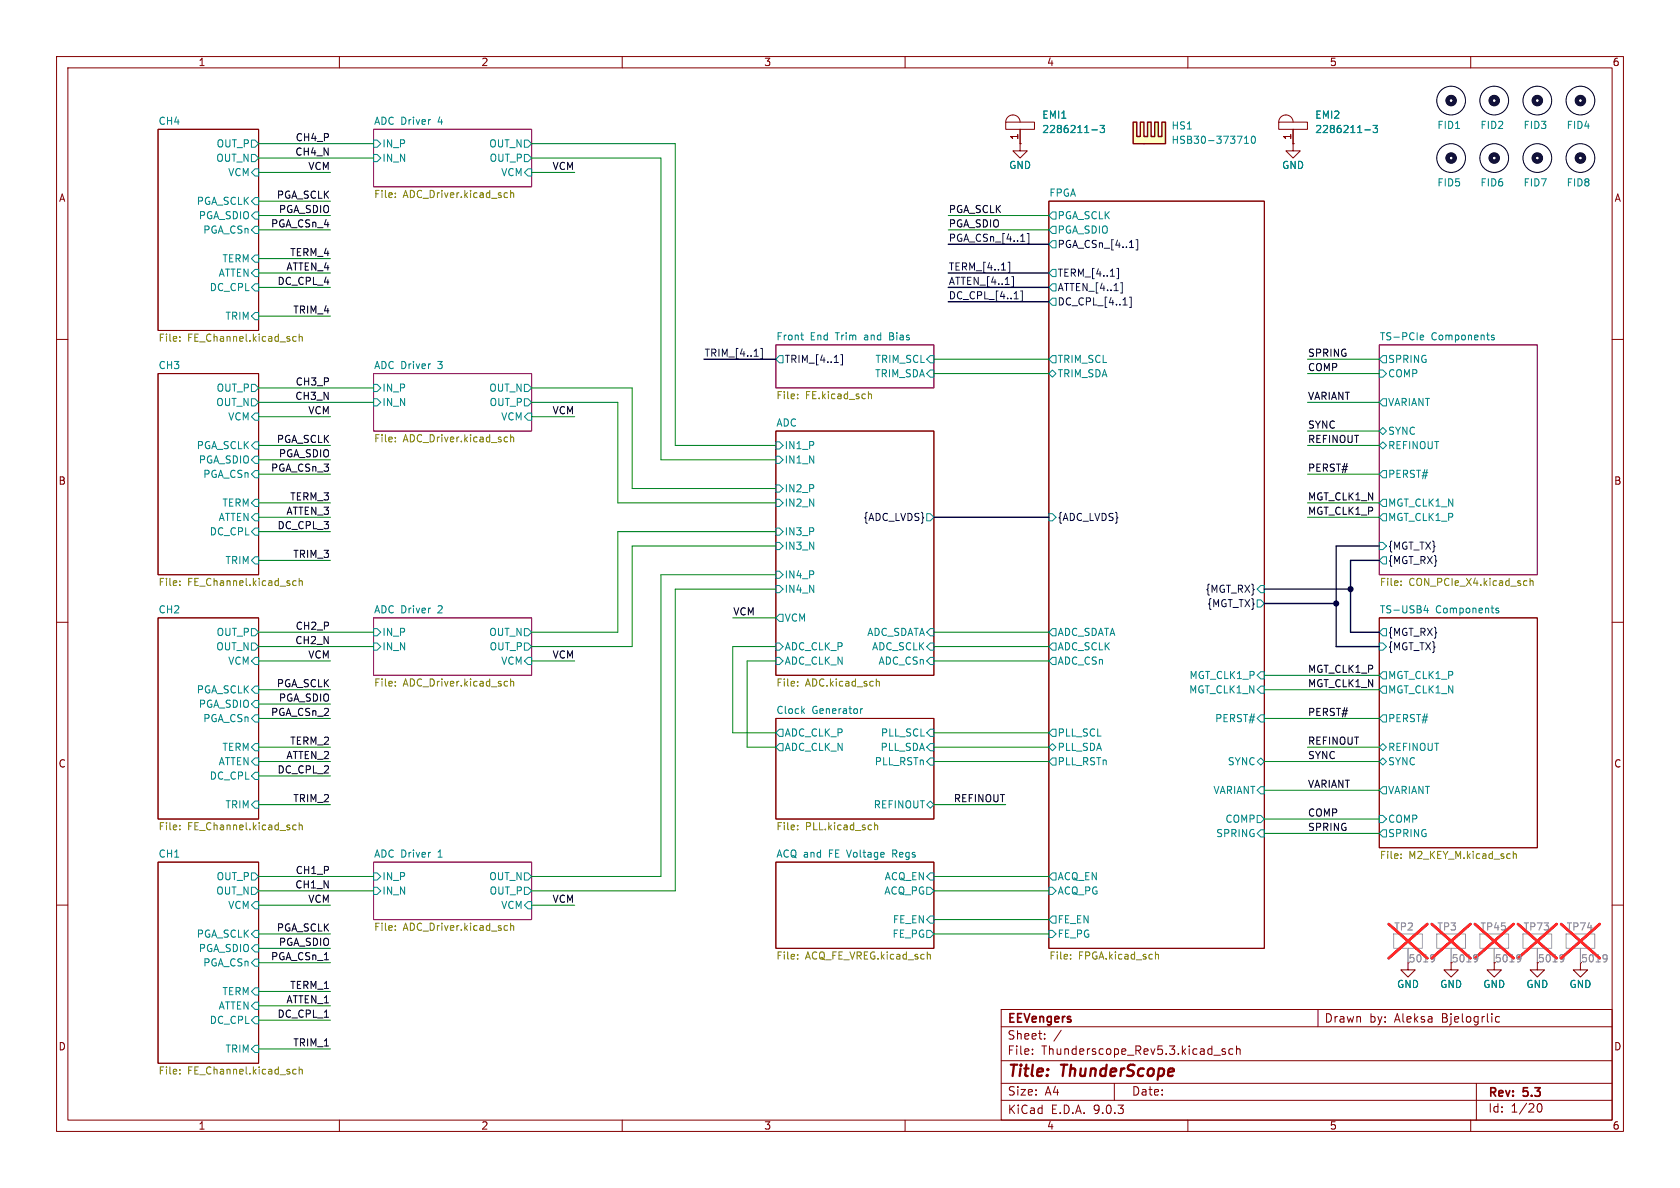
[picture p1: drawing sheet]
<svg xmlns="http://www.w3.org/2000/svg" width="297mm" height="210mm" viewBox="0 0 297 210" stroke-linecap="round" stroke-linejoin="round" font-family="sans-serif">
<defs><g id="words">
<g font-size="2.8" fill="#840000">
<text x="178" y="190.9">Title:</text>
<text x="187.7" y="190.9">ThunderScope</text>
</g>
<g font-size="2.1" fill="#840000">
<text x="178" y="184">Sheet:</text>
<text x="178" y="181.2">EEVengers</text>
<text x="234.1" y="181">Drawn</text>
<text x="242.1" y="181">by:</text>
<text x="246.6" y="181">Aleksa</text>
<text x="255" y="181">Bjelogrlic</text>
<text x="178" y="186.7">File:</text>
<text x="184.1" y="186.7">Thunderscope_Rev5.3.kicad_sch</text>
<text x="178.1" y="197.1">KiCad</text>
<text x="178.1" y="193.9">Size:</text>
<text x="184.7" y="193.9">A4</text>
<text x="185.8" y="197.1">E.D.A.</text>
<text x="193.4" y="197.1">9.0.3</text>
<text x="200" y="193.9">Date:</text>
<text x="263" y="194.3">Rev:</text>
<text x="263" y="196.9">Id:</text>
<text x="267.1" y="196.9">1/20</text>
<text x="269.4" y="194.3">5.3</text>
</g>
<g font-size="1.8" fill="#840000">
<text x="35" y="11.9">1</text>
<text x="85" y="11.9">2</text>
<text x="135" y="11.9">3</text>
<text x="185" y="11.9">4</text>
<text x="235" y="11.9">5</text>
<text x="285" y="11.9">6</text>
<text x="180.1" y="24.8" transform="rotate(-90 180.1 24.8)">1</text>
<text x="228.3" y="24.8" transform="rotate(-90 228.3 24.8)">1</text>
<text x="10.3" y="35.9">A</text>
<text x="285.3" y="35.9">A</text>
<text x="10.3" y="85.9">B</text>
<text x="285.3" y="85.9">B</text>
<text x="10.3" y="135.9">C</text>
<text x="285.3" y="135.9">C</text>
<text x="256.5" y="170.3">5019</text>
<text x="264.2" y="170.3">5019</text>
<text x="271.8" y="170.3">5019</text>
<text x="10.3" y="185.9">D</text>
<text x="285.3" y="185.9">D</text>
<text x="35" y="199.9">1</text>
<text x="85" y="199.9">2</text>
<text x="135" y="199.9">3</text>
<text x="185" y="199.9">4</text>
<text x="235" y="199.9">5</text>
<text x="285" y="199.9">6</text>
</g>
<g font-size="1.8" fill="#008484">
<text x="27.9" y="22.1">CH4</text>
<text x="66" y="22.1">ADC Driver</text>
<text x="77.5" y="22.1">4</text>
<text x="184.2" y="21.2">EMI1</text>
<text x="184.2" y="23.7">2286211-3</text>
<text x="207" y="23.1">HS1</text>
<text x="232.4" y="21.2">EMI2</text>
<text x="232.4" y="23.7">2286211-3</text>
<text x="254" y="23">FID1</text>
<text x="261.6" y="23">FID2</text>
<text x="269.2" y="23">FID3</text>
<text x="276.9" y="23">FID4</text>
<text x="38.1" y="28.8">OUT_N</text>
<text x="38.2" y="26.3">OUT_P</text>
<text x="67.5" y="28.8">IN_N</text>
<text x="67.5" y="26.3">IN_P</text>
<text x="86.4" y="26.3">OUT_N</text>
<text x="86.5" y="28.8">OUT_P</text>
<text x="207" y="25.6">HSB30-373710</text>
<text x="40.2" y="31.3">VCM</text>
<text x="88.5" y="31.3">VCM</text>
<text x="178.3" y="30.1">GND</text>
<text x="185.4" y="34.8">FPGA</text>
<text x="226.6" y="30.1">GND</text>
<text x="254" y="33.2">FID5</text>
<text x="261.6" y="33.2">FID6</text>
<text x="269.2" y="33.2">FID7</text>
<text x="276.9" y="33.2">FID8</text>
<text x="34.7" y="36.4">PGA_SCLK</text>
<text x="35" y="39">PGA_SDIO</text>
<text x="35.8" y="41.5">PGA_CSn</text>
<text x="186.9" y="41.5">PGA_SDIO</text>
<text x="186.9" y="39">PGA_SCLK</text>
<text x="39.2" y="46.6">TERM</text>
<text x="37" y="51.7">DC_CPL</text>
<text x="38.6" y="49.1">ATTEN</text>
<text x="39.8" y="56.7">TRIM</text>
<text x="27.9" y="65.3">CH3</text>
<text x="66" y="65.3">ADC Driver</text>
<text x="77.5" y="65.3">3</text>
<text x="137.2" y="60.2">Front</text>
<text x="143.2" y="60.2">End</text>
<text x="147.8" y="60.2">Trim</text>
<text x="153.1" y="60.2">and</text>
<text x="154.7" y="64.4">TRIM_SCL</text>
<text x="157.7" y="60.2">Bias</text>
<text x="186.9" y="64.4">TRIM_SCL</text>
<text x="243.8" y="60.2">TS-PCIe</text>
<text x="245.3" y="64.4">SPRING</text>
<text x="253" y="60.2">Components</text>
<text x="38.1" y="72">OUT_N</text>
<text x="38.2" y="69.4">OUT_P</text>
<text x="67.5" y="72">IN_N</text>
<text x="67.5" y="69.4">IN_P</text>
<text x="86.4" y="69.4">OUT_N</text>
<text x="86.5" y="72">OUT_P</text>
<text x="154.6" y="66.9">TRIM_SDA</text>
<text x="186.9" y="66.9">TRIM_SDA</text>
<text x="245.3" y="72">VARIANT</text>
<text x="245.3" y="66.9">COMP</text>
<text x="40.2" y="74.5">VCM</text>
<text x="88.5" y="74.5">VCM</text>
<text x="137.2" y="75.5">ADC</text>
<text x="245.3" y="77.1">SYNC</text>
<text x="34.7" y="79.6">PGA_SCLK</text>
<text x="35" y="82.1">PGA_SDIO</text>
<text x="138.6" y="82.1">IN1_N</text>
<text x="138.6" y="79.6">IN1_P</text>
<text x="245.3" y="79.6">REFINOUT</text>
<text x="35.8" y="84.7">PGA_CSn</text>
<text x="39.2" y="89.8">TERM</text>
<text x="138.6" y="89.8">IN2_N</text>
<text x="138.6" y="87.2">IN2_P</text>
<text x="245.3" y="84.7">PERST#</text>
<text x="245.3" y="89.8">MGT_CLK1_N</text>
<text x="37" y="94.8">DC_CPL</text>
<text x="38.6" y="92.3">ATTEN</text>
<text x="138.6" y="94.8">IN3_P</text>
<text x="245.3" y="92.3">MGT_CLK1_P</text>
<text x="39.8" y="99.9">TRIM</text>
<text x="138.6" y="97.4">IN3_N</text>
<text x="138.6" y="105">IN4_N</text>
<text x="138.6" y="102.5">IN4_P</text>
<text x="27.9" y="108.5">CH2</text>
<text x="38.2" y="112.6">OUT_P</text>
<text x="66" y="108.5">ADC Driver</text>
<text x="67.5" y="112.6">IN_P</text>
<text x="77.5" y="108.5">2</text>
<text x="86.4" y="112.6">OUT_N</text>
<text x="138.6" y="110.1">VCM</text>
<text x="153.2" y="112.6">ADC_SDATA</text>
<text x="186.9" y="112.6">ADC_SDATA</text>
<text x="243.8" y="108.5">TS-USB4</text>
<text x="253.8" y="108.5">Components</text>
<text x="38.1" y="115.2">OUT_N</text>
<text x="40.2" y="117.7">VCM</text>
<text x="67.5" y="115.2">IN_N</text>
<text x="86.5" y="115.2">OUT_P</text>
<text x="88.5" y="117.7">VCM</text>
<text x="138.6" y="115.2">ADC_CLK_P</text>
<text x="138.6" y="117.7">ADC_CLK_N</text>
<text x="154.1" y="115.2">ADC_SCLK</text>
<text x="155.2" y="117.7">ADC_CSn</text>
<text x="186.9" y="117.7">ADC_CSn</text>
<text x="186.9" y="115.2">ADC_SCLK</text>
<text x="34.7" y="122.8">PGA_SCLK</text>
<text x="35" y="125.3">PGA_SDIO</text>
<text x="210.1" y="122.8">MGT_CLK1_N</text>
<text x="210.2" y="120.2">MGT_CLK1_P</text>
<text x="245.3" y="122.8">MGT_CLK1_N</text>
<text x="245.3" y="120.2">MGT_CLK1_P</text>
<text x="35.8" y="127.9">PGA_CSn</text>
<text x="137.2" y="126.3">Clock</text>
<text x="138.6" y="130.4">ADC_CLK_P</text>
<text x="143.5" y="126.3">Generator</text>
<text x="155.6" y="130.4">PLL_SCL</text>
<text x="186.9" y="130.4">PLL_SCL</text>
<text x="214.7" y="127.9">PERST#</text>
<text x="245.3" y="127.9">PERST#</text>
<text x="38.6" y="135.5">ATTEN</text>
<text x="39.2" y="132.9">TERM</text>
<text x="138.6" y="132.9">ADC_CLK_N</text>
<text x="154.5" y="135.5">PLL_RSTn</text>
<text x="155.6" y="132.9">PLL_SDA</text>
<text x="186.9" y="135.5">PLL_RSTn</text>
<text x="186.9" y="132.9">PLL_SDA</text>
<text x="217" y="135.5">SYNC</text>
<text x="245.3" y="132.9">REFINOUT</text>
<text x="245.3" y="135.5">SYNC</text>
<text x="37" y="138">DC_CPL</text>
<text x="39.8" y="143.1">TRIM</text>
<text x="154.4" y="143.1">REFINOUT</text>
<text x="214.4" y="140.6">VARIANT</text>
<text x="245.3" y="140.6">VARIANT</text>
<text x="214.9" y="148.2">SPRING</text>
<text x="216.5" y="145.6">COMP</text>
<text x="245.3" y="148.2">SPRING</text>
<text x="245.3" y="145.6">COMP</text>
<text x="27.9" y="151.7">CH1</text>
<text x="38.2" y="155.8">OUT_P</text>
<text x="66" y="151.7">ADC Driver</text>
<text x="67.5" y="155.8">IN_P</text>
<text x="77.5" y="151.7">1</text>
<text x="86.4" y="155.8">OUT_N</text>
<text x="137.2" y="151.7">ACQ and</text>
<text x="146.6" y="151.7">FE Voltage</text>
<text x="156.3" y="155.8">ACQ_EN</text>
<text x="158.2" y="151.7">Regs</text>
<text x="186.9" y="155.8">ACQ_EN</text>
<text x="38.1" y="158.3">OUT_N</text>
<text x="40.2" y="160.9">VCM</text>
<text x="67.5" y="158.3">IN_N</text>
<text x="86.5" y="158.3">OUT_P</text>
<text x="88.5" y="160.9">VCM</text>
<text x="156.2" y="158.3">ACQ_PG</text>
<text x="186.9" y="158.3">ACQ_PG</text>
<text x="34.7" y="166">PGA_SCLK</text>
<text x="157.7" y="166">FE_PG</text>
<text x="157.8" y="163.4">FE_EN</text>
<text x="186.9" y="163.4">FE_EN</text>
<text x="186.9" y="166">FE_PG</text>
<text x="35" y="168.5">PGA_SDIO</text>
<text x="35.8" y="171">PGA_CSn</text>
<text x="38.6" y="178.7">ATTEN</text>
<text x="39.2" y="176.1">TERM</text>
<text x="246.9" y="174.9">GND</text>
<text x="254.5" y="174.9">GND</text>
<text x="262.1" y="174.9">GND</text>
<text x="269.7" y="174.9">GND</text>
<text x="277.4" y="174.9">GND</text>
<text x="37" y="181.2">DC_CPL</text>
<text x="39.8" y="186.3">TRIM</text>
</g>
<g font-size="1.8">
<text x="52.1" y="27.6">CH4_N</text>
<text x="52.2" y="25.1">CH4_P</text>
<text x="48.8" y="35.2">PGA_SCLK</text>
<text x="54.4" y="30.1">VCM</text>
<text x="97.6" y="30.1">VCM</text>
<text x="47.8" y="40.3">PGA_CSn_4</text>
<text x="49.2" y="37.8">PGA_SDIO</text>
<text x="167.6" y="40.3">PGA_SDIO</text>
<text x="167.6" y="37.8">PGA_SCLK</text>
<text x="50.5" y="47.9">ATTEN_4</text>
<text x="51.2" y="45.4">TERM_4</text>
<text x="49" y="50.5">DC_CPL_4</text>
<text x="51.7" y="55.5">TRIM_4</text>
<text x="231.1" y="63.2">SPRING</text>
<text x="231.1" y="65.7">COMP</text>
<text x="52.1" y="70.8">CH3_N</text>
<text x="52.2" y="68.2">CH3_P</text>
<text x="231.1" y="70.8">VARIANT</text>
<text x="54.4" y="73.3">VCM</text>
<text x="97.6" y="73.3">VCM</text>
<text x="231.1" y="75.9">SYNC</text>
<text x="47.8" y="83.5">PGA_CSn_3</text>
<text x="48.8" y="78.4">PGA_SCLK</text>
<text x="49.2" y="80.9">PGA_SDIO</text>
<text x="231.1" y="83.5">PERST#</text>
<text x="231.1" y="78.4">REFINOUT</text>
<text x="51.2" y="88.6">TERM_3</text>
<text x="231.1" y="88.6">MGT_CLK1_N</text>
<text x="49" y="93.6">DC_CPL_3</text>
<text x="50.5" y="91.1">ATTEN_3</text>
<text x="231.1" y="91.1">MGT_CLK1_P</text>
<text x="51.7" y="98.7">TRIM_3</text>
<text x="52.1" y="114">CH2_N</text>
<text x="52.2" y="111.4">CH2_P</text>
<text x="129.5" y="108.9">VCM</text>
<text x="54.4" y="116.5">VCM</text>
<text x="97.6" y="116.5">VCM</text>
<text x="231.1" y="119">MGT_CLK1_P</text>
<text x="48.8" y="121.6">PGA_SCLK</text>
<text x="49.2" y="124.1">PGA_SDIO</text>
<text x="231.1" y="121.6">MGT_CLK1_N</text>
<text x="47.8" y="126.7">PGA_CSn_2</text>
<text x="51.2" y="131.7">TERM_2</text>
<text x="231.1" y="126.7">PERST#</text>
<text x="231.1" y="131.7">REFINOUT</text>
<text x="49" y="136.8">DC_CPL_2</text>
<text x="50.5" y="134.3">ATTEN_2</text>
<text x="231.1" y="134.3">SYNC</text>
<text x="51.7" y="141.9">TRIM_2</text>
<text x="168.5" y="141.9">REFINOUT</text>
<text x="231.1" y="139.4">VARIANT</text>
<text x="231.1" y="144.4">COMP</text>
<text x="231.1" y="147">SPRING</text>
<text x="52.2" y="154.6">CH1_P</text>
<text x="52.1" y="157.1">CH1_N</text>
<text x="54.4" y="159.7">VCM</text>
<text x="97.6" y="159.7">VCM</text>
<text x="48.8" y="164.8">PGA_SCLK</text>
<text x="49.2" y="167.3">PGA_SDIO</text>
<text x="47.8" y="169.8">PGA_CSn_1</text>
<text x="49" y="180">DC_CPL_1</text>
<text x="50.5" y="177.5">ATTEN_1</text>
<text x="51.2" y="174.9">TERM_1</text>
<text x="51.7" y="185.1">TRIM_1</text>
</g>
<g font-size="1.8" fill="#848400">
<text x="66" y="35.3">File:</text>
<text x="71.3" y="35.3">ADC_Driver.kicad_sch</text>
<text x="27.9" y="60.7">File:</text>
<text x="33.2" y="60.7">FE_Channel.kicad_sch</text>
<text x="137.2" y="70.9">File:</text>
<text x="142.4" y="70.9">FE.kicad_sch</text>
<text x="66" y="78.5">File:</text>
<text x="71.3" y="78.5">ADC_Driver.kicad_sch</text>
<text x="27.9" y="103.9">File:</text>
<text x="33.2" y="103.9">FE_Channel.kicad_sch</text>
<text x="243.8" y="103.9">File:</text>
<text x="249.1" y="103.9">CON_PCIe_X4.kicad_sch</text>
<text x="66" y="121.7">File:</text>
<text x="71.3" y="121.7">ADC_Driver.kicad_sch</text>
<text x="137.2" y="121.7">File:</text>
<text x="142.4" y="121.7">ADC.kicad_sch</text>
<text x="27.9" y="147.1">File:</text>
<text x="33.2" y="147.1">FE_Channel.kicad_sch</text>
<text x="137.2" y="147.1">File:</text>
<text x="142.4" y="147.1">PLL.kicad_sch</text>
<text x="243.8" y="152.2">File:</text>
<text x="249.1" y="152.2">M2_KEY_M.kicad_sch</text>
<text x="66" y="164.9">File:</text>
<text x="71.3" y="164.9">ADC_Driver.kicad_sch</text>
<text x="137.2" y="170">File:</text>
<text x="142.4" y="170">ACQ_FE_VREG.kicad_sch</text>
<text x="185.4" y="170">File:</text>
<text x="190.6" y="170">FPGA.kicad_sch</text>
<text x="27.9" y="190.3">File:</text>
<text x="33.2" y="190.3">FE_Channel.kicad_sch</text>
</g>
<g font-size="1.8" fill="#000084">
<text x="167.6" y="47.9">TERM_[4..1]</text>
<text x="167.6" y="42.8">PGA_CSn_[4..1]</text>
<text x="186.9" y="44">PGA_CSn_[4..1]</text>
<text x="167.6" y="50.5">ATTEN_[4..1]</text>
<text x="167.6" y="53">DC_CPL_[4..1]</text>
<text x="186.9" y="51.7">ATTEN_[4..1]</text>
<text x="186.9" y="49.1">TERM_[4..1]</text>
<text x="186.9" y="54.2">DC_CPL_[4..1]</text>
<text x="124.5" y="63.2">TRIM_[4..1]</text>
<text x="138.6" y="64.4">TRIM_[4..1]</text>
<text x="152.6" y="92.3">{ADC_LVDS}</text>
<text x="186.9" y="92.3">{ADC_LVDS}</text>
<text x="245.3" y="99.9">{MGT_RX}</text>
<text x="245.3" y="97.4">{MGT_TX}</text>
<text x="213" y="105">{MGT_RX}</text>
<text x="213.3" y="107.5">{MGT_TX}</text>
<text x="245.3" y="112.6">{MGT_RX}</text>
<text x="245.3" y="115.2">{MGT_TX}</text>
</g>
<g font-size="1.8" fill="#a1a1a1">
<text x="246.4" y="164.7">TP2</text>
<text x="254" y="164.7">TP3</text>
<text x="261.6" y="164.7">TP45</text>
<text x="269.2" y="164.7">TP73</text>
<text x="276.9" y="164.7">TP74</text>
<text x="248.9" y="170.3">5019</text>
<text x="279.4" y="170.3">5019</text>
</g>
</g></defs>
<path d="M0 0h297v210h-297z" fill="#fff" stroke="#fff" stroke-width=".18"/>
<g fill="none" stroke="#840000" stroke-width=".18">
<path d="M10 10h277v190h-277zM12 12h273v186h-273zM60 10v2M110 10v2M160 10v2M210 10v2M260 10v2M177.8 21.6h5.1v1.3h-5.1zM177.8 21.6a1.27 1.27 0 0 1 1.3-1.3 1.27 1.27 0 0 1 1.2 1.3M180.3 25.4v1.3h1.3l-1.3 1.2-1.2-1.2h1.2M180.3 25.4h.1M180.3 22.9v2.5"/>
<path d="M226.1 21.6h5v1.3h-5zM226.1 21.6a1.27 1.27 0 0 1 1.2-1.3 1.27 1.27 0 0 1 1.3 1.3M228.6 25.4v1.3h1.3l-1.3 1.2-1.3-1.2h1.3M228.6 25.4h.1M228.6 22.9v2.5M10 60h2M285 60h2M10 110h2M285 110h2M10 160h2M177 178.5h108v19.5h-108zM233 178.5v3"/>
<path d="M248.9 170.2v1.3h1.3l-1.3 1.2-1.3-1.2h1.3M256.5 170.2v1.3h1.3l-1.3 1.2-1.2-1.2h1.2M264.2 170.2v1.3h1.2l-1.2 1.2-1.3-1.2h1.3M265.1 179.8l-.4-.1-.3 .3v.4l.1 .2h.6M271.8 170.2v1.3h1.2l-1.2 1.2-1.3-1.2h1.3M279.4 170.2v1.3h1.3l-1.3 1.2-1.3-1.2h1.3M285 160h2M60 198v2M110 198v2M160 198v2M177 194.5h108M177 191.5h108"/>
<path d="M177 187.5h108M177 181.5h108M182.5 186.3v.1M182.5 185.5v.1M184.7 183.6v.1M184.7 182.8v.1M187.6 182.1l-1.3 2M197 191.5v3M210 198v2M214.6 186.5h1.1M216.6 185.5l-.4-.1-.2 .2 .1 .2 .5 .2v.3h-.6M218 185.5l-.5-.1-.3 .3v.4l.2 .2h.6"/>
<path d="M218.6 185.5l.2-.1 .4 .1v.9M218.6 184.9v1.5M260 198v2M261 191.5v6.5M271.7 195.7l.2-.5 .2-.1a.81 .81 0 0 1 .6 .6 .81 .81 0 0 1-.3 .8h-.4l-.3-.5"/>
</g>
<path d="M27.9 22.9h17.8v35.5h-17.8zM185.4 35.6h38.1v132h-38.1zM27.9 66h17.8v35.6h-17.8zM137.2 76.2h27.9v43.2h-27.9zM27.9 109.2h17.8v35.6h-17.8zM243.8 109.2h28v40.7h-28zM137.2 127h27.9v17.8h-27.9zM27.9 152.4h17.8v35.6h-17.8zM137.2 152.4h27.9v15.2h-27.9z" fill="none" stroke="#800000" stroke-width=".18"/>
<path d="M66 22.9h28v10.1h-28zM66 66h28v10.2h-28zM137.2 61h27.9v7.6h-27.9zM243.8 61h28v40.6h-28zM66 109.2h28v10.2h-28zM66 152.4h28v10.2h-28z" fill="none" stroke="#840084" stroke-width=".18"/>
<g fill="none" stroke="#008484" stroke-width=".18">
<path d="M44.4 24.8h.7l.6 .6-.6 .6h-.7zM44.4 30.5l.7-.7h.6v1.3h-.6zM44.4 27.3h.7l.6 .6-.6 .7h-.7zM44.4 35.6l.7-.7h.6v1.3h-.6zM44.4 38.1l.7-.6h.6v1.2h-.6zM66 27.3h.7l.6 .6-.6 .7h-.7zM66 24.8h.7l.6 .6-.6 .6h-.7zM92.7 24.8h.6l.7 .6-.7 .6h-.6zM92.7 27.3h.6l.7 .6-.7 .7h-.6zM93.3 29.8h.7v1.3h-.7l-.6-.6zM186.1 37.5h.6v1.2h-.6l-.7-.6zM193 23h1"/>
<path d="M194.5 22.2h.8l-.5 .5 .4 .1v.5l-.2 .1-.5-.1M241.3 23h1M242.7 22.2h.8l-.4 .5 .4 .1v.5l-.2 .1-.6-.1M44.4 55.9l.7-.7h.6v1.3h-.6zM44.4 48.3l.7-.7h.6v1.3h-.6zM44.4 50.8l.7-.6h.6v1.2h-.6zM44.4 40.6l.7-.6h.6v1.3h-.6zM44.4 45.7l.7-.6h.6v1.3h-.6zM141.6 59.2h.4M186.1 40h.6v1.3h-.6l-.7-.7zM186.1 50.2h.6v1.2h-.6l-.7-.6zM186.1 47.6h.6v1.3h-.6l-.7-.6z"/>
<path d="M186.1 52.7h.6v1.3h-.6l-.7-.7zM186.1 42.5h.6v1.3h-.6l-.7-.6zM251.1 59.3l.4-.1 .2 .3-.6 .2M264.1 59.3l-.3-.1-.1 .2v.2l.4 .1v.3h-.4M44.4 67.9h.7l.6 .7-.6 .6h-.7zM44.4 73.7l.7-.7h.6v1.3h-.6zM44.4 70.5h.7l.6 .6-.6 .7h-.7zM44.4 78.7l.7-.6h.6v1.3h-.6zM66 70.5h.7l.6 .6-.6 .7h-.7zM66 67.9h.7l.6 .7-.6 .6h-.7zM92.7 67.9h.6l.7 .7-.7 .6h-.6zM92.7 70.5h.6l.7 .6-.7 .7h-.6z"/>
<path d="M93.3 73h.7v1.3h-.7l-.6-.6zM137.2 78.1h.6l.6 .6-.6 .7h-.6zM137.8 62.9h.6v1.2h-.6l-.6-.6zM141.8 60l.2 .1M164.5 62.9h.6v1.2h-.6l-.7-.6zM164.5 65.4h.6v1.3h-.6l-.7-.7zM185.4 66l.7-.6 .6 .6-.6 .7zM186.1 62.9h.6v1.2h-.6l-.7-.6zM243.8 78.7l.7-.6 .6 .6-.6 .7zM243.8 76.2l.7-.6 .6 .6-.6 .6zM243.8 65.4h.7l.6 .6-.6 .7h-.7zM244.5 70.5h.6v1.3h-.6l-.7-.7z"/>
<path d="M244.5 62.9h.6v1.2h-.6l-.7-.6zM251.1 60h.5M44.4 94l.7-.7h.6v1.3h-.6zM44.4 81.3l.7-.7h.6v1.3h-.6zM45.1 98.4h.6v1.3h-.6l-.7-.6zM45.1 90.8h.6v1.3h-.6l-.7-.7zM45.1 83.2h.6v1.3h-.6l-.7-.7zM45.1 88.3h.6v1.2h-.6l-.7-.6zM137.2 95.9h.6l.6 .6-.6 .7h-.6zM137.2 93.3h.6l.6 .7-.6 .6h-.6zM137.2 88.3h.6l.6 .6-.6 .6h-.6zM137.2 85.7h.6l.6 .7-.6 .6h-.6z"/>
<path d="M137.2 80.6h.6l.6 .7-.6 .6h-.6zM163.8 90.8h.7l.6 .6-.6 .7h-.7zM185.4 90.8h.7l.6 .6-.6 .7h-.7zM243.8 95.9h.7l.6 .6-.6 .7h-.7zM244.5 98.4h.6v1.3h-.6l-.7-.6zM244.5 83.2h.6v1.3h-.6l-.7-.7zM244.5 88.3h.6v1.2h-.6l-.7-.6zM244.5 90.8h.6v1.3h-.6l-.7-.7zM44.4 111.1h.7l.6 .7-.6 .6h-.7zM44.4 116.8l.7-.6h.6v1.3h-.6zM44.4 113.7h.7l.6 .6-.6 .6h-.7zM66 113.7h.7l.6 .6-.6 .6h-.7z"/>
<path d="M66 111.1h.7l.6 .7-.6 .6h-.7zM92.7 111.1h.6l.7 .7-.7 .6h-.6zM92.7 113.7h.6l.7 .6-.7 .6h-.6zM93.3 116.2h.7v1.3h-.7l-.6-.7zM137.2 103.5h.6l.6 .6-.6 .7h-.6zM137.2 101h.6l.6 .6-.6 .6h-.6zM137.2 109.2l.6-.6h.6v1.3h-.6zM137.2 113.7h.6l.6 .6-.6 .6h-.6zM137.2 116.2h.6l.6 .6-.6 .7h-.6zM164.5 116.2h.6v1.3h-.6l-.7-.7zM164.5 111.1h.6v1.3h-.6l-.7-.6zM164.5 113.7h.6v1.2h-.6l-.7-.6z"/>
<path d="M186.1 116.2h.6v1.3h-.6l-.7-.7zM186.1 111.1h.6v1.3h-.6l-.7-.6zM186.1 113.7h.6v1.2h-.6l-.7-.6zM222.2 106h.7l.6 .7-.6 .6h-.7zM222.9 118.7h.6v1.3h-.6l-.7-.6zM222.9 103.5h.6v1.3h-.6l-.7-.7zM243.8 113.7h.7l.6 .6-.6 .6h-.7zM244.5 111.1h.6v1.3h-.6l-.7-.6zM244.5 118.7h.6v1.3h-.6l-.7-.6zM252 107l-.3 .9h.8M252.3 107.5v.8M264.9 107.6l-.3-.1-.2 .2 .1 .2 .4 .1v.3h-.5"/>
<path d="M44.4 134.6l.7-.6h.6v1.3h-.6zM45.1 136.5h.6v1.3h-.6l-.7-.6zM45.1 126.4h.6v1.2h-.6l-.7-.6zM45.1 121.3h.6v1.3h-.6l-.7-.7zM45.1 123.8h.6v1.3h-.6l-.7-.6zM45.1 131.4h.6v1.3h-.6l-.7-.6zM137.2 129.5l.6-.6h.6v1.3h-.6zM137.8 131.4h.6v1.3h-.6l-.6-.6zM141.9 125.6l.3 .5M142.2 125.3l-.5 .5M152.1 125.3v.8M152.5 125.3l-.4 .2"/>
<path d="M164.5 134h.6v1.3h-.6l-.7-.7zM164.5 131.4h.6v1.3h-.6l-.7-.6zM164.5 128.9h.6v1.3h-.6l-.7-.7zM185.4 132.1l.7-.7 .6 .7-.6 .6zM186.1 134h.6v1.3h-.6l-.7-.7zM186.1 128.9h.6v1.3h-.6l-.7-.7zM222.2 134.6l.7-.6 .6 .6-.6 .7zM222.9 126.4h.6v1.2h-.6l-.7-.6zM222.9 121.3h.6v1.3h-.6l-.7-.7zM222.9 139.1h.6v1.2h-.6l-.7-.6zM243.8 132.1l.7-.7 .6 .7-.6 .6zM243.8 134.6l.7-.6 .6 .6-.6 .7z"/>
<path d="M244.5 126.4h.6v1.2h-.6l-.7-.6zM244.5 121.3h.6v1.3h-.6l-.7-.7zM244.5 139.1h.6v1.2h-.6l-.7-.6zM44.4 154.3h.7l.6 .6-.6 .7h-.7zM44.4 156.8h.7l.6 .7-.6 .6h-.7zM45.1 141.6h.6v1.3h-.6l-.7-.7zM45.1 159.4h.6v1.3h-.6l-.7-.7zM66 156.8h.7l.6 .7-.6 .6h-.7zM66 154.3h.7l.6 .6-.6 .7h-.7zM92.7 154.3h.6l.7 .6-.7 .7h-.6zM92.7 156.8h.6l.7 .7-.7 .6h-.6zM93.3 159.4h.7v1.3h-.7l-.6-.7z"/>
<path d="M163.8 142.2l.7-.6 .6 .6-.6 .7zM163.8 156.8h.7l.6 .7-.6 .6h-.7zM164.5 154.3h.6v1.3h-.6l-.7-.7zM185.4 156.8h.7l.6 .7-.6 .6h-.7zM186.1 154.3h.6v1.3h-.6l-.7-.7zM222.2 144.1h.7l.6 .7-.6 .6h-.7zM222.9 146.7h.6v1.3h-.6l-.7-.7zM243.8 144.1h.7l.6 .7-.6 .6h-.7zM244.5 146.7h.6v1.3h-.6l-.7-.7zM44.4 170.2l.7-.7h.6v1.3h-.6zM44.4 175.3l.7-.7h.6v1.3h-.6zM45.1 177.2h.6v1.2h-.6l-.7-.6z"/>
<path d="M45.1 164.5h.6v1.2h-.6l-.7-.6zM45.1 167h.6v1.3h-.6l-.7-.7zM163.8 164.5h.7l.6 .6-.6 .6h-.7zM164.5 161.9h.6v1.3h-.6l-.7-.6zM185.4 164.5h.7l.6 .6-.6 .6h-.7zM186.1 161.9h.6v1.3h-.6l-.7-.6zM44.4 185.4l.7-.6h.6v1.3h-.6zM44.4 180.3l.7-.6h.6v1.3h-.6z"/>
</g>
<g fill="none" stroke="#848400" stroke-width=".18">
<path d="M69.9 34.1v.2M69.9 34.8v.1M89.4 34.1h.3M89.7 34.9h-.3M90.3 33.7v1.2M90.3 34.2l.2-.1h.3v.8M31.8 59.5v.2M52.4 59.5h-.4l-.2 .1M52.9 59.1v1.2M52.9 59.6l.2-.1h.3v.8M31.8 60.2v.1M51.8 60.2l.2 .1h.4"/>
<path d="M69.9 77.3v.1M69.9 78v.1M89.4 77.3h.3M89.7 78l-.3 .1M90.3 76.8v1.3M90.3 77.4l.2-.1h.3v.8M141 70.4v.1M141 69.7v.1M153.5 69.2v1.3M153.5 69.8l.2-.2 .3 .1 .1 .8M31.8 103.4v.1M31.8 102.7v.1"/>
<path d="M51.8 103.4l.2 .1 .4-.1M52.4 102.7h-.4l-.2 .1M52.9 102.8l.2-.1h.3v.8M52.9 102.2v1.3M247.7 102.7v.1M247.7 103.4v.1M269.8 102.7h.1M269.9 103.4l-.1 .1M270.5 102.8l.2-.1h.3v.8M270.5 102.2v1.3M69.9 120.5v.1M69.9 121.2v.1"/>
<path d="M89.4 120.4l.3 .1M89.7 121.2l-.3 .1M90.3 120.6l.2-.2 .3 .1v.8M90.3 120v1.3M141 120.5v.1M141 121.2v.1M154.9 120.6l.2-.2 .3 .1 .1 .8M31.8 145.9v.1M31.8 146.6v.1M51.8 146.6l.2 .1 .4-.1M52.4 145.9l-.4-.1-.2 .2M52.9 145.4v1.3"/>
<path d="M52.9 146l.2-.2 .3 .1v.8M141 145.9v.1M141 146.6v.1M154.6 145.4v1.3M154.6 146l.2-.2 .3 .1 .1 .8M247.7 151.6v.2M247.7 151v.1M267.5 150.5v1.3M267.5 151l.2-.1 .3 .1 .1 .8M69.9 164.3v.2M69.9 163.7v.1M89.4 163.6l.3 .1"/>
<path d="M89.7 164.4l-.3 .1M90.3 163.7l.2-.1 .3 .1v.8M90.3 163.2v1.3M141 168.8v.1M141 169.4v.1M164.3 168.7l.2 .2v.6M189.3 169.4v.1M189.3 168.8v.1M204.3 168.8l.1-.1 .4 .1v.7M31.8 189.1v.1M31.8 189.7v.2M51.8 189.7l.2 .2 .4-.1"/>
<path d="M52.4 189.1l-.4-.1-.2 .1M52.9 188.6v1.3M52.9 189.1l.2-.1 .3 .1v.8"/>
</g>
<path d="M197.4 47.4h.3v1.9h-.3M198.1 50h.3v1.8h-.3M199.7 52.5h.3v1.8h-.3M200.8 42.4h.3v1.8h-.3M148.6 62.7h.3v1.8h-.3" fill="none" stroke="#000084" stroke-width=".18"/>
<g fill="none" stroke="#a1a1a1" stroke-width=".18">
<path d="M246.4 165.1h5.1v2.5h-5.1zM248.9 167.6v2.6M253.4 168.8l.2 .1a1.03 1.03 0 0 1-.2 1.1M253.6 169.3l-.2 .3M254 165.1h5.1v2.5h-5.1zM256.5 167.6v2.6M261 168.8l.2 .1a1.03 1.03 0 0 1-.2 1.1M261.2 169.3l-.2 .3M261.6 165.1h5.1v2.5h-5.1zM264.2 167.6v2.6M268.6 168.8l.2 .1a1.03 1.03 0 0 1-.2 1.1M268.9 169.3l-.3 .3"/>
<path d="M269.2 165.1h5.1v2.5h-5.1zM271.8 167.6v2.6M276.2 168.8l.2 .1a1.03 1.03 0 0 1-.2 1.1M276.5 169.3l-.3 .3M276.9 165.1h5v2.5h-5zM279.4 167.6v2.6M283.9 168.8l.1 .1a1.03 1.03 0 0 1-.1 1.1M284.1 169.3l-.2 .3"/>
</g>
<path d="M245.5 163.3l6.8 6.1M252.3 163.3l-6.8 6.1M253.1 163.3l6.9 6.1M260 163.3l-6.9 6.1M260.7 163.3l6.9 6.1M267.6 163.3l-6.9 6.1M268.4 163.3l6.8 6.1M275.2 163.3l-6.8 6.1M276 163.3l6.8 6.1M282.8 163.3l-6.8 6.1" fill="none" stroke="#ff2626" stroke-width=".46"/>
<g fill="none" stroke="#000" stroke-width=".76">
<circle cx="256.5" cy="17.8" r=".63"/>
<circle cx="264.2" cy="17.8" r=".63"/>
<circle cx="271.8" cy="17.8" r=".63"/>
<circle cx="279.4" cy="17.8" r=".63"/>
<circle cx="256.5" cy="27.9" r=".63"/>
<circle cx="264.2" cy="27.9" r=".63"/>
<circle cx="271.8" cy="27.9" r=".63"/>
<circle cx="279.4" cy="27.9" r=".63"/>
</g>
<g fill="none" stroke="#000" stroke-width=".18">
<circle cx="256.5" cy="17.8" r="2.54"/>
<circle cx="264.2" cy="17.8" r="2.54"/>
<circle cx="271.8" cy="17.8" r="2.54"/>
<circle cx="279.4" cy="17.8" r="2.54"/>
<circle cx="256.5" cy="27.9" r="2.54"/>
<circle cx="264.2" cy="27.9" r="2.54"/>
<circle cx="271.8" cy="27.9" r="2.54"/>
<circle cx="279.4" cy="27.9" r="2.54"/>
</g>
<g fill="#ffffc2">
<path d="M200.3 21.6h.7v2.5h.6v-2.5h.6v2.5h.7l-.7 1.3h-1.9z"/>
<path d="M202.9 21.6h.6v2.5h.6v-2.5h.7v2.5h.6v-2.5h.6v3.8h-3.8l.7-1.3z"/>
</g>
<path d="M200.3 21.6h.7v2.5h.6v-2.5h.6v2.5h.7v-2.5h.6v2.5h.6v-2.5h.7v2.5h.6v-2.5h.6v3.8h-5.7z" fill="none" stroke="#840000" stroke-width=".25"/>
<path d="M193 23h1M194.5 22.2h.8l-.5 .5 .4 .1v.5l-.2 .1-.5-.1M220 25.3h.7M220 24.4l.4-.3v1.2M221.3 24.2l.2-.1a.68 .68 0 0 1 .5 .6 .68 .68 0 0 1-.5 .6l-.2-.1-.1-.3zM241.3 23h1M242.7 22.2h.8l-.4 .5 .4 .1v.5l-.2 .1-.6-.1" fill="none" stroke="#008484" stroke-width=".18"/>
<path d="M178.2 46.4h.3v1.8h-.3M178.9 48.9h.3v1.8h-.3M180.4 51.4h.3v1.9h-.3M181.6 41.3h.3v1.8h-.3M134.5 61.6h.3v1.8h-.3" fill="none" stroke="#000084" stroke-width=".18"/>
<path d="M167.6 50.8h17.8M167.6 43.2h17.8M167.6 48.3h17.8M167.6 53.3h17.8M124.5 63.5h12.7M165.1 91.4h20.3M243.8 99.1h-5v12.7h5M243.8 96.5h-7.6v17.8h7.6M223.5 106.7h12.7M223.5 104.1h15.3" fill="none" stroke="#000084" stroke-width=".25"/>
<g fill="none" stroke="#008400" stroke-width=".18">
<path d="M45.7 25.4h20.3M45.7 27.9h20.3M45.7 35.6h12.7M45.7 38.1h12.7M45.7 30.5h12.7M94 25.4h25.4v53.3h17.8M94 27.9h22.8v53.4h20.4M94 30.5h7.6M167.6 38.1h17.8M45.7 40.6h12.7M45.7 45.7h12.7M45.7 55.9h12.7"/>
<path d="M45.7 50.8h12.7M45.7 48.3h12.7M167.6 40.6h17.8M45.7 73.7h12.7M45.7 71.1h20.3M45.7 68.6h20.3M45.7 78.7h12.7M94 73.7h7.6M94 71.1h15.2v17.8h28M94 68.6h17.8v17.8h25.4M165.1 63.5h20.3M165.1 66h20.3"/>
<path d="M231.1 71.1h12.7M231.1 63.5h12.7M231.1 66h12.7M231.1 78.7h12.7M231.1 76.2h12.7M45.7 88.9h12.7M45.7 91.4h12.7M45.7 99.1h12.7M45.7 94h12.7M45.7 81.3h12.7M45.7 83.8h12.7M137.2 96.5h-25.4v17.8h-17.8"/>
<path d="M137.2 94h-28v17.8h-15.2M231.1 88.9h12.7M231.1 91.4h12.7M231.1 83.8h12.7M45.7 114.3h20.3M45.7 116.8h12.7M45.7 111.8h20.3M94 116.8h7.6M129.5 109.2h7.7M137.2 104.1h-17.8v53.4h-25.4M137.2 101.6h-20.4v53.3h-22.8M137.2 116.8h-5.1v15.3h5.1"/>
<path d="M137.2 114.3h-7.7v15.2h7.7M165.1 114.3h20.3M165.1 116.8h20.3M165.1 111.8h20.3M223.5 119.4h20.3M45.7 137.2h12.7M45.7 134.6h12.7M45.7 121.9h12.7M45.7 132.1h12.7M45.7 127h12.7M45.7 124.5h12.7M165.1 134.6h20.3"/>
<path d="M165.1 132.1h20.3M165.1 129.5h20.3M223.5 134.6h20.3M223.5 121.9h20.3M223.5 127h20.3M223.5 139.7h20.3M231.1 132.1h12.7M45.7 142.2h12.7M45.7 157.5h20.3M45.7 154.9h20.3M165.1 142.2h12.7M165.1 157.5h20.3"/>
<path d="M165.1 154.9h20.3M223.5 144.8h20.3M223.5 147.3h20.3M45.7 177.8h12.7M45.7 170.2h12.7M45.7 167.6h12.7M45.7 175.3h12.7M45.7 165.1h12.7M45.7 160h12.7M94 160h7.6M165.1 165.1h20.3M165.1 162.6h20.3"/>
<path d="M45.7 180.3h12.7M45.7 185.4h12.7"/>
</g>
<g fill="none" stroke="#a1a1a1" stroke-width=".18">
<path d="M248.9 167.6v2.6M253.4 168.8l.2 .1a1.03 1.03 0 0 1-.2 1.1M253.6 169.3l-.2 .3M256.5 167.6v2.6M261 168.8l.2 .1a1.03 1.03 0 0 1-.2 1.1M261.2 169.3l-.2 .3M264.2 167.6v2.6M268.6 168.8l.2 .1a1.03 1.03 0 0 1-.2 1.1M268.9 169.3l-.3 .3M271.8 167.6v2.6M276.2 168.8l.2 .1a1.03 1.03 0 0 1-.2 1.1M276.5 169.3l-.3 .3"/>
<path d="M279.4 167.6v2.6M283.9 168.8l.1 .1a1.03 1.03 0 0 1-.1 1.1M284.1 169.3l-.2 .3"/>
</g>
<path d="M245.5 163.3l6.8 6.1M252.3 163.3l-6.8 6.1M253.1 163.3l6.9 6.1M260 163.3l-6.9 6.1M260.7 163.3l6.9 6.1M267.6 163.3l-6.9 6.1M268.4 163.3l6.8 6.1M275.2 163.3l-6.8 6.1M276 163.3l6.8 6.1M282.8 163.3l-6.8 6.1" fill="none" stroke="#ff2626" stroke-width=".46"/>
<path d="M180.3 25.4h.1M180.3 22.9v2.5M228.6 25.4h.1M228.6 22.9v2.5" fill="none" stroke="#840000" stroke-width=".18"/>
<g fill="#000084" stroke="#000084" stroke-width=".18">
<circle cx="238.8" cy="104.1" r=".46"/>
<circle cx="236.2" cy="106.7" r=".46"/>
</g>
<use href="#words"/>
</svg>
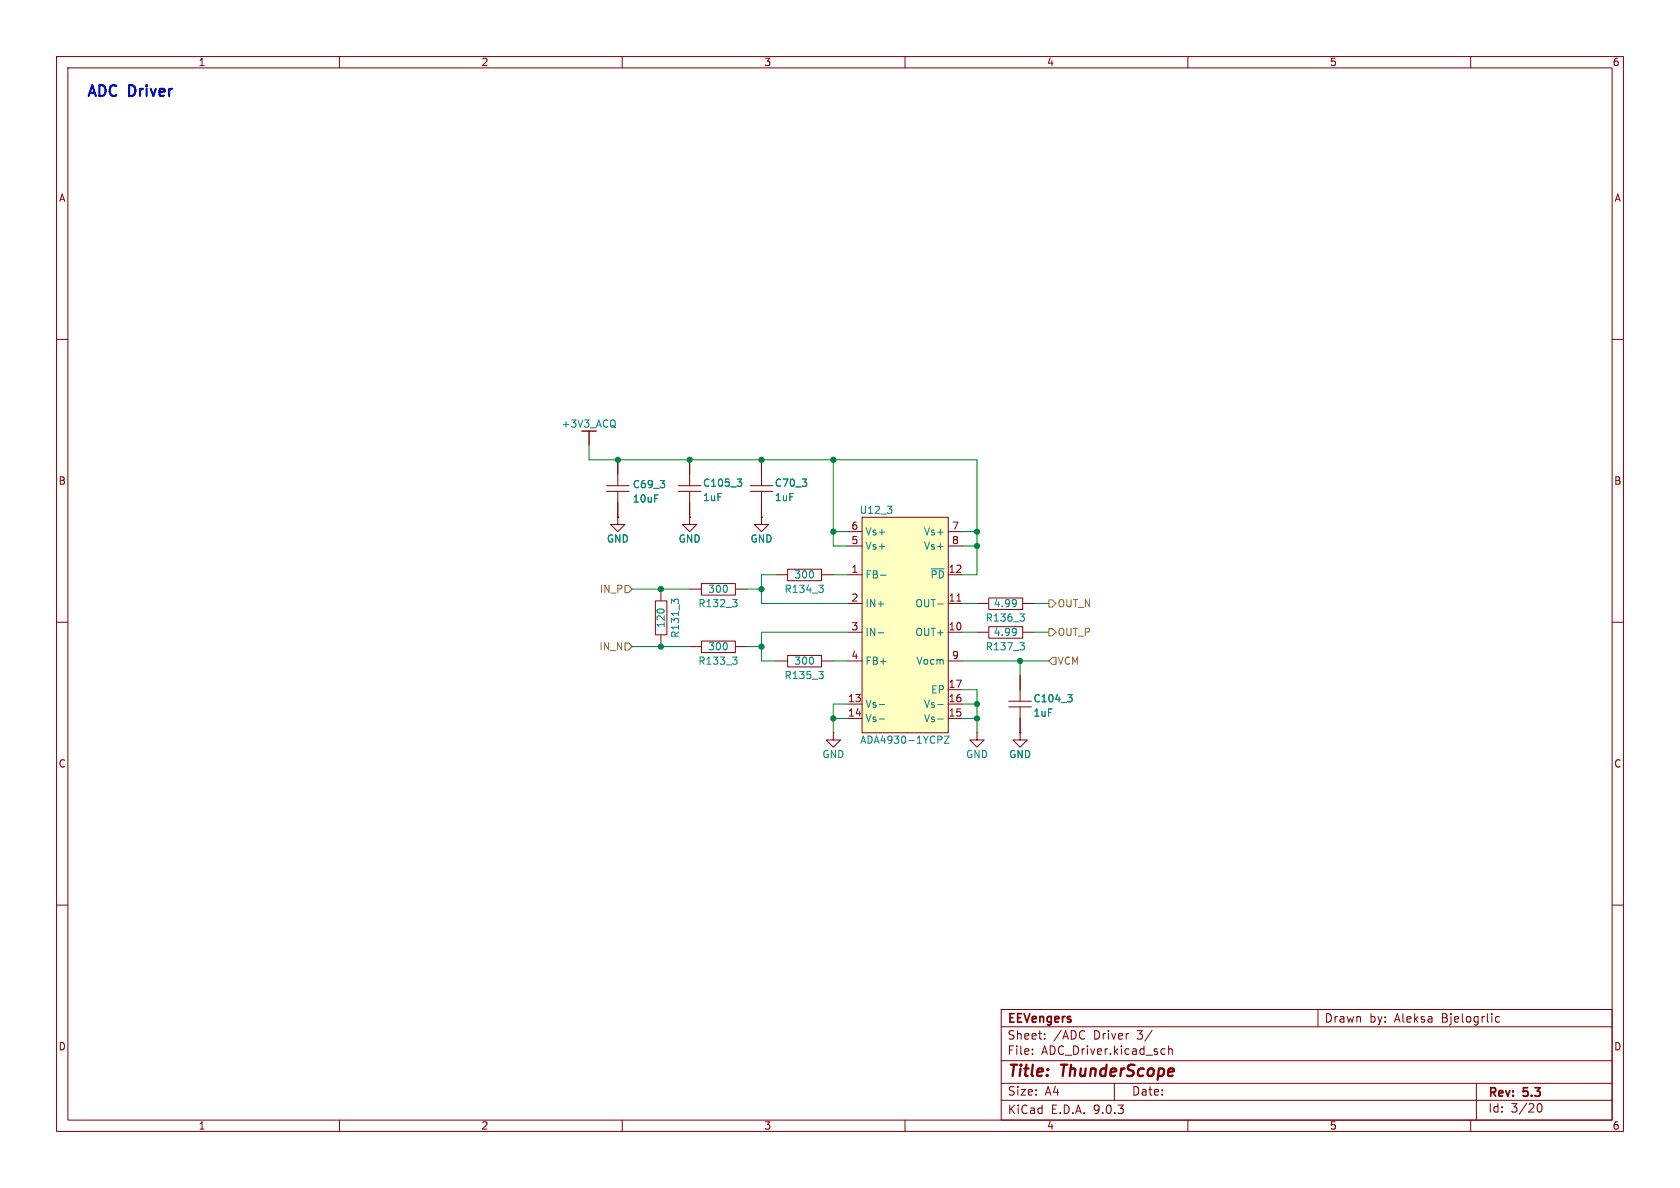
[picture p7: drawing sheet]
<svg xmlns="http://www.w3.org/2000/svg" width="297mm" height="210mm" viewBox="0 0 297 210" stroke-linecap="round" stroke-linejoin="round" font-family="sans-serif">
<defs><g id="words">
<g font-size="2.8" fill="#840000">
<text x="178" y="190.9">Title:</text>
<text x="187.7" y="190.9">ThunderScope</text>
</g>
<g font-size="2.7" fill="#0000c2">
<text x="15.2" y="18">ADC</text>
<text x="22.9" y="18">Driver</text>
</g>
<g font-size="2.1" fill="#840000">
<text x="178" y="184">Sheet:</text>
<text x="178" y="181.2">EEVengers</text>
<text x="186.2" y="184">/ADC</text>
<text x="193.4" y="184">Driver</text>
<text x="201.2" y="184">3/</text>
<text x="234.1" y="181">Drawn</text>
<text x="242.1" y="181">by:</text>
<text x="246.6" y="181">Aleksa</text>
<text x="255" y="181">Bjelogrlic</text>
<text x="178" y="186.7">File:</text>
<text x="184.1" y="186.7">ADC_Driver.kicad_sch</text>
<text x="178.1" y="197.1">KiCad</text>
<text x="178.1" y="193.9">Size:</text>
<text x="184.7" y="193.9">A4</text>
<text x="185.8" y="197.1">E.D.A.</text>
<text x="193.4" y="197.1">9.0.3</text>
<text x="200" y="193.9">Date:</text>
<text x="263" y="194.3">Rev:</text>
<text x="263" y="196.9">Id:</text>
<text x="267.1" y="196.9">3/20</text>
<text x="269.4" y="194.3">5.3</text>
</g>
<g font-size="1.8" fill="#840000">
<text x="35" y="11.9">1</text>
<text x="85" y="11.9">2</text>
<text x="135" y="11.9">3</text>
<text x="185" y="11.9">4</text>
<text x="235" y="11.9">5</text>
<text x="285" y="11.9">6</text>
<text x="10.3" y="35.9">A</text>
<text x="285.3" y="35.9">A</text>
<text x="10.3" y="85.9">B</text>
<text x="285.3" y="85.9">B</text>
<text x="150.4" y="93.7">6</text>
<text x="168.2" y="93.7">7</text>
<text x="150.4" y="96.3">5</text>
<text x="150.4" y="101.3">1</text>
<text x="167.6" y="101.3">12</text>
<text x="168.2" y="96.3">8</text>
<text x="150.4" y="106.4">2</text>
<text x="167.6" y="106.4">11</text>
<text x="150.4" y="111.5">3</text>
<text x="167.6" y="111.5">10</text>
<text x="150.4" y="116.6">4</text>
<text x="168.2" y="116.6">9</text>
<text x="149.8" y="124.2">13</text>
<text x="167.6" y="121.7">17</text>
<text x="167.6" y="124.2">16</text>
<text x="149.8" y="126.7">14</text>
<text x="167.6" y="126.7">15</text>
<text x="10.3" y="135.9">C</text>
<text x="285.3" y="135.9">C</text>
<text x="10.3" y="185.9">D</text>
<text x="285.3" y="185.9">D</text>
<text x="35" y="199.9">1</text>
<text x="85" y="199.9">2</text>
<text x="135" y="199.9">3</text>
<text x="185" y="199.9">4</text>
<text x="235" y="199.9">5</text>
<text x="285" y="199.9">6</text>
</g>
<g font-size="1.8" fill="#008484">
<text x="99.2" y="75.8">+3V3_ACQ</text>
<text x="111.8" y="86.5">C69_3</text>
<text x="111.8" y="89">10uF</text>
<text x="124.2" y="88.8">1uF</text>
<text x="124.2" y="86.2">C105_3</text>
<text x="136.9" y="86.2">C70_3</text>
<text x="136.9" y="88.8">1uF</text>
<text x="151.9" y="91">U12_3</text>
<text x="152.9" y="94.8">Vs+</text>
<text x="163.2" y="94.8">Vs+</text>
<text x="107.2" y="96.1">GND</text>
<text x="119.9" y="96.1">GND</text>
<text x="132.6" y="96.1">GND</text>
<text x="152.9" y="97.4">Vs+</text>
<text x="163.2" y="97.4">Vs+</text>
<text x="123.4" y="107.5">R132_3</text>
<text x="125.1" y="105">300</text>
<text x="138.6" y="105">R134_3</text>
<text x="140.3" y="102.5">300</text>
<text x="152.9" y="102.5">FB-</text>
<text x="152.9" y="107.5">IN+</text>
<text x="161.7" y="107.5">OUT-</text>
<text x="164.4" y="102.5">~{PD}</text>
<text x="175.6" y="107.5">4.99</text>
<text x="117.7" y="111.1" transform="rotate(-90 117.7 111.1)">120</text>
<text x="120.2" y="112.9" transform="rotate(-90 120.2 112.9)">R131_3</text>
<text x="152.9" y="112.6">IN-</text>
<text x="161.7" y="112.6">OUT+</text>
<text x="174.2" y="110.1">R136_3</text>
<text x="175.6" y="112.6">4.99</text>
<text x="123.4" y="117.7">R133_3</text>
<text x="125.1" y="115.2">300</text>
<text x="140.3" y="117.7">300</text>
<text x="152.9" y="117.7">FB+</text>
<text x="161.9" y="117.7">Vocm</text>
<text x="174.2" y="115.2">R137_3</text>
<text x="138.6" y="120.2">R135_3</text>
<text x="152.9" y="125.3">Vs-</text>
<text x="163.2" y="125.3">Vs-</text>
<text x="164.5" y="122.8">EP</text>
<text x="182.6" y="124.3">C104_3</text>
<text x="152" y="131.7">ADA4930-1YCPZ</text>
<text x="152.9" y="127.9">Vs-</text>
<text x="163.2" y="127.9">Vs-</text>
<text x="182.6" y="126.9">1uF</text>
<text x="145.3" y="134.2">GND</text>
<text x="170.7" y="134.2">GND</text>
<text x="178.3" y="134.2">GND</text>
</g>
<g font-size="1.8" fill="#848400">
<text x="105.9" y="105">IN_P</text>
<text x="186.9" y="107.5">OUT_N</text>
<text x="186.9" y="112.6">OUT_P</text>
<text x="105.9" y="115.2">IN_N</text>
<text x="186.9" y="117.7">VCM</text>
</g>
</g></defs>
<path d="M0 0h297v210h-297z" fill="#fff" stroke="#fff" stroke-width=".18"/>
<g fill="none" stroke="#840000" stroke-width=".18">
<path d="M10 10h277v190h-277zM12 12h273v186h-273zM60 10v2M110 10v2M160 10v2M210 10v2M260 10v2M10 60h2M285 60h2M107.2 85.9h4M107.2 86.9h4M109.2 91.4v1.3h1.3l-1.3 1.3-1.3-1.3h1.3"/>
<path d="M109.2 91.4h.1M109.2 81.3v4.6M109.2 86.9v4.5M119.9 85.9h4M119.9 86.9h4M121.9 91.4v1.3h1.3l-1.3 1.3-1.3-1.3h1.3M121.9 91.4h.1M121.9 81.3v4.6M121.9 86.9v4.5M132.6 85.9h4M132.6 86.9h4M134.6 81.3v4.6"/>
<path d="M134.6 86.9v4.5M10 110h2M115.9 106.2h2v6h-2zM116.8 104.1v2M116.8 112.3v2M121.9 114.3h2M124 113.3h6v2.1h-6zM130.1 114.3h2M137.2 101.6h2M137.2 116.8h2M139.2 100.6h6v2.1h-6zM139.2 115.9h6v2h-6z"/>
<path d="M145.3 101.6h2M145.3 116.8h2M172.7 111.8h2M172.7 106.7h2M174.8 110.8h6v2h-6zM174.8 105.7h6v2h-6zM180.3 119.4v4.6M180.9 111.8h2M180.9 106.7h2M285 110h2M172.7 129.5v1.3h1.3l-1.3 1.3-1.3-1.3h1.3M172.7 129.5h.1"/>
<path d="M178.3 124h4M178.3 125h4M180.3 129.5v1.3h1.3l-1.3 1.3-1.2-1.3h1.2M180.3 129.5h.1M180.3 125v4.5M10 160h2M177 178.5h108v19.5h-108zM233 178.5v3M265.1 179.8l-.4-.1-.3 .3v.4l.1 .2h.6M285 160h2M60 198v2M110 198v2"/>
<path d="M160 198v2M177 194.5h108M177 191.5h108M177 187.5h108M177 181.5h108M182.5 186.3v.1M182.5 185.5v.1M184.7 183.6v.1M184.7 182.8v.1M197 191.5v3M205.5 185.4l.5 .1M206 186.3l-.5 .1"/>
<path d="M206.6 185.5l.2-.1 .4 .1v.9M206.6 184.9v1.5M210 198v2M260 198v2M261 191.5v6.5M271.7 195.7l.2-.5 .2-.1a.81 .81 0 0 1 .6 .6 .81 .81 0 0 1-.3 .8h-.4l-.3-.5"/>
</g>
<g fill="none" stroke="#008484" stroke-width=".18">
<path d="M108.7 75.6h.1M108.7 74.4v.9M130.3 84.7h.8l-.4 .5M130.9 85.2l.2 .2v.3l-.2 .3M119.2 106.3l-.5-.4v.8M119.2 106.2l.2-.3h.3l.3 .3M129.5 116.1h.8l-.4 .5M130.1 116.6l.2 .3v.3l-.2 .2M144.7 103.4h.8l-.4 .5M144.7 118.7h.8l-.4 .5M145.3 103.9l.2 .3v.3l-.2 .2M145.3 119.2l.2 .2v.3l-.2 .3"/>
<path d="M179.6 111.1v.1a1.07 1.07 0 0 1-.1 1M179.6 106.1a1.07 1.07 0 0 1-.1 1M179.7 111.6l-.1 .2M179.7 106.5l-.1 .2M180.3 113.6h.8l-.4 .5M180.3 108.5h.8l-.4 .5M180.9 114.1l.2 .2v.3l-.2 .3M180.9 109l.2 .3v.3l-.2 .2M188.8 122.8h.7l-.4 .5M189.3 123.3l.2 .2v.3l-.2 .3"/>
</g>
<path d="M104.1 76.2v2.5" fill="none" stroke="#840000" stroke-width=".25"/>
<path d="M152.4 91.4h15.2v38.1h-15.2z" fill="#ffffc2"/>
<g fill="none" stroke="#840000" stroke-width=".18">
<path d="M109.2 91.4h.1M109.2 81.3v2.5M109.2 88.9v2.5M121.9 91.4h.1M121.9 81.3v2.5M121.9 88.9v2.5M134.6 91.4v1.3h1.3l-1.3 1.3-1.3-1.3h1.3M134.6 91.4h.1M134.6 81.3v2.5M134.6 88.9v2.5M149.9 94h2.5M149.9 96.5h2.5"/>
<path d="M152.4 91.4h15.2v38.1h-15.2zM167.6 94h2.6M167.6 96.5h2.6M121.9 104.1h2M124 103.2h6v2h-6zM130.1 104.1h2M149.9 101.6h2.5M149.9 106.7h2.5M149.9 111.8h2.5M149.9 116.8h2.5M167.6 101.6h2.6M167.6 106.7h2.6"/>
<path d="M167.6 111.8h2.6M167.6 116.8h2.6M169.2 106.3h.7M180.3 119.4v2.5M147.3 129.5v1.3h1.3l-1.3 1.3-1.3-1.3h1.3M147.3 129.5h.1M149.9 124.5h2.5M149.9 127h2.5M167.6 124.5h2.6M167.6 127h2.6M167.6 121.9h2.6M180.3 129.5h.1"/>
<path d="M180.3 127v2.5"/>
</g>
<g fill="none" stroke="#008484" stroke-width=".18">
<path d="M130.3 84.7h.8l-.4 .5M130.9 85.2l.2 .2v.3l-.2 .3M156.9 89.5h.8l-.5 .5M157.6 90.1v.5M129.5 106h.8l-.4 .5M130.1 106.5l.2 .2v.3l-.2 .3M155.2 111.9h1M155.7 101.7h.9M164.6 100.6h2.3M165.8 106.8h.9M155.4 124.6h1M155.4 127.1h1"/>
<path d="M165.8 124.6h.9M165.8 127.1h.9M166.4 130.2l.1 .2-.1 .3M166.9 130.1h.9l-.9 1.3h.9M188.8 122.8h.7l-.4 .5M189.3 123.3l.2 .2v.3l-.2 .3"/>
</g>
<path d="M110.5 113.7h.6l.7 .6-.7 .6h-.6zM110.5 103.5h.6l.7 .6-.7 .7h-.6zM185.4 111.1h.7l.6 .7-.6 .6h-.7zM185.4 106h.7l.6 .7-.6 .6h-.7zM186.1 116.2h.6v1.3h-.6l-.7-.7z" fill="none" stroke="#848400" stroke-width=".18"/>
<g fill="none" stroke="#008400" stroke-width=".18">
<path d="M104.1 78.7v2.6h68.6v20.3h-2.5M147.3 81.3v15.2h2.6M147.3 94h2.6M170.2 96.5h2.5M170.2 94h2.5M111.8 114.3h10.1M111.8 104.1h10.1M132.1 114.3h2.5M132.1 104.1h2.5M137.2 101.6h-2.6v5.1h15.3M147.3 101.6h2.6M147.3 116.8h2.6"/>
<path d="M149.9 111.8h-15.3v5h2.6M170.2 106.7h2.5M170.2 116.8h15.2M170.2 111.8h2.5M180.3 116.8v2.6M182.9 106.7h2.5M182.9 111.8h2.5M147.3 127h2.6M149.9 124.5h-2.6v5M170.2 121.9h2.5v7.6M170.2 127h2.5M170.2 124.5h2.5"/>
</g>
<path d="M15.7 17l.6-1.9 .6 1.9M18.5 15.3l-.5-.2h-.4v1.9M20.6 15.2a.66 .66 0 0 0-1 .1M23.7 15.3l-.4-.2h-.5v1.9M25.9 15.1l-.1 .1h.1M25.9 15.1l.1 .1h-.1M25.9 15.1v.1" fill="none" stroke="#0000c2" stroke-width=".38"/>
<g fill="#008400" stroke="#008400" stroke-width=".18">
<circle cx="109.2" cy="81.3" r=".46"/>
<circle cx="147.3" cy="81.3" r=".46"/>
<circle cx="134.6" cy="81.3" r=".46"/>
<circle cx="147.3" cy="94" r=".46"/>
<circle cx="134.6" cy="104.1" r=".46"/>
<circle cx="116.8" cy="114.3" r=".46"/>
<circle cx="121.9" cy="81.3" r=".46"/>
<circle cx="116.8" cy="104.1" r=".46"/>
<circle cx="172.7" cy="96.5" r=".46"/>
<circle cx="172.7" cy="127" r=".46"/>
<circle cx="172.7" cy="124.5" r=".46"/>
<circle cx="180.3" cy="116.8" r=".46"/>
<circle cx="172.7" cy="94" r=".46"/>
<circle cx="147.3" cy="127" r=".46"/>
<circle cx="134.6" cy="114.3" r=".46"/>
</g>
<use href="#words"/>
</svg>
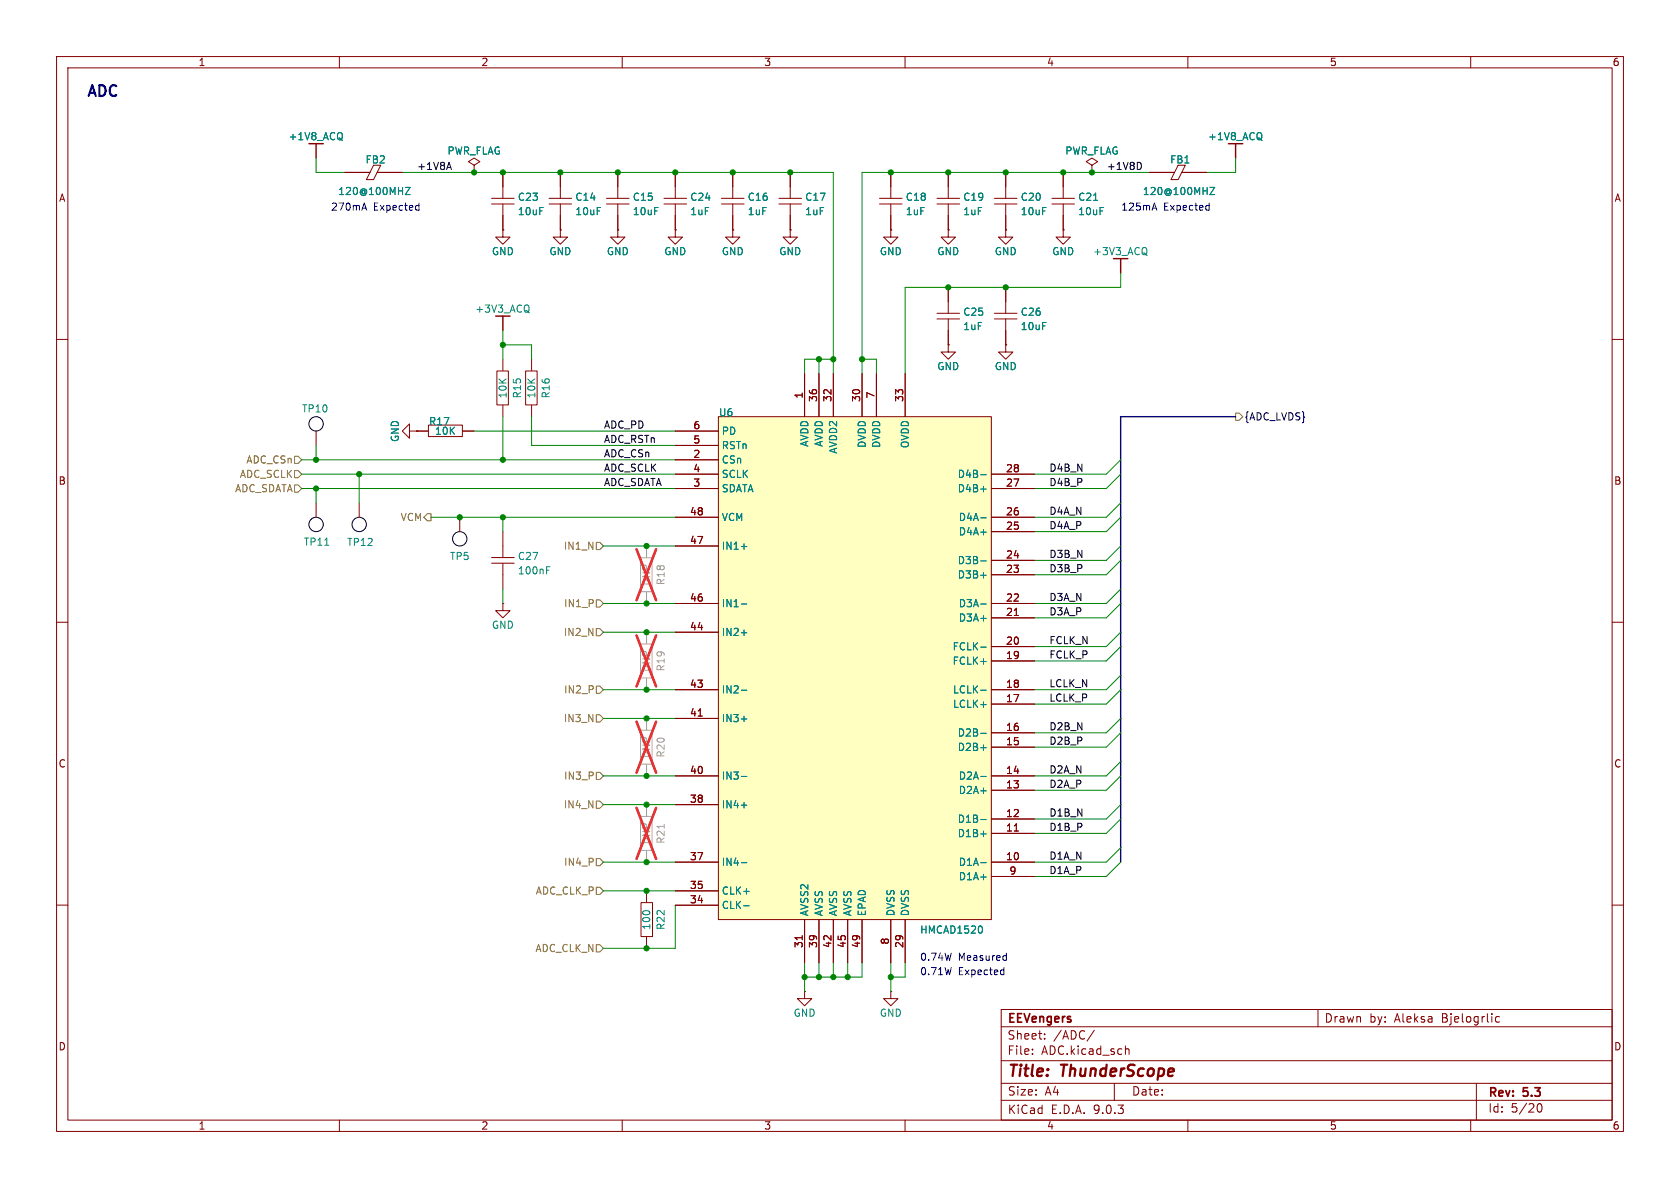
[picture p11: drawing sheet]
<svg xmlns="http://www.w3.org/2000/svg" width="297mm" height="210mm" viewBox="0 0 297 210" stroke-linecap="round" stroke-linejoin="round" font-family="sans-serif">
<defs><g id="words">
<g font-size="2.8" fill="#840000">
<text x="178" y="190.9">Title:</text>
<text x="187.7" y="190.9">ThunderScope</text>
</g>
<text font-size="2.7" fill="#0000c2" x="15.2" y="18">ADC</text>
<g font-size="2.1" fill="#840000">
<text x="178" y="184">Sheet:</text>
<text x="178" y="181.2">EEVengers</text>
<text x="186.2" y="184">/ADC/</text>
<text x="234.1" y="181">Drawn</text>
<text x="242.1" y="181">by:</text>
<text x="246.6" y="181">Aleksa</text>
<text x="255" y="181">Bjelogrlic</text>
<text x="178" y="186.7">File:</text>
<text x="184.1" y="186.7">ADC.kicad_sch</text>
<text x="178.1" y="197.1">KiCad</text>
<text x="178.1" y="193.9">Size:</text>
<text x="184.7" y="193.9">A4</text>
<text x="185.8" y="197.1">E.D.A.</text>
<text x="193.4" y="197.1">9.0.3</text>
<text x="200" y="193.9">Date:</text>
<text x="263" y="194.3">Rev:</text>
<text x="263" y="196.9">Id:</text>
<text x="267.1" y="196.9">5/20</text>
<text x="269.4" y="194.3">5.3</text>
</g>
<g font-size="1.8" fill="#840000">
<text x="35" y="11.9">1</text>
<text x="85" y="11.9">2</text>
<text x="135" y="11.9">3</text>
<text x="185" y="11.9">4</text>
<text x="235" y="11.9">5</text>
<text x="285" y="11.9">6</text>
<text x="10.3" y="35.9">A</text>
<text x="285.3" y="35.9">A</text>
<text x="142" y="70.6" transform="rotate(-90 142 70.6)">1</text>
<text x="144.5" y="71.2" transform="rotate(-90 144.5 71.2)">36</text>
<text x="147.1" y="71.2" transform="rotate(-90 147.1 71.2)">32</text>
<text x="152.1" y="71.2" transform="rotate(-90 152.1 71.2)">30</text>
<text x="154.7" y="70.6" transform="rotate(-90 154.7 70.6)">7</text>
<text x="159.8" y="71.2" transform="rotate(-90 159.8 71.2)">33</text>
<text x="122.5" y="75.9">6</text>
<text x="122.5" y="78.5">5</text>
<text x="122.5" y="81">2</text>
<text x="122.5" y="83.6">4</text>
<text x="177.8" y="83.6">28</text>
<text x="10.3" y="85.9">B</text>
<text x="122.5" y="86.1">3</text>
<text x="177.8" y="86.1">27</text>
<text x="285.3" y="85.9">B</text>
<text x="121.9" y="91.2">48</text>
<text x="177.8" y="91.2">26</text>
<text x="177.8" y="93.7">25</text>
<text x="121.9" y="96.3">47</text>
<text x="177.8" y="98.8">24</text>
<text x="177.8" y="101.3">23</text>
<text x="121.9" y="106.4">46</text>
<text x="177.8" y="106.4">22</text>
<text x="121.9" y="111.5">44</text>
<text x="177.8" y="109">21</text>
<text x="177.8" y="114">20</text>
<text x="177.8" y="116.6">19</text>
<text x="121.9" y="121.7">43</text>
<text x="177.8" y="121.7">18</text>
<text x="177.8" y="124.2">17</text>
<text x="121.9" y="126.7">41</text>
<text x="177.8" y="129.3">16</text>
<text x="177.8" y="131.8">15</text>
<text x="10.3" y="135.9">C</text>
<text x="121.9" y="136.9">40</text>
<text x="177.8" y="136.9">14</text>
<text x="285.3" y="135.9">C</text>
<text x="121.9" y="142">38</text>
<text x="177.8" y="139.4">13</text>
<text x="177.8" y="144.5">12</text>
<text x="177.8" y="147.1">11</text>
<text x="121.9" y="152.1">37</text>
<text x="177.8" y="152.1">10</text>
<text x="178.4" y="154.7">9</text>
<text x="121.9" y="157.2">35</text>
<text x="121.9" y="159.8">34</text>
<text x="142" y="167.7" transform="rotate(-90 142 167.7)">31</text>
<text x="144.5" y="167.7" transform="rotate(-90 144.5 167.7)">39</text>
<text x="147.1" y="167.7" transform="rotate(-90 147.1 167.7)">42</text>
<text x="149.6" y="167.7" transform="rotate(-90 149.6 167.7)">45</text>
<text x="152.1" y="167.7" transform="rotate(-90 152.1 167.7)">49</text>
<text x="157.2" y="167.1" transform="rotate(-90 157.2 167.1)">8</text>
<text x="159.8" y="167.7" transform="rotate(-90 159.8 167.7)">29</text>
<text x="10.3" y="185.9">D</text>
<text x="285.3" y="185.9">D</text>
<text x="35" y="199.9">1</text>
<text x="85" y="199.9">2</text>
<text x="135" y="199.9">3</text>
<text x="185" y="199.9">4</text>
<text x="235" y="199.9">5</text>
<text x="285" y="199.9">6</text>
</g>
<g font-size="1.8" fill="#008484">
<text x="50.9" y="25">+1V8_ACQ</text>
<text x="64.5" y="29.1">FB2</text>
<text x="79" y="27.5">PWR_FLAG</text>
<text x="188.2" y="27.5">PWR_FLAG</text>
<text x="206.8" y="29.1">FB1</text>
<text x="213.5" y="25">+1V8_ACQ</text>
<text x="59.7" y="34.7">120@100MHZ</text>
<text x="91.4" y="35.7">C23</text>
<text x="101.6" y="35.7">C14</text>
<text x="111.8" y="35.7">C15</text>
<text x="121.9" y="35.7">C24</text>
<text x="132.1" y="35.7">C16</text>
<text x="142.2" y="35.7">C17</text>
<text x="160" y="35.7">C18</text>
<text x="170.2" y="35.7">C19</text>
<text x="180.3" y="35.7">C20</text>
<text x="190.5" y="35.7">C21</text>
<text x="201.9" y="34.7">120@100MHZ</text>
<text x="91.4" y="38.2">10uF</text>
<text x="101.6" y="38.2">10uF</text>
<text x="111.8" y="38.2">10uF</text>
<text x="121.9" y="38.2">1uF</text>
<text x="132.1" y="38.2">1uF</text>
<text x="142.2" y="38.2">1uF</text>
<text x="160" y="38.2">1uF</text>
<text x="170.2" y="38.2">1uF</text>
<text x="180.3" y="38.2">10uF</text>
<text x="190.5" y="38.2">10uF</text>
<text x="86.9" y="45.3">GND</text>
<text x="97" y="45.3">GND</text>
<text x="107.2" y="45.3">GND</text>
<text x="117.3" y="45.3">GND</text>
<text x="127.5" y="45.3">GND</text>
<text x="137.7" y="45.3">GND</text>
<text x="155.4" y="45.3">GND</text>
<text x="165.6" y="45.3">GND</text>
<text x="175.8" y="45.3">GND</text>
<text x="185.9" y="45.3">GND</text>
<text x="193.1" y="45.3">+3V3_ACQ</text>
<text x="83.9" y="55.5">+3V3_ACQ</text>
<text x="170.2" y="58.6">1uF</text>
<text x="170.2" y="56">C25</text>
<text x="180.3" y="56">C26</text>
<text x="180.3" y="58.6">10uF</text>
<text x="165.6" y="65.6">GND</text>
<text x="175.8" y="65.6">GND</text>
<text x="89.8" y="70.5" transform="rotate(-90 89.8 70.5)">10K</text>
<text x="92.3" y="70.5" transform="rotate(-90 92.3 70.5)">R15</text>
<text x="94.8" y="70.5" transform="rotate(-90 94.8 70.5)">10K</text>
<text x="97.4" y="70.5" transform="rotate(-90 97.4 70.5)">R16</text>
<text x="53.3" y="73.1">TP10</text>
<text x="75.7" y="75.4">R17</text>
<text x="76.8" y="77.1">10K</text>
<text x="127" y="73.8">U6</text>
<text x="127.5" y="77.1">PD</text>
<text x="70.7" y="78.2" transform="rotate(-90 70.7 78.2)">GND</text>
<text x="127.5" y="79.6">RSTn</text>
<text x="127.5" y="82.1">CSn</text>
<text x="143.1" y="79.1" transform="rotate(-90 143.1 79.1)">AVDD</text>
<text x="145.6" y="79.1" transform="rotate(-90 145.6 79.1)">AVDD</text>
<text x="148.2" y="80.3" transform="rotate(-90 148.2 80.3)">AVDD2</text>
<text x="153.3" y="79.3" transform="rotate(-90 153.3 79.3)">DVDD</text>
<text x="155.8" y="79.3" transform="rotate(-90 155.8 79.3)">DVDD</text>
<text x="160.9" y="79.3" transform="rotate(-90 160.9 79.3)">OVDD</text>
<text x="127.5" y="84.7">SCLK</text>
<text x="127.5" y="87.2">SDATA</text>
<text x="169.2" y="84.7">D4B-</text>
<text x="169.2" y="87.2">D4B+</text>
<text x="127.5" y="92.3">VCM</text>
<text x="169.4" y="92.3">D4A-</text>
<text x="169.4" y="94.8">D4A+</text>
<text x="53.6" y="96.7">TP11</text>
<text x="61.3" y="96.7">TP12</text>
<text x="79.5" y="99.2">TP5</text>
<text x="91.4" y="101.7">100nF</text>
<text x="91.4" y="99.2">C27</text>
<text x="127.5" y="97.4">IN1+</text>
<text x="169.2" y="99.9">D3B-</text>
<text x="127.5" y="107.5">IN1-</text>
<text x="169.2" y="102.5">D3B+</text>
<text x="169.4" y="107.5">D3A-</text>
<text x="86.9" y="111.4">GND</text>
<text x="127.5" y="112.6">IN2+</text>
<text x="169.4" y="110.1">D3A+</text>
<text x="168.3" y="115.2">FCLK-</text>
<text x="168.3" y="117.7">FCLK+</text>
<text x="127.5" y="122.8">IN2-</text>
<text x="168.4" y="122.8">LCLK-</text>
<text x="168.4" y="125.3">LCLK+</text>
<text x="127.5" y="127.9">IN3+</text>
<text x="169.2" y="130.4">D2B-</text>
<text x="169.2" y="132.9">D2B+</text>
<text x="127.5" y="138">IN3-</text>
<text x="127.5" y="143.1">IN4+</text>
<text x="169.4" y="138">D2A-</text>
<text x="169.4" y="140.6">D2A+</text>
<text x="169.2" y="145.6">D1B-</text>
<text x="169.2" y="148.2">D1B+</text>
<text x="127.5" y="153.3">IN4-</text>
<text x="169.4" y="153.3">D1A-</text>
<text x="169.4" y="155.8">D1A+</text>
<text x="127.5" y="158.3">CLK+</text>
<text x="127.5" y="160.9">CLK-</text>
<text x="115.2" y="164.5" transform="rotate(-90 115.2 164.5)">100</text>
<text x="117.7" y="164.5" transform="rotate(-90 117.7 164.5)">R22</text>
<text x="143.1" y="162.1" transform="rotate(-90 143.1 162.1)">AVSS2</text>
<text x="145.6" y="162.1" transform="rotate(-90 145.6 162.1)">AVSS</text>
<text x="148.2" y="162.1" transform="rotate(-90 148.2 162.1)">AVSS</text>
<text x="150.7" y="162.1" transform="rotate(-90 150.7 162.1)">AVSS</text>
<text x="153.3" y="162.1" transform="rotate(-90 153.3 162.1)">EPAD</text>
<text x="158.3" y="162.1" transform="rotate(-90 158.3 162.1)">DVSS</text>
<text x="160.9" y="162.1" transform="rotate(-90 160.9 162.1)">DVSS</text>
<text x="162.6" y="165.2">HMCAD1520</text>
<text x="140.2" y="179.9">GND</text>
<text x="155.4" y="179.9">GND</text>
</g>
<g font-size="1.8">
<text x="73.7" y="30.1">+1V8A</text>
<text x="195.6" y="30.1">+1V8D</text>
<text x="106.7" y="75.9">ADC_PD</text>
<text x="106.7" y="80.9">ADC_CSn</text>
<text x="106.7" y="83.5">ADC_SCLK</text>
<text x="106.7" y="78.4">ADC_RSTn</text>
<text x="185.4" y="83.5">D4B_N</text>
<text x="106.7" y="86">ADC_SDATA</text>
<text x="185.4" y="86">D4B_P</text>
<text x="185.4" y="93.6">D4A_P</text>
<text x="185.4" y="91.1">D4A_N</text>
<text x="185.4" y="98.7">D3B_N</text>
<text x="185.4" y="101.3">D3B_P</text>
<text x="185.4" y="106.3">D3A_N</text>
<text x="185.4" y="114">FCLK_N</text>
<text x="185.4" y="108.9">D3A_P</text>
<text x="185.4" y="116.5">FCLK_P</text>
<text x="185.4" y="124.1">LCLK_P</text>
<text x="185.4" y="121.6">LCLK_N</text>
<text x="185.4" y="129.2">D2B_N</text>
<text x="185.4" y="131.7">D2B_P</text>
<text x="185.4" y="136.8">D2A_N</text>
<text x="185.4" y="139.4">D2A_P</text>
<text x="185.4" y="147">D1B_P</text>
<text x="185.4" y="144.4">D1B_N</text>
<text x="185.4" y="154.6">D1A_P</text>
<text x="185.4" y="152.1">D1A_N</text>
</g>
<g font-size="1.8" fill="#0000c2">
<text x="58.4" y="37.5">270mA</text>
<text x="66" y="37.5">Expected</text>
<text x="198.1" y="37.5">125mA</text>
<text x="205.7" y="37.5">Expected</text>
<text x="162.6" y="169.9">0.74W</text>
<text x="162.6" y="172.5">0.71W</text>
<text x="169.4" y="169.9">Measured</text>
<text x="169.4" y="172.5">Expected</text>
</g>
<text font-size="1.8" fill="#000084" x="219.9" y="74.5">{ADC_LVDS}</text>
<g font-size="1.8" fill="#848400">
<text x="43.5" y="82.1">ADC_CSn</text>
<text x="41.5" y="87.2">ADC_SDATA</text>
<text x="42.3" y="84.7">ADC_SCLK</text>
<text x="70.7" y="92.3">VCM</text>
<text x="99.6" y="97.4">IN1_N</text>
<text x="99.6" y="107.5">IN1_P</text>
<text x="99.6" y="112.6">IN2_N</text>
<text x="99.6" y="122.8">IN2_P</text>
<text x="99.6" y="127.9">IN3_N</text>
<text x="99.6" y="143.1">IN4_N</text>
<text x="99.6" y="138">IN3_P</text>
<text x="99.6" y="153.3">IN4_P</text>
<text x="94.6" y="158.3">ADC_CLK_P</text>
<text x="94.6" y="168.5">ADC_CLK_N</text>
</g>
<g font-size="1.8" fill="#a1a1a1">
<text x="115.2" y="103.6" transform="rotate(-90 115.2 103.6)">DNP</text>
<text x="117.7" y="103.5" transform="rotate(-90 117.7 103.5)">R18</text>
<text x="115.2" y="118.9" transform="rotate(-90 115.2 118.9)">DNP</text>
<text x="117.7" y="118.8" transform="rotate(-90 117.7 118.8)">R19</text>
<text x="115.2" y="134.1" transform="rotate(-90 115.2 134.1)">DNP</text>
<text x="117.7" y="134" transform="rotate(-90 117.7 134)">R20</text>
<text x="115.2" y="149.4" transform="rotate(-90 115.2 149.4)">DNP</text>
<text x="117.7" y="149.3" transform="rotate(-90 117.7 149.3)">R21</text>
</g>
</g></defs>
<path d="M0 0h297v210h-297z" fill="#fff" stroke="#fff" stroke-width=".18"/>
<g fill="none" stroke="#840000" stroke-width=".18">
<path d="M10 10h277v190h-277zM12 12h273v186h-273zM60 10v2M110 10v2M160 10v2M210 10v2M260 10v2M61 30.5h4.4M66 29.2h1.3l-1.3 2.6h-1.2zM66.7 30.5h4.4M83.8 29.2l1-.6-1-.7-1 .7 1 .6v1.3M83.8 30.5h.1"/>
<path d="M86.9 35.1h4M86.9 36.1h4M88.9 30.5v4.6M88.9 36.1v4.5M107.2 35.1h4M107.2 36.1h4M109.2 30.5v4.6M109.2 36.1v4.5M155.5 35.1h4M155.5 36.1h4M157.5 30.5v4.6M157.5 36.1v4.5"/>
<path d="M165.6 35.1h4M165.6 36.1h4M167.6 30.5v4.6M167.6 36.1v4.5M99.1 40.6v1.3h1.2l-1.2 1.3-1.3-1.3h1.3M99.1 40.6h.1M109.2 40.6v1.3h1.3l-1.3 1.3-1.3-1.3h1.3M109.2 40.6h.1M157.5 40.6v1.3h1.2l-1.2 1.3-1.3-1.3h1.3M157.5 40.6h.1M165.6 55.4h4M165.6 56.4h4"/>
<path d="M167.6 40.6v1.3h1.3l-1.3 1.3-1.2-1.3h1.2M167.6 40.6h.1M167.6 50.8v4.6M167.6 56.4v4.6M175.8 55.4h4M175.8 56.4h4M177.8 50.8v4.6M177.8 56.4v4.6M10 60h2M72.4 76.2v-1.3l-1.3 1.3 1.3 1.3v-1.3h1.3M73.7 76.2h.1M73.7 76.2h2"/>
<path d="M75.7 75.1h6v2.1h-6zM81.8 76.2h2M87.8 65.6h2.1v6h-2.1zM88.9 63.5v2M88.9 71.7v2M92.9 65.6h2.1v6h-2.1zM94 63.5v2M94 71.7v2M177.8 61v1.2h1.3l-1.3 1.3-1.3-1.3h1.3M177.8 61h.1M285 60h2M10 110h2"/>
<path d="M285 110h2M10 160h2M142.2 175.3v1.2h1.3l-1.3 1.3-1.2-1.3h1.2M142.2 175.3h.1M177 178.5h108v19.5h-108zM233 178.5v3M265.1 179.8l-.4-.1-.3 .3v.4l.1 .2h.6M285 160h2M60 198v2M110 198v2M160 198v2M177 194.5h108"/>
<path d="M177 191.5h108M177 187.5h108M177 181.5h108M182.5 186.3v.1M182.5 185.5v.1M184.7 183.6v.1M184.7 182.8v.1M193.5 182.1l-1.3 2M197 191.5v3M199 185.5l.2-.1 .3 .1 .1 .9M210 198v2M260 198v2"/>
<path d="M261 191.5v6.5M271.7 195.7l.2-.5 .2-.1a.81 .81 0 0 1 .6 .6 .81 .81 0 0 1-.3 .8h-.4l-.3-.5"/>
</g>
<path d="M113.2 113.8h2.1v6h-2.1zM114.3 111.8v2M114.3 119.9v2" fill="none" stroke="#a1a1a1" stroke-width=".18"/>
<path d="M112.5 112.3l3.5 9M116 112.3l-3.5 9" fill="none" stroke="#ff2626" stroke-width=".46"/>
<path d="M60.4 24.8h.2M60.4 23.6v.9M71.7 33.1h.8l-.8 1.3h.8M93.5 55.2l.1 .1M93.5 54.1v.9" fill="none" stroke="#008484" stroke-width=".18"/>
<path d="M55.9 25.4v2.5M88.9 55.9v2.5" fill="none" stroke="#840000" stroke-width=".25"/>
<path d="M127 73.7h48.3v88.9h-48.3z" fill="#ffffc2"/>
<path d="M127 73.7h48.3v88.9h-48.3z" fill="none" stroke="#800000" stroke-width=".18"/>
<g fill="none" stroke="#840000" stroke-width=".18">
<path d="M61 30.5h4.4M66.7 30.5h4.4M83.8 30.5h.1M88.9 30.5v2.5M88.9 38.1v2.5M97.1 35.1h4M97.1 36.1h4M99.1 30.5v4.6M99.1 36.1v4.5M109.2 30.5v2.5M109.2 38.1v2.5M117.4 35.1h4"/>
<path d="M117.4 36.1h4M119.4 30.5v4.6M119.4 36.1v4.5M127.5 35.1h4M127.5 36.1h4M129.5 30.5v4.6M129.5 36.1v4.5M137.7 35.1h4M137.7 36.1h4M139.7 30.5v4.6M139.7 36.1v4.5M157.5 30.5v2.5"/>
<path d="M157.5 38.1v2.5M167.6 30.5v2.5M167.6 38.1v2.5M175.8 35.1h4M175.8 36.1h4M177.8 30.5v4.6M177.8 36.1v4.5M186 35.1h4M186 36.1h4M188 30.5v4.6M188 36.1v4.5M193 29.2l1.1-.6-1.1-.7-1 .7 1 .6v1.3"/>
<path d="M193 30.5h.1M203.2 30.5h4.4M208.3 29.2h1.2l-1.2 2.6h-1.3zM208.9 30.5h4.5M88.9 40.6v1.3h1.3l-1.3 1.3-1.3-1.3h1.3M88.9 40.6h.1M99.1 40.6h.1M109.2 40.6h.1M119.4 40.6v1.3h1.2l-1.2 1.3-1.3-1.3h1.3M119.4 40.6h.1M129.5 40.6v1.3h1.3l-1.3 1.3-1.2-1.3h1.2M129.5 40.6h.1"/>
<path d="M139.7 40.6v1.3h1.3l-1.3 1.3-1.3-1.3h1.3M139.7 40.6h.1M157.5 40.6h.1M167.6 40.6h.1M167.6 50.8v2.5M167.6 58.4v2.6M177.8 40.6v1.3h1.3l-1.3 1.3-1.3-1.3h1.3M177.8 40.6h.1M177.8 50.8v2.5M177.8 58.4v2.6M188 40.6v1.3h1.2l-1.2 1.3-1.3-1.3h1.3M188 40.6h.1"/>
<path d="M55.9 76.2v2.5M73.7 76.2h.1M73.7 76.2h2M81.8 76.2h2M119.4 76.2h7.6M119.4 78.7h7.6M142.2 66v7.7M144.8 66v7.7M147.3 66v7.7M152.4 66v7.7M154.9 66v7.7M160 66v7.7"/>
<path d="M167.6 61v1.2h1.3l-1.3 1.3-1.2-1.3h1.2M167.6 61h.1M177.8 61h.1M55.9 88.9v2.5M63.5 88.9v2.5M81.3 91.4v2.6M86.9 98.6h4M86.9 99.6h4M88.9 94v4.6M88.9 99.6v4.5M119.4 81.3h7.6M119.4 83.8h7.6"/>
<path d="M119.4 86.4h7.6M119.4 91.4h7.6M119.4 96.5h7.6M175.3 83.8h7.6M175.3 86.4h7.6M175.3 91.4h7.6M175.3 94h7.6M175.3 99.1h7.6M88.9 106.7v1.3h1.3l-1.3 1.2-1.3-1.2h1.3M88.9 106.7h.1M119.4 106.7h7.6M119.4 111.8h7.6"/>
<path d="M175.3 106.7h7.6M175.3 101.6h7.6M175.3 109.2h7.6M175.3 114.3h7.6M175.3 116.8h7.6M179.3 108.8h.7M119.4 121.9h7.6M119.4 127h7.6M119.4 137.2h7.6M123.4 126.6h.8M175.3 121.9h7.6M175.3 137.2h7.6"/>
<path d="M175.3 124.5h7.6M175.3 129.5h7.6M175.3 132.1h7.6M175.3 139.7h7.6M113.3 159.6h2.1v6h-2.1zM114.3 157.5v2M119.4 142.2h7.6M119.4 152.4h7.6M119.4 157.5h7.6M175.3 152.4h7.6M175.3 144.8h7.6M175.3 147.3h7.6"/>
<path d="M175.3 154.9h7.6M179.3 146.9h.7M114.3 165.6v2M119.4 160h7.6M141.8 165.4v.7M142.2 162.6v7.6M144.8 162.6v7.6M147.3 162.6v7.6M149.9 162.6v7.6M152.4 162.6v7.6M157.5 175.3v1.2h1.2l-1.2 1.3-1.3-1.3h1.3M157.5 175.3h.1"/>
<path d="M157.5 162.6v7.6M160 162.6v7.6"/>
</g>
<g fill="none" stroke="#008484" stroke-width=".18">
<path d="M60.4 24.8h.2M60.4 23.6v.9M71.7 33.1h.8l-.8 1.3h.8M193.3 35.4h.8M213.9 33.1h.8l-.8 1.3h.8M223 24.8h.1M223 23.6v.9M202.7 45.1l.1 .1M202.7 43.9v.9M57.4 96.4h.7M131.1 96.6h.9M173.4 83.9h.9"/>
<path d="M173.4 86.5h.9M173.4 91.5h.9M173.4 99.2h.9M96.6 100.8h.5M96.6 100.2h.6M131.1 106.8h.9M131.1 111.9h.9M173.4 106.8h.9M173.4 101.7h.9M173.4 114.4h.9M131.1 122h.9M131.1 127.1h.9"/>
<path d="M131.1 137.3h.9M173.4 122h.9M173.4 137.3h.9M173.4 129.6h.9M173.4 132.2h.9M131.1 142.3h.9M131.1 152.5h.9M173.4 152.5h.9M173.4 144.9h.9M173.4 147.4h.9M131.5 160.1h.9M173.5 163.7l.2 .5-.2 .7"/>
</g>
<g fill="none" stroke="#000" stroke-width=".18">
<path d="M79.1 29.6h.6M79.4 28.7l.4 1.3M201.5 28.8l.3 .4-.3 .7"/>
<circle cx="55.9" cy="74.9" r="1.27"/>
<circle cx="55.9" cy="92.7" r="1.27"/>
<circle cx="63.5" cy="92.7" r="1.27"/>
<circle cx="81.3" cy="95.2" r="1.27"/>
</g>
<path d="M113.2 98.6h2.1v6h-2.1zM114.3 96.5v2M114.3 104.7v2M113.2 129.1h2.1v6h-2.1zM114.3 127v2M114.3 135.2v2M113.2 144.3h2.1v6h-2.1zM114.3 142.2v2M114.3 150.4v2M117.4 145.7v.7" fill="none" stroke="#a1a1a1" stroke-width=".18"/>
<path d="M112.5 97.1l3.5 9M116 97.1l-3.5 9M112.5 127.6l3.5 9M116 127.6l-3.5 9M112.5 142.8l3.5 9M116 142.8l-3.5 9" fill="none" stroke="#ff2626" stroke-width=".46"/>
<path d="M218.4 25.4v2.5M198.1 45.7v2.6" fill="none" stroke="#840000" stroke-width=".25"/>
<g fill="none" stroke="#848400" stroke-width=".18">
<path d="M218.4 73h.7l.6 .7-.6 .6h-.7zM52.1 85.7h.6l.6 .7-.6 .6h-.6zM52.1 83.2h.6l.6 .6-.6 .7h-.6zM52.1 80.6h.6l.6 .7-.6 .6h-.6zM75.6 90.8h.6v1.3h-.6l-.7-.7zM105.4 95.9h.6l.7 .6-.7 .7h-.6zM105.4 111.1h.6l.7 .7-.7 .6h-.6zM105.4 106h.6l.7 .7-.7 .6h-.6zM105.4 121.3h.6l.7 .6-.7 .7h-.6zM105.4 126.4h.6l.7 .6-.7 .6h-.6zM105.4 136.5h.6l.7 .7-.7 .6h-.6zM105.4 151.8h.6l.7 .6-.7 .6h-.6z"/>
<path d="M105.4 156.8h.6l.7 .7-.7 .6h-.6zM105.4 141.6h.6l.7 .6-.7 .7h-.6zM105.4 167h.6l.7 .6-.7 .7h-.6z"/>
</g>
<path d="M218.4 73.7h-20.3v78.7" fill="none" stroke="#000084" stroke-width=".25"/>
<g fill="none" stroke="#008400" stroke-width=".18">
<path d="M55.9 27.9v2.6h5.1M71.1 30.5h76.2v35.5M203.2 30.5h-50.8v35.5M218.4 27.9v2.6h-5M88.9 58.4v5.1M198.1 48.3v2.5h-38.1v15.2M55.9 78.7v2.6M83.8 76.2h35.6M88.9 73.7v7.6M88.9 61h5.1v2.5M94 73.7v5h25.4M144.8 63.5v2.5"/>
<path d="M147.3 63.5h-5.1v2.5M152.4 63.5h2.5v2.5M53.3 83.8h66.1M53.3 81.3h66.1M53.3 86.4h66.1M55.9 86.4v2.5M63.5 83.8v5.1M76.2 91.4h43.2M88.9 91.4v2.6M106.7 96.5h12.7M198.1 81.3l-2.5 2.5h-12.7M198.1 88.9l-2.5 2.5h-12.7"/>
<path d="M198.1 83.8l-2.5 2.6h-12.7M198.1 91.4l-2.5 2.6h-12.7M198.1 99.1l-2.5 2.5h-12.7M198.1 96.5l-2.5 2.6h-12.7M88.9 104.1v2.6M106.7 106.7h12.7M106.7 111.8h12.7M198.1 119.4l-2.5 2.5h-12.7M198.1 104.1l-2.5 2.6h-12.7M198.1 106.7l-2.5 2.5h-12.7M198.1 111.8l-2.5 2.5h-12.7M198.1 114.3l-2.5 2.5h-12.7"/>
<path d="M106.7 137.2h12.7M106.7 121.9h12.7M106.7 127h12.7M198.1 134.6l-2.5 2.6h-12.7M198.1 137.2l-2.5 2.5h-12.7M198.1 121.9l-2.5 2.6h-12.7M198.1 127l-2.5 2.5h-12.7M198.1 129.5l-2.5 2.6h-12.7M106.7 152.4h12.7M106.7 142.2h12.7M106.7 157.5h12.7M198.1 149.9l-2.5 2.5h-12.7"/>
<path d="M198.1 152.4l-2.5 2.5h-12.7M198.1 142.2l-2.5 2.6h-12.7M198.1 144.8l-2.5 2.5h-12.7M119.4 160v7.6h-12.7M142.2 170.2v5.1M144.8 170.2v2.5M147.3 170.2v2.5M149.9 170.2v2.5M152.4 170.2v2.5h-10.2M157.5 170.2v5.1M160 170.2v2.5h-2.5"/>
</g>
<g fill="none" stroke="#0000c2" stroke-width=".18">
<path d="M64.1 36.8h.6M64.4 35.9l.4 1.3M73.7 36.3l.4 .1M74.1 37.1l-.4 .1M74.1 35.9v1.3M203.8 36.8h.6M204.1 35.9l.4 1.3M213.4 36.3l.4 .1M213.8 35.9v1.3M213.8 37.1l-.4 .1M177.1 171.5h.4M177.5 171v1.3"/>
<path d="M177.5 172.2l-.4 .1M177.8 168.9l.1 .1M177.9 168.5v1.3M177.9 169.7l-.1 .1"/>
</g>
<path d="M15.7 17l.6-1.9 .6 1.9M18.5 15.3l-.5-.2h-.4v1.9M20.6 15.2a.66 .66 0 0 0-1 .1" fill="none" stroke="#0000c2" stroke-width=".38"/>
<g fill="#008400" stroke="#008400" stroke-width=".18">
<circle cx="63.5" cy="83.8" r=".46"/>
<circle cx="55.9" cy="86.4" r=".46"/>
<circle cx="81.3" cy="91.4" r=".46"/>
<circle cx="88.9" cy="91.4" r=".46"/>
<circle cx="88.9" cy="81.3" r=".46"/>
<circle cx="88.9" cy="61" r=".46"/>
<circle cx="55.9" cy="81.3" r=".46"/>
<circle cx="83.8" cy="30.5" r=".46"/>
<circle cx="114.3" cy="142.2" r=".46"/>
<circle cx="114.3" cy="167.6" r=".46"/>
<circle cx="114.3" cy="137.2" r=".46"/>
<circle cx="114.3" cy="121.9" r=".46"/>
<circle cx="114.3" cy="127" r=".46"/>
<circle cx="114.3" cy="111.8" r=".46"/>
<circle cx="114.3" cy="106.7" r=".46"/>
<circle cx="114.3" cy="96.5" r=".46"/>
<circle cx="129.5" cy="30.5" r=".46"/>
<circle cx="139.7" cy="30.5" r=".46"/>
<circle cx="88.9" cy="30.5" r=".46"/>
<circle cx="99.1" cy="30.5" r=".46"/>
<circle cx="157.5" cy="30.5" r=".46"/>
<circle cx="109.2" cy="30.5" r=".46"/>
<circle cx="119.4" cy="30.5" r=".46"/>
<circle cx="157.5" cy="172.7" r=".46"/>
<circle cx="152.4" cy="63.5" r=".46"/>
<circle cx="144.8" cy="63.5" r=".46"/>
<circle cx="147.3" cy="63.5" r=".46"/>
<circle cx="167.6" cy="30.5" r=".46"/>
<circle cx="167.6" cy="50.8" r=".46"/>
<circle cx="177.8" cy="50.8" r=".46"/>
<circle cx="149.9" cy="172.7" r=".46"/>
<circle cx="114.3" cy="157.5" r=".46"/>
<circle cx="114.3" cy="152.4" r=".46"/>
<circle cx="144.8" cy="172.7" r=".46"/>
<circle cx="147.3" cy="172.7" r=".46"/>
<circle cx="142.2" cy="172.7" r=".46"/>
<circle cx="193" cy="30.5" r=".46"/>
<circle cx="177.8" cy="30.5" r=".46"/>
<circle cx="188" cy="30.5" r=".46"/>
</g>
<use href="#words"/>
</svg>
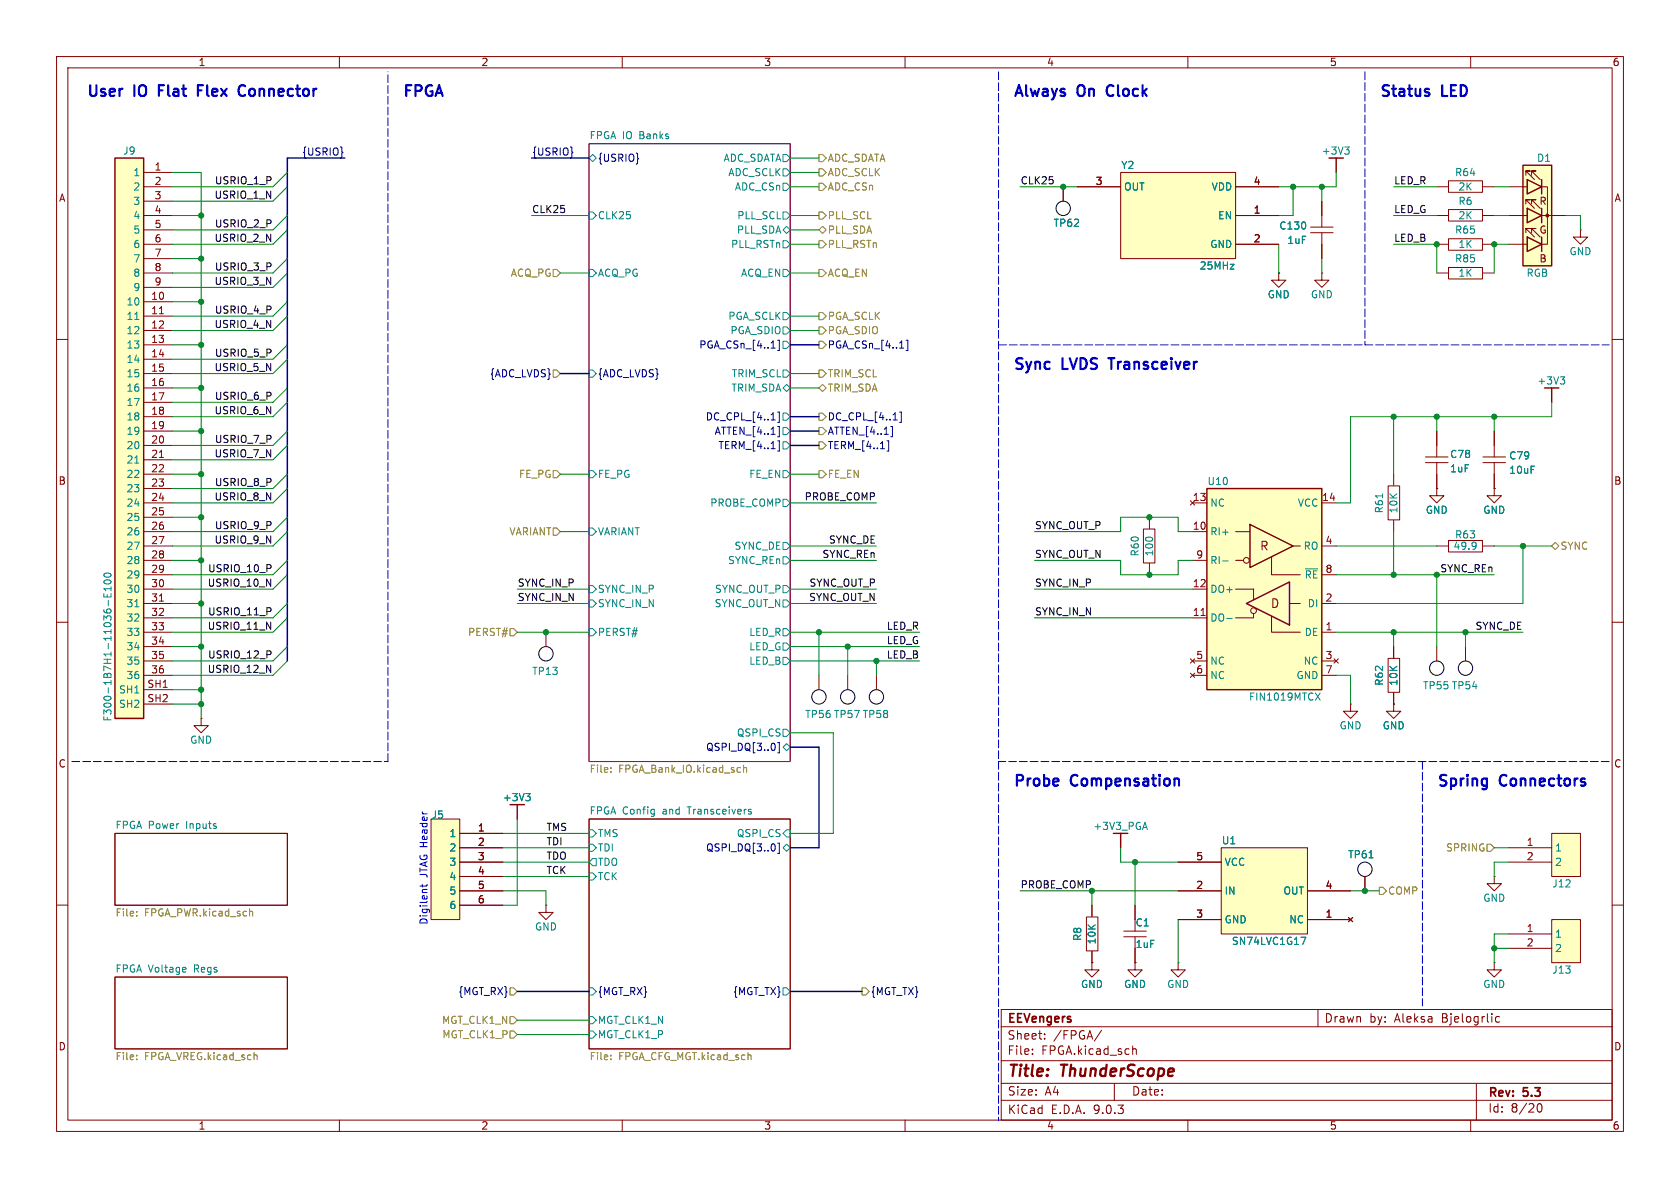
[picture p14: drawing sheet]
<svg xmlns="http://www.w3.org/2000/svg" width="297mm" height="210mm" viewBox="0 0 297 210" stroke-linecap="round" stroke-linejoin="round" font-family="sans-serif">
<defs><g id="words">
<g font-size="2.8" fill="#840000">
<text x="178" y="190.9">Title:</text>
<text x="187.7" y="190.9">ThunderScope</text>
</g>
<g font-size="2.7" fill="#0000c2">
<text x="15.2" y="18">User</text>
<text x="23.8" y="18">IO</text>
<text x="28.9" y="18">Flat</text>
<text x="36.6" y="18">Flex</text>
<text x="44.6" y="18">Connector</text>
<text x="71.1" y="18">FPGA</text>
<text x="179.1" y="18">Always</text>
<text x="190.6" y="18">On</text>
<text x="196.6" y="18">Clock</text>
<text x="243.8" y="18">Status</text>
<text x="255" y="18">LED</text>
<text x="179.1" y="66.3">Sync</text>
<text x="187.9" y="66.3">LVDS</text>
<text x="197" y="66.3">Transceiver</text>
<text x="179.1" y="140">Probe</text>
<text x="189.4" y="140">Compensation</text>
<text x="254" y="140">Spring</text>
<text x="265.3" y="140">Connectors</text>
</g>
<g font-size="2.1" fill="#840000">
<text x="222.7" y="97.5">R</text>
<text x="224.6" y="107.7">D</text>
<text x="178" y="184">Sheet:</text>
<text x="178" y="181.2">EEVengers</text>
<text x="186.2" y="184">/FPGA/</text>
<text x="234.1" y="181">Drawn</text>
<text x="242.1" y="181">by:</text>
<text x="246.6" y="181">Aleksa</text>
<text x="255" y="181">Bjelogrlic</text>
<text x="178" y="186.7">File:</text>
<text x="184.1" y="186.7">FPGA.kicad_sch</text>
<text x="178.1" y="197.1">KiCad</text>
<text x="178.1" y="193.9">Size:</text>
<text x="184.7" y="193.9">A4</text>
<text x="185.8" y="197.1">E.D.A.</text>
<text x="193.4" y="197.1">9.0.3</text>
<text x="200" y="193.9">Date:</text>
<text x="263" y="194.3">Rev:</text>
<text x="263" y="196.9">Id:</text>
<text x="267.1" y="196.9">8/20</text>
<text x="269.4" y="194.3">5.3</text>
</g>
<g font-size="1.8" fill="#840000">
<text x="35" y="11.9">1</text>
<text x="85" y="11.9">2</text>
<text x="135" y="11.9">3</text>
<text x="185" y="11.9">4</text>
<text x="235" y="11.9">5</text>
<text x="285" y="11.9">6</text>
<text x="10.3" y="35.9">A</text>
<text x="27.2" y="30.2">1</text>
<text x="27.2" y="32.8">2</text>
<text x="27.2" y="35.3">3</text>
<text x="193.6" y="32.8">3</text>
<text x="221.5" y="32.8">4</text>
<text x="285.3" y="35.9">A</text>
<text x="27.2" y="37.8">4</text>
<text x="27.2" y="40.4">5</text>
<text x="221.5" y="37.8">1</text>
<text x="272.1" y="36.4">R</text>
<text x="272.1" y="41.5">G</text>
<text x="27.2" y="42.9">6</text>
<text x="27.2" y="45.5">7</text>
<text x="221.5" y="42.9">2</text>
<text x="272.1" y="46.6">B</text>
<text x="26.6" y="53.1">10</text>
<text x="27.2" y="48">8</text>
<text x="27.2" y="50.5">9</text>
<text x="26.6" y="55.6">11</text>
<text x="26.6" y="58.2">12</text>
<text x="26.6" y="60.7">13</text>
<text x="26.6" y="63.2">14</text>
<text x="26.6" y="65.8">15</text>
<text x="26.6" y="68.3">16</text>
<text x="26.6" y="70.9">17</text>
<text x="26.6" y="73.4">18</text>
<text x="26.6" y="75.9">19</text>
<text x="26.6" y="78.5">20</text>
<text x="26.6" y="81">21</text>
<text x="26.6" y="83.6">22</text>
<text x="10.3" y="85.9">B</text>
<text x="26.6" y="86.1">23</text>
<text x="26.6" y="88.6">24</text>
<text x="210.8" y="88.6">13</text>
<text x="233.6" y="88.6">14</text>
<text x="285.3" y="85.9">B</text>
<text x="26.6" y="91.2">25</text>
<text x="26.6" y="93.7">26</text>
<text x="210.8" y="93.7">10</text>
<text x="26.6" y="96.3">27</text>
<text x="26.6" y="98.8">28</text>
<text x="26.6" y="101.3">29</text>
<text x="211.4" y="98.8">9</text>
<text x="234.2" y="96.3">4</text>
<text x="234.2" y="101.3">8</text>
<text x="26.6" y="103.9">30</text>
<text x="26.6" y="106.4">31</text>
<text x="210.8" y="103.9">12</text>
<text x="234.2" y="106.4">2</text>
<text x="26.6" y="109">32</text>
<text x="26.6" y="111.5">33</text>
<text x="210.8" y="109">11</text>
<text x="234.2" y="111.5">1</text>
<text x="26.6" y="114">34</text>
<text x="26.6" y="116.6">35</text>
<text x="26.6" y="119.1">36</text>
<text x="211.4" y="116.6">5</text>
<text x="211.4" y="119.1">6</text>
<text x="234.2" y="116.6">3</text>
<text x="234.2" y="119.1">7</text>
<text x="26" y="121.7">SH1</text>
<text x="26" y="124.2">SH2</text>
<text x="10.3" y="135.9">C</text>
<text x="285.3" y="135.9">C</text>
<text x="84.4" y="147.1">1</text>
<text x="84.4" y="149.6">2</text>
<text x="269.8" y="149.6">1</text>
<text x="84.4" y="152.1">3</text>
<text x="84.4" y="154.7">4</text>
<text x="211.4" y="152.1">5</text>
<text x="269.8" y="152.1">2</text>
<text x="84.4" y="157.2">5</text>
<text x="84.4" y="159.8">6</text>
<text x="211.4" y="157.2">2</text>
<text x="234.2" y="157.2">4</text>
<text x="211.4" y="162.3">3</text>
<text x="234.2" y="162.3">1</text>
<text x="269.8" y="167.4">2</text>
<text x="269.8" y="164.8">1</text>
<text x="10.3" y="185.9">D</text>
<text x="285.3" y="185.9">D</text>
<text x="35" y="199.9">1</text>
<text x="85" y="199.9">2</text>
<text x="135" y="199.9">3</text>
<text x="185" y="199.9">4</text>
<text x="235" y="199.9">5</text>
<text x="285" y="199.9">6</text>
</g>
<g font-size="1.8" fill="#008484">
<text x="21.7" y="27.5">J9</text>
<text x="104.1" y="24.7">FPGA IO</text>
<text x="113.1" y="24.7">Banks</text>
<text x="127.8" y="28.8">ADC_SDATA</text>
<text x="233.6" y="27.5">+3V3</text>
<text x="271.6" y="28.8">D1</text>
<text x="23.5" y="31.3">1</text>
<text x="23.5" y="33.9">2</text>
<text x="128.7" y="31.3">ADC_SCLK</text>
<text x="129.8" y="33.9">ADC_CSn</text>
<text x="198.1" y="30.1">Y2</text>
<text x="198.6" y="33.9">OUT</text>
<text x="214.1" y="33.9">VDD</text>
<text x="257.1" y="31.3">R64</text>
<text x="257.7" y="33.9">2K</text>
<text x="23.5" y="36.4">3</text>
<text x="23.5" y="39">4</text>
<text x="23.5" y="41.5">5</text>
<text x="105.6" y="39">CLK25</text>
<text x="130.2" y="41.5">PLL_SDA</text>
<text x="130.2" y="39">PLL_SCL</text>
<text x="186.2" y="40.3">TP62</text>
<text x="215.2" y="39">EN</text>
<text x="226.1" y="40.8">C130</text>
<text x="257.1" y="41.5">R65</text>
<text x="257.7" y="36.4">R6</text>
<text x="257.7" y="39">2K</text>
<text x="23.5" y="44">6</text>
<text x="23.5" y="46.6">7</text>
<text x="129.1" y="44">PLL_RSTn</text>
<text x="212" y="47.9">25MHz</text>
<text x="213.9" y="44">GND</text>
<text x="227.5" y="43.3">1uF</text>
<text x="257.1" y="46.6">R85</text>
<text x="257.7" y="44">1K</text>
<text x="277.4" y="45.3">GND</text>
<text x="23.5" y="49.1">8</text>
<text x="23.5" y="51.7">9</text>
<text x="105.6" y="49.1">ACQ_PG</text>
<text x="130.9" y="49.1">ACQ_EN</text>
<text x="224" y="52.9">GND</text>
<text x="231.6" y="52.9">GND</text>
<text x="257.7" y="49.1">1K</text>
<text x="269.8" y="49.1">RGB</text>
<text x="22.3" y="54.2">10</text>
<text x="22.3" y="56.7">11</text>
<text x="22.3" y="59.3">12</text>
<text x="128.7" y="56.7">PGA_SCLK</text>
<text x="129" y="59.3">PGA_SDIO</text>
<text x="22.3" y="61.8">13</text>
<text x="22.3" y="64.4">14</text>
<text x="22.3" y="66.9">15</text>
<text x="22.3" y="69.4">16</text>
<text x="22.3" y="72">17</text>
<text x="129.2" y="69.4">TRIM_SDA</text>
<text x="129.3" y="66.9">TRIM_SCL</text>
<text x="271.7" y="68.2">+3V3</text>
<text x="22.3" y="74.5">18</text>
<text x="22.3" y="77.1">19</text>
<text x="22.3" y="79.6">20</text>
<text x="22.3" y="82.1">21</text>
<text x="256.3" y="83.7">1uF</text>
<text x="256.3" y="81.2">C78</text>
<text x="266.7" y="81.4">C79</text>
<text x="266.7" y="84">10uF</text>
<text x="22.3" y="84.7">22</text>
<text x="22.3" y="87.2">23</text>
<text x="22.3" y="89.8">24</text>
<text x="105.6" y="84.7">FE_PG</text>
<text x="125.5" y="89.8">PROBE_COMP</text>
<text x="132.4" y="84.7">FE_EN</text>
<text x="213.4" y="86">U10</text>
<text x="213.9" y="89.8">NC</text>
<text x="229.3" y="89.8">VCC</text>
<text x="22.3" y="92.3">25</text>
<text x="22.3" y="94.8">26</text>
<text x="105.6" y="94.8">VARIANT</text>
<text x="213.9" y="94.8">RI+</text>
<text x="244.7" y="90.8" transform="rotate(-90 244.7 90.8)">R61</text>
<text x="247.2" y="90.8" transform="rotate(-90 247.2 90.8)">10K</text>
<text x="252" y="91">GND</text>
<text x="257.1" y="95.4">R63</text>
<text x="262.1" y="91">GND</text>
<text x="22.3" y="97.4">27</text>
<text x="22.3" y="99.9">28</text>
<text x="128.6" y="99.9">SYNC_REn</text>
<text x="129.8" y="97.4">SYNC_DE</text>
<text x="201.5" y="98.5" transform="rotate(-90 201.5 98.5)">R60</text>
<text x="204.1" y="98.4" transform="rotate(-90 204.1 98.4)">100</text>
<text x="213.9" y="99.9">RI-</text>
<text x="230.4" y="97.4">RO</text>
<text x="256.9" y="97.4">49.9</text>
<text x="22.3" y="102.5">29</text>
<text x="22.3" y="105">30</text>
<text x="22.3" y="107.5">31</text>
<text x="105.6" y="105">SYNC_IN_P</text>
<text x="105.6" y="107.5">SYNC_IN_N</text>
<text x="126.2" y="107.5">SYNC_OUT_N</text>
<text x="126.3" y="105">SYNC_OUT_P</text>
<text x="213.9" y="105">DO+</text>
<text x="230.5" y="102.5">~{RE}</text>
<text x="231.1" y="107.5">DI</text>
<text x="22.3" y="110.1">32</text>
<text x="22.3" y="112.6">33</text>
<text x="105.6" y="112.6">PERST#</text>
<text x="132.4" y="112.6">LED_R</text>
<text x="213.9" y="110.1">DO-</text>
<text x="230.5" y="112.6">DE</text>
<text x="22.3" y="115.2">34</text>
<text x="22.3" y="117.7">35</text>
<text x="94" y="119.5">TP13</text>
<text x="132.4" y="115.2">LED_G</text>
<text x="132.4" y="117.7">LED_B</text>
<text x="213.9" y="117.7">NC</text>
<text x="230.4" y="117.7">NC</text>
<text x="20.9" y="122.8">SH1</text>
<text x="20.9" y="125.3">SH2</text>
<text x="22.3" y="120.2">36</text>
<text x="213.9" y="120.2">NC</text>
<text x="220.7" y="124.1">FIN1019MTCX</text>
<text x="229.1" y="120.2">GND</text>
<text x="244.7" y="121.3" transform="rotate(-90 244.7 121.3)">R62</text>
<text x="247.2" y="121.3" transform="rotate(-90 247.2 121.3)">10K</text>
<text x="251.5" y="122.1">TP55 TP54</text>
<text x="19.9" y="127.6" transform="rotate(-90 19.9 127.6)">F300-1B7H1-11036-E100</text>
<text x="33.5" y="131.7">GND</text>
<text x="130.2" y="130.4">QSPI_CS</text>
<text x="142.2" y="127.1">TP56 TP57 TP58</text>
<text x="236.7" y="129.1">GND</text>
<text x="244.3" y="129.1">GND</text>
<text x="88.8" y="141.8">+3V3</text>
<text x="20.3" y="146.6">FPGA Power</text>
<text x="33" y="146.6">Inputs</text>
<text x="76.2" y="144.9">J5</text>
<text x="79.4" y="148.2">1</text>
<text x="104.1" y="144.1">FPGA Config</text>
<text x="105.6" y="148.2">TMS</text>
<text x="117.2" y="144.1">and</text>
<text x="121.9" y="144.1">Transceivers</text>
<text x="130.2" y="148.2">QSPI_CS</text>
<text x="193.2" y="146.9">+3V3_PGA</text>
<text x="215.9" y="149.5">U1</text>
<text x="79.4" y="150.7">2</text>
<text x="79.4" y="153.3">3</text>
<text x="79.4" y="155.8">4</text>
<text x="105.6" y="150.7">TDI</text>
<text x="105.6" y="153.3">TDO</text>
<text x="105.6" y="155.8">TCK</text>
<text x="216.4" y="153.3">VCC</text>
<text x="238.2" y="151.9">TP61</text>
<text x="274.8" y="153.3">2</text>
<text x="274.8" y="150.7">1</text>
<text x="79.4" y="158.3">5</text>
<text x="79.4" y="160.9">6</text>
<text x="216.4" y="158.3">IN</text>
<text x="226.8" y="158.3">OUT</text>
<text x="262.1" y="159.6">GND</text>
<text x="274.3" y="157.1">J12</text>
<text x="94.5" y="164.7">GND</text>
<text x="191.4" y="166.4" transform="rotate(-90 191.4 166.4)">R8</text>
<text x="193.9" y="167" transform="rotate(-90 193.9 167)">10K</text>
<text x="200.7" y="164">C1</text>
<text x="200.7" y="167.8">1uF</text>
<text x="216.4" y="163.4">GND</text>
<text x="217.7" y="167.2">SN74LVC1G17</text>
<text x="227.8" y="163.4">NC</text>
<text x="274.8" y="166">1</text>
<text x="20.3" y="172">FPGA Voltage</text>
<text x="34.4" y="172">Regs</text>
<text x="274.3" y="172.3">J13</text>
<text x="274.8" y="168.5">2</text>
<text x="191" y="174.9">GND</text>
<text x="198.6" y="174.9">GND</text>
<text x="206.2" y="174.9">GND</text>
<text x="262.1" y="174.9">GND</text>
<text x="105.6" y="181.2">MGT_CLK1_N</text>
<text x="105.6" y="183.7">MGT_CLK1_P</text>
</g>
<g font-size="1.8" fill="#000084">
<text x="53.3" y="27.6">{USRIO}</text>
<text x="94" y="27.6">{USRIO}</text>
<text x="105.6" y="28.8">{USRIO}</text>
<text x="123.5" y="61.8">PGA_CSn_[4..1]</text>
<text x="146.2" y="61.8">PGA_CSn_[4..1]</text>
<text x="86.5" y="66.9">{ADC_LVDS}</text>
<text x="105.6" y="66.9">{ADC_LVDS}</text>
<text x="124.7" y="74.5">DC_CPL_[4..1]</text>
<text x="126.2" y="77.1">ATTEN_[4..1]</text>
<text x="146.2" y="77.1">ATTEN_[4..1]</text>
<text x="146.2" y="74.5">DC_CPL_[4..1]</text>
<text x="126.9" y="79.6">TERM_[4..1]</text>
<text x="146.2" y="79.6">TERM_[4..1]</text>
<text x="124.7" y="132.9">QSPI_DQ[3..0]</text>
<text x="124.7" y="150.7">QSPI_DQ[3..0]</text>
<text x="80.9" y="176.1">{MGT_RX}</text>
<text x="105.6" y="176.1">{MGT_RX}</text>
<text x="129.5" y="176.1">{MGT_TX}</text>
<text x="153.9" y="176.1">{MGT_TX}</text>
</g>
<g font-size="1.8" fill="#848400">
<text x="146.2" y="28.8">ADC_SDATA</text>
<text x="146.2" y="31.3">ADC_SCLK</text>
<text x="146.2" y="33.9">ADC_CSn</text>
<text x="146.2" y="41.5">PLL_SDA</text>
<text x="146.2" y="39">PLL_SCL</text>
<text x="146.2" y="44">PLL_RSTn</text>
<text x="90.2" y="49.1">ACQ_PG</text>
<text x="146.2" y="49.1">ACQ_EN</text>
<text x="146.2" y="56.7">PGA_SCLK</text>
<text x="146.2" y="59.3">PGA_SDIO</text>
<text x="146.2" y="69.4">TRIM_SDA</text>
<text x="146.2" y="66.9">TRIM_SCL</text>
<text x="91.7" y="84.7">FE_PG</text>
<text x="146.2" y="84.7">FE_EN</text>
<text x="90" y="94.8">VARIANT</text>
<text x="275.8" y="97.4">SYNC</text>
<text x="82.6" y="112.6">PERST#</text>
<text x="104.1" y="136.9">File:</text>
<text x="109.4" y="136.9">FPGA_Bank_IO.kicad_sch</text>
<text x="255.5" y="150.7">SPRING</text>
<text x="245.3" y="158.3">COMP</text>
<text x="20.3" y="162.3">File:</text>
<text x="25.5" y="162.3">FPGA_PWR.kicad_sch</text>
<text x="78" y="181.2">MGT_CLK1_N</text>
<text x="78.1" y="183.7">MGT_CLK1_P</text>
<text x="20.3" y="187.7">File:</text>
<text x="25.5" y="187.7">FPGA_VREG.kicad_sch</text>
<text x="104.1" y="187.7">File:</text>
<text x="109.4" y="187.7">FPGA_CFG_MGT.kicad_sch</text>
</g>
<g font-size="1.8">
<text x="37.8" y="35.2">USRIO_1_N</text>
<text x="37.9" y="32.7">USRIO_1_P</text>
<text x="180.3" y="32.7">CLK25</text>
<text x="246.4" y="32.7">LED_R</text>
<text x="37.9" y="40.3">USRIO_2_P</text>
<text x="94" y="37.8">CLK25</text>
<text x="246.4" y="37.8">LED_G</text>
<text x="37.8" y="42.8">USRIO_2_N</text>
<text x="37.9" y="47.9">USRIO_3_P</text>
<text x="246.4" y="42.8">LED_B</text>
<text x="37.8" y="50.5">USRIO_3_N</text>
<text x="37.8" y="58.1">USRIO_4_N</text>
<text x="37.9" y="55.5">USRIO_4_P</text>
<text x="37.8" y="65.7">USRIO_5_N</text>
<text x="37.9" y="63.2">USRIO_5_P</text>
<text x="37.9" y="70.8">USRIO_6_P</text>
<text x="37.8" y="73.3">USRIO_6_N</text>
<text x="37.8" y="80.9">USRIO_7_N</text>
<text x="37.9" y="78.4">USRIO_7_P</text>
<text x="37.8" y="88.6">USRIO_8_N</text>
<text x="37.9" y="86">USRIO_8_P</text>
<text x="142.2" y="88.6">PROBE_COMP</text>
<text x="37.9" y="93.6">USRIO_9_P</text>
<text x="182.9" y="93.6">SYNC_OUT_P</text>
<text x="36.7" y="101.3">USRIO_10_P</text>
<text x="37.8" y="96.2">USRIO_9_N</text>
<text x="145.3" y="98.7">SYNC_REn</text>
<text x="146.5" y="96.2">SYNC_DE</text>
<text x="182.9" y="98.7">SYNC_OUT_N</text>
<text x="254.5" y="101.3">SYNC_REn</text>
<text x="36.6" y="103.8">USRIO_10_N</text>
<text x="91.4" y="106.3">SYNC_IN_N</text>
<text x="91.4" y="103.8">SYNC_IN_P</text>
<text x="142.9" y="106.3">SYNC_OUT_N</text>
<text x="143" y="103.8">SYNC_OUT_P</text>
<text x="182.9" y="103.8">SYNC_IN_P</text>
<text x="36.6" y="111.4">USRIO_11_N</text>
<text x="36.7" y="108.9">USRIO_11_P</text>
<text x="156.7" y="114">LED_G</text>
<text x="156.7" y="111.4">LED_R</text>
<text x="182.9" y="108.9">SYNC_IN_N</text>
<text x="260.8" y="111.4">SYNC_DE</text>
<text x="36.6" y="119">USRIO_12_N</text>
<text x="36.7" y="116.5">USRIO_12_P</text>
<text x="156.7" y="116.5">LED_B</text>
<text x="96.5" y="147">TMS</text>
<text x="96.5" y="149.5">TDI</text>
<text x="96.5" y="152.1">TDO</text>
<text x="96.5" y="154.6">TCK</text>
<text x="180.3" y="157.1">PROBE_COMP</text>
</g>
<g font-size="1.8" fill="#0000c2">
<text x="75.8" y="155.1" transform="rotate(-90 75.8 155.1)">JTAG Header</text>
<text x="75.8" y="163.6" transform="rotate(-90 75.8 163.6)">Digilent</text>
</g>
</g></defs>
<path d="M0 0h297v210h-297z" fill="#fff" stroke="#fff" stroke-width=".18"/>
<g fill="none" stroke="#840000" stroke-width=".18">
<path d="M10 10h277v190h-277zM12 12h273v186h-273zM60 10v2M110 10v2M160 10v2M210 10v2M260 10v2M226.1 48.3v1.2h-1.3l1.3 1.3 1.2-1.3h-1.2M226.1 48.3h.1M10 60h2M285 60h2M10 110h2"/>
<path d="M259.1 114.3v2.5M285 110h2M241.3 154.9v2.6M10 160h2M177 178.5h108v19.5h-108zM233 178.5v3M265.1 179.8l-.4-.1-.3 .3v.4l.1 .2h.6M285 160h2M60 198v2M110 198v2M160 198v2M177 194.5h108"/>
<path d="M177 191.5h108M177 187.5h108M177 181.5h108M182.5 186.3v.1M182.5 185.5v.1M184.7 183.6v.1M184.7 182.8v.1M194.7 182.1l-1.2 2M197 191.5v3M200.2 184.9v1.5M200.2 185.5l.3-.1 .3 .1 .1 .9M210 198v2"/>
<path d="M260 198v2M261 191.5v6.5M271.7 195.7l.2-.5 .2-.1a.81 .81 0 0 1 .6 .6 .81 .81 0 0 1-.3 .8h-.4l-.3-.5"/>
</g>
<path d="M20.3 147.3h30.5v12.7h-30.5zM104.1 144.8h35.6v40.6h-35.6zM20.3 172.7h30.5v12.7h-30.5z" fill="none" stroke="#800000" stroke-width=".18"/>
<path d="M104.1 25.4h35.6v109.2h-35.6z" fill="none" stroke="#840084" stroke-width=".18"/>
<g fill="none" stroke="#848400" stroke-width=".18">
<path d="M108 136.4v.1M108 135.7v.2M130.8 135.7h.1M130.9 136.5h-.1M131.5 135.3v1.2M131.5 135.8l.1-.1h.3l.1 .8M24.2 161.8v.1M24.2 161.1v.2M44.3 161.1l.4 .2v.6M24.2 186.5v.2M24.2 187.2v.1M45.1 186.5l.4 .2v.6"/>
<path d="M108 186.5v.2M108 187.2v.1M132.6 186.5l.2 .2v.6"/>
</g>
<g fill="none" stroke="#008484" stroke-width=".18">
<path d="M104.1 27.9l.7-.6 .6 .6-.6 .7zM104.1 37.5h.7l.6 .6-.6 .6h-.7zM138.4 32.4h.7l.6 .6-.6 .7h-.7zM138.4 27.3h.7l.6 .6-.6 .7h-.7zM138.4 29.8h.7l.6 .7-.6 .6h-.7zM138.4 37.5h.7l.6 .6-.6 .6h-.7zM104.1 47.6h.7l.6 .7-.6 .6h-.7zM138.4 42.5h.7l.6 .7-.6 .6h-.7zM138.4 40.6l.7-.6 .6 .6-.6 .7zM138.4 47.6h.7l.6 .7-.6 .6h-.7zM138.4 55.2h.7l.6 .7-.6 .6h-.7zM138.4 57.8h.7l.6 .6-.6 .7h-.7z"/>
<path d="M104.1 65.4h.7l.6 .6-.6 .7h-.7zM138.4 75.6h.7l.6 .6-.6 .6h-.7zM138.4 78.1h.7l.6 .6-.6 .7h-.7zM138.4 73h.7l.6 .7-.6 .6h-.7zM138.4 60.3h.7l.6 .7-.6 .6h-.7zM138.4 65.4h.7l.6 .6-.6 .7h-.7zM138.4 68.6l.7-.7 .6 .7-.6 .6zM275.8 66.6h.8l-.4 .5M276.4 67.1l.2 .2v.3l-.2 .3M104.1 83.2h.7l.6 .6-.6 .7h-.7zM104.1 93.3h.7l.6 .7-.6 .6h-.7zM138.4 83.2h.7l.6 .6-.6 .7h-.7z"/>
<path d="M138.4 88.3h.7l.6 .6-.6 .6h-.7zM138.4 95.9h.7l.6 .6-.6 .7h-.7zM138.4 98.4h.7l.6 .7-.6 .6h-.7zM104.1 111.1h.7l.6 .7-.6 .6h-.7zM104.1 103.5h.7l.6 .6-.6 .7h-.7zM104.1 106h.7l.6 .7-.6 .6h-.7zM138.4 106h.7l.6 .7-.6 .6h-.7zM138.4 103.5h.7l.6 .6-.6 .7h-.7zM138.4 111.1h.7l.6 .7-.6 .6h-.7zM138.4 113.7h.7l.6 .6-.6 .6h-.7zM138.4 116.2h.7l.6 .6-.6 .7h-.7zM138.4 128.9h.7l.6 .6-.6 .7h-.7z"/>
<path d="M138.4 132.1l.7-.7 .6 .7-.6 .6zM104.1 149.2h.7l.6 .7-.6 .6h-.7zM104.1 154.3h.7l.6 .6-.6 .7h-.7zM104.1 146.7h.7l.6 .6-.6 .7h-.7zM104.8 151.8h.6v1.2h-.6l-.7-.6zM115.5 143.1h.2M115.7 143.1l-.1 1.1M115.7 143.8l-.2 .1M132.5 143.5h.3v.2l-.1 .2h-.3M132.5 143.1h.3M139.1 149.2l.6 .7-.6 .6-.7-.6zM139.1 146.7h.6v1.3h-.6l-.7-.7z"/>
<path d="M242 151.6h.8M32.7 171l.2 .3-.6 .1M32.8 171.8h-.1M104.1 179.7h.7l.6 .6-.6 .7h-.7zM104.1 174.6h.7l.6 .7-.6 .6h-.7zM138.4 174.6h.7l.6 .7-.6 .6h-.7zM104.1 182.2h.7l.6 .7-.6 .6h-.7z"/>
</g>
<path d="M137.5 75.4h.3v1.8h-.3M137.5 60.1h.3v1.9h-.3M137.5 72.8h.3v1.9h-.3M137.5 77.9h.3v1.8h-.3M137 131.6v.8M137.5 131.3h.3v1.8h-.3M137 149.4v.8M137.5 149h.3v1.9h-.3" fill="none" stroke="#000084" stroke-width=".18"/>
<path d="M274.3 68.6v2.5" fill="none" stroke="#840000" stroke-width=".25"/>
<g fill="none" stroke="#000" stroke-width=".18">
<circle cx="259.1" cy="118.1" r="1.27"/>
<circle cx="241.3" cy="153.7" r="1.27"/>
</g>
<path d="M20.3 27.9h5.1v99.1h-5.1z" fill="#ffffc2"/>
<path d="M20.3 27.9h5.1v99.1h-5.1zM236.2 27.9v2.6M91.4 142.2v2.6" fill="none" stroke="#840000" stroke-width=".25"/>
<g fill="none" stroke="#840000" stroke-width=".18">
<path d="M25.4 30.5h5.1M25.4 33h5.1M25.4 35.6h5.1M25.4 38.1h5.1M188 33v2.6M233.7 35.6v4.5M254 33h2M254 38.1h2M256.1 32h6v2h-6zM256.1 37h6v2.1h-6zM262.2 33h2M262.2 38.1h2"/>
<path d="M25.4 40.6h5.1M25.4 43.2h5.1M25.4 45.7h5.1M25.4 48.3h5.1M25.4 50.8h5.1M25.4 53.3h5.1M25.4 55.9h5.1M25.4 58.4h5.1M28.2 55.5h.7M231.7 40.1h4M231.7 41.1h4M233.7 48.3v1.2h-1.3l1.3 1.3 1.2-1.3h-1.2"/>
<path d="M233.7 48.3h.1M233.7 41.1v4.6M254 43.2h2M254 48.3h2M256.1 42.2h6v2h-6zM256.1 47.3h6v2h-6zM262.2 43.2h2M262.2 48.3h2M25.4 61h5.1M25.4 63.5h5.1M25.4 66h5.1M25.4 68.6h5.1"/>
<path d="M25.4 71.1h5.1M25.4 73.7h5.1M25.4 76.2h5.1M25.4 78.7h5.1M254 76.2v4.6M264.2 76.2v4.6M25.4 81.3h5.1M25.4 83.8h5.1M25.4 86.4h5.1M25.4 88.9h5.1M25.4 91.4h5.1M25.4 94h5.1"/>
<path d="M25.4 96.5h5.1M25.4 99.1h5.1M28.2 80.9h.7M202.1 93.5h2.1v6h-2.1zM203.2 91.4v2M203.2 99.6v2M245.4 85.9h2v6h-2zM246.4 83.8v2M246.4 92v2M252 80.8h4M252 81.8h4M254 86.4v1.2h-1.3l1.3 1.3 1.3-1.3h-1.3"/>
<path d="M254 86.4h.1M254 96.5h2M254 81.8v4.6M256.1 95.5h6v2.1h-6zM262.2 96.5h2M262.2 80.8h4M262.2 81.8h4M264.2 86.4v1.2h-1.3l1.3 1.3 1.2-1.3h-1.2M264.2 86.4h.1M264.2 81.8v4.6M25.4 101.6h5.1M25.4 104.1h5.1"/>
<path d="M25.4 106.7h5.1M25.4 109.2h5.1M25.4 111.8h5.1M25.4 114.3h5.1M25.4 116.8h5.1M25.4 119.4h5.1M28.2 106.3h.7M154.9 119.4v2.5M25.4 121.9h5.1M25.4 124.5h5.1M35.6 127v1.3h-1.3l1.3 1.2 1.2-1.2h-1.2M35.6 127h.1"/>
<path d="M96.5 160v1.3h1.3l-1.3 1.3-1.3-1.3h1.3M96.5 160h.1M198.7 164.6h4M198.7 165.6h4M200.7 160v2.6M200.7 165.6v4.6"/>
</g>
<g fill="none" stroke="#008484" stroke-width=".18">
<path d="M237.7 26h.8l-.4 .5M238.3 26.5l.2 .2v.3l-.2 .2M23.8 56.5h.7M23.8 81.9h.7M244.4 87.3v.7M260.9 96a1.07 1.07 0 0 1-.1 1M261 96.4l-.2 .2M18.4 104.9v.6h1.2v-.6M18.5 101.4a.69 .69 0 0 1 1.1 .3 .72 .72 0 0 1-1.2-.1zM18.5 102.6a.69 .69 0 0 1 1.1 .3 .72 .72 0 0 1-1.2-.1zM19 105.1v.4M19.1 106.1v1"/>
<path d="M19.6 103.7v.7M19.6 104.1h-1.2l.3 .3M23.8 107.3h.7M93 140.3h.7l-.4 .5M93.5 140.8l.2 .2v.3l-.2 .2"/>
</g>
<g fill="none" stroke="#000" stroke-width=".18">
<circle cx="188" cy="36.8" r="1.27"/>
<circle cx="154.9" cy="123.2" r="1.27"/>
</g>
<path d="M76.2 144.8h5.1v17.8h-5.1z" fill="#ffffc2"/>
<path d="M76.2 144.8h5.1v17.8h-5.1z" fill="none" stroke="#800000" stroke-width=".18"/>
<path d="M81.3 147.3h7.6M81.3 149.9h7.6M81.3 152.4h7.6M81.3 154.9h7.6M81.3 157.5h7.6M81.3 160h7.6" fill="none" stroke="#840000" stroke-width=".18"/>
<path d="M215.9 149.9h15.2v15.2h-15.2z" fill="#ffffc2"/>
<path d="M215.9 149.9h15.2v15.2h-15.2z" fill="none" stroke="#800000" stroke-width=".18"/>
<g fill="none" stroke="#840000" stroke-width=".18">
<path d="M208.3 157.5h7.6M208.3 152.4h7.6M231.1 157.5h7.7M192.1 162.1h2v6h-2zM193 170.2v1.3h-1.2l1.2 1.2 1.3-1.2h-1.3M193 170.2h.1M193 160v2M193 168.2v2M200.7 170.2v1.3h-1.3l1.3 1.2 1.2-1.2h-1.2M200.7 170.2h.1M208.3 170.2v1.3h-1.3l1.3 1.2 1.2-1.2h-1.2M208.3 170.2h.1"/>
<path d="M208.3 162.6h7.6M231.1 162.6h7.7M238.4 162.2l.7 .7M239.1 162.2l-.7 .7"/>
</g>
<path d="M202.1 146.3h.6M202.4 145.4l.4 1.2M230 165.7h.8l-.5 1.2" fill="none" stroke="#008484" stroke-width=".18"/>
<path d="M198.1 147.3v2.6" fill="none" stroke="#840000" stroke-width=".25"/>
<path d="M213.4 86.4h20.3v35.5h-20.3z" fill="#ffffc2"/>
<path d="M213.4 86.4h20.3v35.5h-20.3zM221 92.7l7.6 3.8-7.6 3.8zM220.3 106.7l7.7-3.8v7.6z" fill="none" stroke="#840000" stroke-width=".25"/>
<g fill="none" stroke="#840000" stroke-width=".18">
<path d="M210.8 94h2.6M210.8 99.1h2.6M210.8 88.9h2.6M218.4 94h2.6M218.4 99.1h1.3M224.8 98.6v3h5.1M228.6 96.5h1.3M233.7 96.5h2.5M233.7 88.9h2.5M149.9 119.4v2.5M210.4 116.5l.8 .7M210.4 119l.8 .8"/>
<path d="M210.8 109.2h2.6M210.8 104.1h2.6M210.8 116.8h2.6M210.8 119.4h2.6M211.2 116.5l-.8 .7M211.2 119l-.8 .8M212.3 108.8h.8M218.4 104.1h3.2v1.9M221.6 108.5v.7h-3.2M224.8 109v2.8h5.1M228 106.7h1.9M233.7 106.7h2.5"/>
<path d="M233.7 101.6h2.5M233.7 111.8h2.5M233.7 116.8h2.5M233.7 119.4h2.5M235.8 116.5l.8 .7M236.6 116.5l-.8 .7M264.2 154.9v1.3h-1.3l1.3 1.3 1.2-1.3h-1.2M264.2 154.9h.1"/>
<circle cx="220.3" cy="99.1" r=".51"/>
<circle cx="221.6" cy="108" r=".51"/>
</g>
<path d="M216.1 99.2h1M216.9 109.3h.9M230.8 100.6h2.1M232.5 122.5l.9 1.3M233.4 122.5l-.9 1.3" fill="none" stroke="#008484" stroke-width=".18"/>
<circle cx="149.9" cy="123.2" r="1.27" fill="none" stroke="#000" stroke-width=".18"/>
<path d="M274.3 147.3h5.1v7.6h-5.1z" fill="#ffffc2"/>
<path d="M274.3 147.3h5.1v7.6h-5.1z" fill="none" stroke="#800000" stroke-width=".18"/>
<path d="M266.7 152.4h7.6M266.7 149.9h7.6" fill="none" stroke="#840000" stroke-width=".18"/>
<path d="M274.3 162.6h5.1v7.6h-5.1z" fill="#ffffc2"/>
<path d="M274.3 162.6h5.1v7.6h-5.1z" fill="none" stroke="#800000" stroke-width=".18"/>
<path d="M246.4 124.5v1.2h-1.3l1.3 1.3 1.2-1.3h-1.2M246.4 124.5h.1M264.2 170.2v1.3h-1.3l1.3 1.2 1.2-1.2h-1.2M264.2 170.2h.1M266.7 167.6h7.6M266.7 165.1h7.6" fill="none" stroke="#840000" stroke-width=".18"/>
<path d="M269.2 29.2h5.1v17.8h-5.1z" fill="#ffffc2"/>
<path d="M269.2 29.2h5.1v17.8h-5.1zM270 31.8l2.5 1.2-2.5 1.3zM270 36.8l2.5 1.3-2.5 1.3zM272.5 31.8v2.5M272.5 36.8v2.6M270 41.9l2.5 1.3-2.5 1.3zM272.5 41.9v2.6" fill="none" stroke="#840000" stroke-width=".25"/>
<g fill="none" stroke="#840000" stroke-width=".18">
<path d="M266.7 33h3.3M266.7 38.1h3.3M269.7 31v-.8h.8h-.8l1.6 1.6M269.7 36.1v-.8h.8h-.8l1.6 1.5M270.8 31v-.8h.7h-.7l1.5 1.6M270.8 36.1v-.8h.7h-.7l1.5 1.5M272.5 33h1.1v10.2h-1.1M272.5 38.1h4.4M266.7 43.2h3.3M269.7 41.1v-.7h.8h-.8l1.6 1.5M270.8 41.1v-.7h.7h-.7l1.5 1.5M279.4 40.6v1.3h1.3l-1.3 1.3-1.3-1.3h1.3"/>
<path d="M279.4 40.6h.1M96.5 111.8v2.5M144.8 119.4v2.5M245.4 116.4h2v6h-2zM246.4 114.3v2M254 114.3v2.5M238.8 124.5v1.2h-1.3l1.3 1.3 1.2-1.3h-1.2M238.8 124.5h.1M246.4 122.5v2"/>
</g>
<circle cx="273.6" cy="38.1" r=".25" fill="#840000" stroke="#840000" stroke-width=".18"/>
<g fill="none" stroke="#000" stroke-width=".18">
<circle cx="96.5" cy="115.6" r="1.27"/>
<circle cx="254" cy="118.1" r="1.27"/>
<circle cx="144.8" cy="123.2" r="1.27"/>
</g>
<path d="M198.1 30.5h20.3v15.2h-20.3z" fill="#ffffc2"/>
<path d="M198.1 30.5h20.3v15.2h-20.3z" fill="none" stroke="#800000" stroke-width=".18"/>
<g fill="none" stroke="#840000" stroke-width=".18">
<path d="M188 33v2.6M190.5 33h7.6M218.4 33h7.7M218.4 38.1h7.7M233.7 35.6v2.5M218.4 43.2h7.7M226.1 48.3h.1M233.7 43.2v2.5M254 76.2v2.5M264.2 76.2v2.5M254 86.4h.1M254 83.8v2.6"/>
<path d="M264.2 86.4h.1M264.2 83.8v2.6M246.4 114.3v2M246.4 124.5h.1M246.4 122.5v2M81.3 157.5h7.6M81.3 152.4h7.6M81.3 147.3h7.6M81.3 149.9h7.6M81.3 154.9h7.6M208.3 157.5h7.6M208.3 152.4h7.6"/>
<path d="M231.1 157.5h7.7M241.3 154.9v2.6M81.3 160h7.6M193 170.2h.1M193 160v2M193 168.2v2M200.7 170.2h.1M200.7 160v2.6M200.7 167.6v2.6M208.3 162.6h7.6M231.1 162.6h7.7M238.4 162.2l.7 .7"/>
<path d="M239.1 162.2l-.7 .7"/>
</g>
<g fill="none" stroke="#848400" stroke-width=".18">
<path d="M144.8 27.3h.6l.6 .6-.6 .7h-.6zM144.8 29.8h.6l.6 .7-.6 .6h-.6zM144.8 37.5h.6l.6 .6-.6 .6h-.6zM144.8 32.4h.6l.6 .6-.6 .7h-.6zM97.8 47.6h.6l.7 .7-.7 .6h-.6zM144.8 40.6l.6-.6 .6 .6-.6 .7zM144.8 55.2h.6l.6 .7-.6 .6h-.6zM144.8 57.8h.6l.6 .6-.6 .7h-.6zM144.8 47.6h.6l.6 .7-.6 .6h-.6zM144.8 42.5h.6l.6 .7-.6 .6h-.6zM97.8 65.4h.6l.7 .6-.7 .7h-.6zM144.8 68.6l.6-.7 .6 .7-.6 .6z"/>
<path d="M144.8 78.1h.6l.6 .6-.6 .7h-.6zM144.8 60.3h.6l.6 .7-.6 .6h-.6zM144.8 75.6h.6l.6 .6-.6 .6h-.6zM144.8 73h.6l.6 .7-.6 .6h-.6zM144.8 65.4h.6l.6 .6-.6 .7h-.6zM97.8 83.2h.6l.7 .6-.7 .7h-.6zM97.8 93.3h.6l.7 .7-.7 .6h-.6zM144.8 83.2h.6l.6 .6-.6 .7h-.6zM274.3 96.5l.7-.6 .6 .6-.6 .7zM90.2 111.1h.6l.6 .7-.6 .6h-.6zM243.8 156.8h.7l.6 .7-.6 .6h-.7zM262.9 149.2h.6l.7 .7-.7 .6h-.6z"/>
<path d="M90.2 174.6h.6l.6 .7-.6 .6h-.6zM90.2 179.7h.6l.6 .6-.6 .7h-.6zM152.4 174.6h.6l.7 .7-.7 .6h-.6zM90.2 182.2h.6l.6 .7-.6 .6h-.6z"/>
</g>
<path d="M157.1 77.9v1.8h-.3M157.8 75.4v1.8h-.3M159 72.8h.3v1.9h-.3M160.2 60.1h.3v1.9h-.3" fill="none" stroke="#000084" stroke-width=".18"/>
<path d="M176.5 12.7v185.4M241.3 12.7v48.3M176.5 61h108M12.7 134.6h55.9M68.6 134.6v-121.9M251.5 134.6v43.2M284.5 134.6h-108" fill="none" stroke="#0000c2" stroke-width=".18" stroke-dasharray="1.4 .5"/>
<path d="M61 27.9h-10.2v88.9M94 27.9h10.1M99.1 66h5M139.7 61h5.1M139.7 78.7h5.1M139.7 73.7h5.1M139.7 76.2h5.1M139.7 132.1h5.1v17.8h-5.1M91.4 175.3h12.7M139.7 175.3h12.7" fill="none" stroke="#000084" stroke-width=".25"/>
<g fill="none" stroke="#008400" stroke-width=".18">
<path d="M30.5 30.5h5.1v96.5M30.5 38.1h5.1M50.8 30.5l-2.5 2.5h-17.8M50.8 38.1l-2.5 2.5h-17.8M50.8 33l-2.5 2.6h-17.8M94 38.1h10.1M139.7 33h5.1M139.7 27.9h5.1M139.7 38.1h5.1M139.7 30.5h5.1M180.3 33h10.2M228.6 33v5.1h-2.5"/>
<path d="M233.7 33v2.6M236.2 30.5v2.5h-10.1M246.4 33h7.6M246.4 38.1h7.6M264.2 33h2.5M264.2 38.1h2.5M276.9 38.1h2.5v2.5M30.5 45.7h5.1M30.5 53.3h5.1M50.8 55.9l-2.5 2.5h-17.8M50.8 40.6l-2.5 2.6h-17.8M50.8 45.7l-2.5 2.6h-17.8"/>
<path d="M50.8 53.3l-2.5 2.6h-17.8M50.8 48.3l-2.5 2.5h-17.8M99.1 48.3h5M139.7 58.4h5.1M139.7 40.6h5.1M139.7 43.2h5.1M139.7 48.3h5.1M139.7 55.9h5.1M226.1 43.2v5.1M233.7 45.7v2.6M246.4 43.2h7.6v5.1M266.7 43.2h-2.5v5.1"/>
<path d="M30.5 76.2h5.1M30.5 68.6h5.1M30.5 61h5.1M50.8 68.6l-2.5 2.5h-17.8M50.8 78.7l-2.5 2.6h-17.8M50.8 71.1l-2.5 2.6h-17.8M50.8 61l-2.5 2.5h-17.8M50.8 63.5l-2.5 2.5h-17.8M50.8 76.2l-2.5 2.5h-17.8M139.7 68.6h5.1M139.7 66h5.1M246.4 73.7v10.1"/>
<path d="M254 73.7v2.5M264.2 73.7v2.5M274.3 71.1v2.6h-35.5v15.2h-2.6M30.5 91.4h5.1M30.5 83.8h5.1M30.5 99.1h5.1M50.8 83.8l-2.5 2.6h-17.8M50.8 86.4l-2.5 2.5h-17.8M50.8 99.1l-2.5 2.5h-17.8M50.8 91.4l-2.5 2.6h-17.8M50.8 94l-2.5 2.5h-17.8M99.1 83.8h5"/>
<path d="M99.1 94h5M139.7 83.8h5.1M139.7 88.9h15.2M139.7 99.1h15.2M139.7 96.5h15.2M182.9 94h15.2v-2.6h10.2v2.6h2.5M182.9 99.1h15.2v2.5h10.2v-2.5h2.5M236.2 96.5h17.8M246.4 94v7.6M264.2 96.5h10.1M269.2 96.5v10.2h-33M30.5 114.3h5.1"/>
<path d="M30.5 106.7h5.1M50.8 106.7l-2.5 2.5h-17.8M50.8 109.2l-2.5 2.6h-17.8M50.8 114.3l-2.5 2.5h-17.8M50.8 116.8l-2.5 2.6h-17.8M50.8 101.6l-2.5 2.5h-17.8M91.4 111.8h12.7M91.4 106.7h12.7M91.4 104.1h12.7M139.7 114.3h22.9M139.7 111.8h22.9M139.7 116.8h22.9"/>
<path d="M139.7 106.7h15.2M139.7 104.1h15.2M144.8 111.8v7.6M149.9 114.3v5.1M154.9 116.8v2.6M182.9 109.2h27.9M182.9 104.1h27.9M236.2 111.8h33M236.2 119.4h2.6v5.1M236.2 101.6h28M246.4 111.8v2.5M254 101.6v12.7"/>
<path d="M259.1 111.8v2.5M30.5 121.9h5.1M30.5 124.5h5.1M139.7 129.5h7.6v17.8h-7.6M88.9 152.4h15.2M88.9 157.5h7.6v2.5M88.9 147.3h15.2M88.9 154.9h15.2M88.9 149.9h15.2M91.4 144.8v15.2h-2.5M180.3 157.5h28M193 157.5v2.5"/>
<path d="M198.1 149.9v2.5h10.2M200.7 152.4v7.6M238.8 157.5h5M264.2 149.9h2.5M266.7 152.4h-2.5v2.5M208.3 162.6v7.6M264.2 167.6h2.5M266.7 165.1h-2.5v5.1M91.4 182.9h12.7M91.4 180.3h12.7"/>
</g>
<g fill="none" stroke="#0000c2" stroke-width=".38">
<path d="M15.9 15.1v1.5M17 15.1v1.5M23.7 15.1v1.9M24.7 15.3a.65 .65 0 0 1 1 0M28.1 16h.6M29 15.1h-.9v1.9M29.7 15.1v1.6M32.5 15.1v1.6M35 16h.6M35.9 15.1h-.9v1.9M36.6 15.1v1.6M43.3 15.2a.66 .66 0 0 0-1 .1"/>
<path d="M43.3 16.8a.67 .67 0 0 1-.8 .1M52.6 15.1v1.6M72.7 15.1h-.9v1.9M74.5 15.2l-.3-.1h-.7v1.9M76.4 15.2a.69 .69 0 0 0-.9 .1M77 17l.6-1.9 .7 1.9M179.5 17l.6-1.9 .7 1.9M181.4 15.1v1.6M190.6 15.3a.65 .65 0 0 1 1.1 0M196.8 15.2a.77 .77 0 0 0-.9 0 .77 .77 0 0 0-.3 .9l.2 .6M197.6 15.1v1.6M202 15.1v1.9"/>
<path d="M245.5 15.2l-.7-.1-.3 .1M246.4 15.1v1.6M249.2 15.1v1.6M255 15.1v1.9M257.4 15.1h-.9v1.9M259.1 15.3l-.4-.2h-.5v1.9M180.8 63.4l-.8-.1-.2 .2M187.8 63.3v1.9M189.1 63.3l.7 1.9 .6-1.9M191.9 63.6l-.4-.3h-.5v1.9M193.9 63.4l-.7-.1-.3 .2M195.9 63.3h1.1"/>
<path d="M196.5 63.3v1.9M207.1 63.3l-.1 .1 .1 .1M207.1 63.3l.1 .1-.1 .1M207.1 63.3v.2M180.8 137.2l-.3-.2h-.7v1.9M184.6 137v1.9M190.5 137.2a.66 .66 0 0 0-1 .1M203.9 137v1.6M205 137l-.1 .1 .1 .1M205 137l.1 .1-.1 .1M205 137v.2M255.7 137.1l-.7-.1-.3 .2"/>
<path d="M259.4 137l-.1 .1 .1 .1M259.4 137l.1 .1-.1 .1M259.4 137v.2M266.3 137.2a.66 .66 0 0 0-1 .1M275.6 137v1.6"/>
</g>
<path d="M74.7 156.3v.5M75.5 156.3l-.2 .3h-1.1" fill="none" stroke="#0000c2" stroke-width=".18"/>
<path d="M93 140.3h.7l-.4 .5M93.5 140.8l.2 .2v.3l-.2 .2M242 151.6h.8M230 165.7h.8l-.5 1.2" fill="none" stroke="#008484" stroke-width=".18"/>
<g fill="#008400" stroke="#008400" stroke-width=".18">
<circle cx="35.6" cy="38.1" r=".46"/>
<circle cx="35.6" cy="83.8" r=".46"/>
<circle cx="35.6" cy="61" r=".46"/>
<circle cx="35.6" cy="76.2" r=".46"/>
<circle cx="35.6" cy="68.6" r=".46"/>
<circle cx="35.6" cy="45.7" r=".46"/>
<circle cx="35.6" cy="53.3" r=".46"/>
<circle cx="35.6" cy="121.9" r=".46"/>
<circle cx="35.6" cy="114.3" r=".46"/>
<circle cx="35.6" cy="106.7" r=".46"/>
<circle cx="35.6" cy="124.5" r=".46"/>
<circle cx="35.6" cy="91.4" r=".46"/>
<circle cx="35.6" cy="99.1" r=".46"/>
<circle cx="264.2" cy="43.2" r=".46"/>
<circle cx="254" cy="43.2" r=".46"/>
<circle cx="264.2" cy="73.7" r=".46"/>
<circle cx="228.6" cy="33" r=".46"/>
<circle cx="188" cy="33" r=".46"/>
<circle cx="203.2" cy="101.6" r=".46"/>
<circle cx="193" cy="157.5" r=".46"/>
<circle cx="154.9" cy="116.8" r=".46"/>
<circle cx="203.2" cy="91.4" r=".46"/>
<circle cx="241.3" cy="157.5" r=".46"/>
<circle cx="200.7" cy="152.4" r=".46"/>
<circle cx="254" cy="101.6" r=".46"/>
<circle cx="269.2" cy="96.5" r=".46"/>
<circle cx="246.4" cy="73.7" r=".46"/>
<circle cx="254" cy="73.7" r=".46"/>
<circle cx="233.7" cy="33" r=".46"/>
<circle cx="259.1" cy="111.8" r=".46"/>
<circle cx="246.4" cy="111.8" r=".46"/>
<circle cx="246.4" cy="101.6" r=".46"/>
<circle cx="264.2" cy="167.6" r=".46"/>
<circle cx="149.9" cy="114.3" r=".46"/>
<circle cx="144.8" cy="111.8" r=".46"/>
<circle cx="96.5" cy="111.8" r=".46"/>
</g>
<use href="#words"/>
</svg>
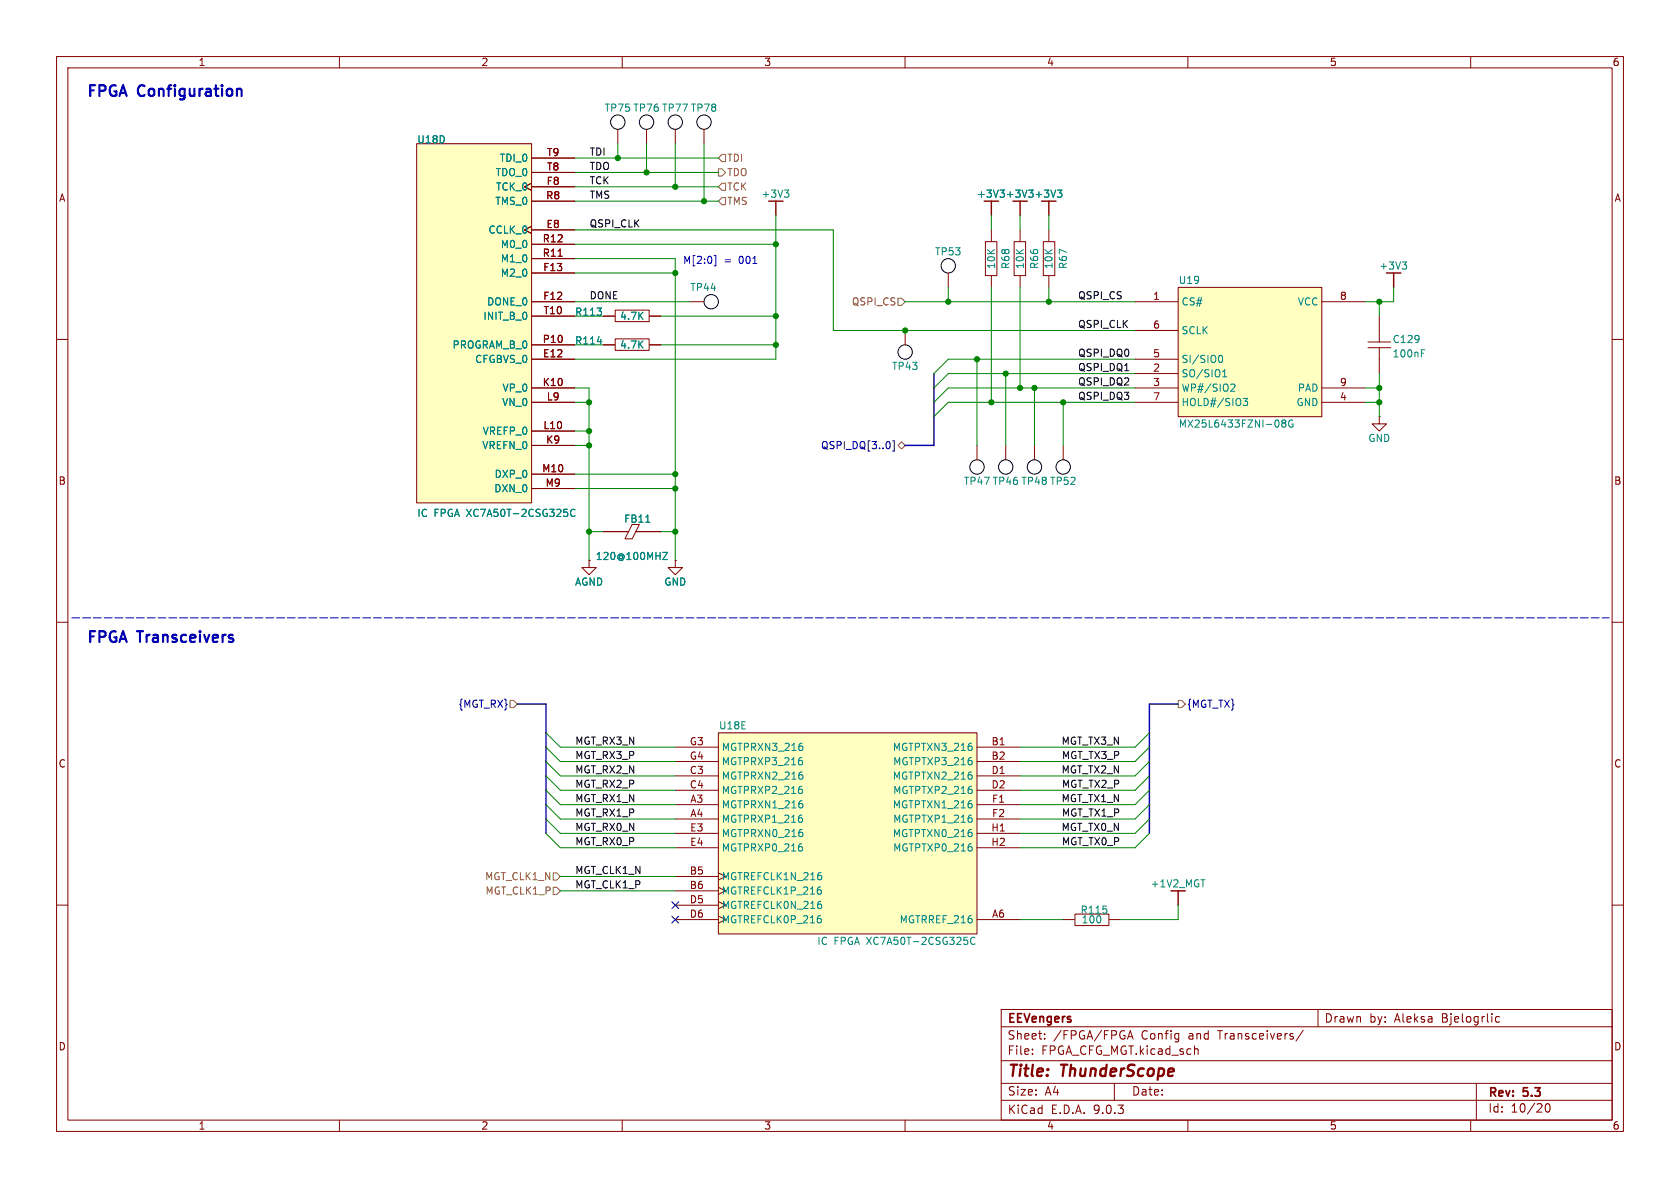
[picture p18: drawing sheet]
<svg xmlns="http://www.w3.org/2000/svg" width="297mm" height="210mm" viewBox="0 0 297 210" stroke-linecap="round" stroke-linejoin="round" font-family="sans-serif">
<defs><g id="words">
<g font-size="2.8" fill="#840000">
<text x="178" y="190.9">Title:</text>
<text x="187.7" y="190.9">ThunderScope</text>
</g>
<g font-size="2.7" fill="#0000c2">
<text x="15.2" y="18">FPGA</text>
<text x="24.5" y="18">Configuration</text>
<text x="15.2" y="114.6">FPGA</text>
<text x="24.5" y="114.6">Transceivers</text>
</g>
<g font-size="2.1" fill="#840000">
<text x="178" y="184">Sheet:</text>
<text x="178" y="181.2">EEVengers</text>
<text x="186.2" y="184">/FPGA/FPGA</text>
<text x="201.8" y="184">Config</text>
<text x="210.3" y="184">and</text>
<text x="215.6" y="184">Transceivers/</text>
<text x="234.1" y="181">Drawn</text>
<text x="242.1" y="181">by:</text>
<text x="246.6" y="181">Aleksa</text>
<text x="255" y="181">Bjelogrlic</text>
<text x="178" y="186.7">File:</text>
<text x="184.1" y="186.7">FPGA_CFG_MGT.kicad_sch</text>
<text x="178.1" y="197.1">KiCad</text>
<text x="178.1" y="193.9">Size:</text>
<text x="184.7" y="193.9">A4</text>
<text x="185.8" y="197.1">E.D.A.</text>
<text x="193.4" y="197.1">9.0.3</text>
<text x="200" y="193.9">Date:</text>
<text x="263" y="194.3">Rev:</text>
<text x="263" y="196.9">Id:</text>
<text x="267.1" y="196.9">10/20</text>
<text x="269.4" y="194.3">5.3</text>
</g>
<g font-size="1.8" fill="#840000">
<text x="35" y="11.9">1</text>
<text x="85" y="11.9">2</text>
<text x="135" y="11.9">3</text>
<text x="185" y="11.9">4</text>
<text x="235" y="11.9">5</text>
<text x="285" y="11.9">6</text>
<text x="96.6" y="27.7">T9</text>
<text x="10.3" y="35.9">A</text>
<text x="96.4" y="35.3">R8</text>
<text x="96.5" y="32.8">F8</text>
<text x="96.6" y="30.2">T8</text>
<text x="285.3" y="35.9">A</text>
<text x="96.5" y="40.4">E8</text>
<text x="95.8" y="42.9">R12</text>
<text x="95.8" y="45.5">R11</text>
<text x="95.9" y="48">F13</text>
<text x="95.9" y="53.1">F12</text>
<text x="203.8" y="53.1">1</text>
<text x="236.8" y="53.1">8</text>
<text x="96" y="55.6">T10</text>
<text x="203.8" y="58.2">6</text>
<text x="95.8" y="60.7">P10</text>
<text x="95.9" y="63.2">E12</text>
<text x="203.8" y="63.2">5</text>
<text x="203.8" y="65.8">2</text>
<text x="95.8" y="68.3">K10</text>
<text x="96.6" y="70.9">L9</text>
<text x="203.8" y="68.3">3</text>
<text x="203.8" y="70.9">7</text>
<text x="236.8" y="68.3">9</text>
<text x="236.8" y="70.9">4</text>
<text x="96" y="75.9">L10</text>
<text x="95.8" y="83.6">M10</text>
<text x="96.4" y="78.5">K9</text>
<text x="10.3" y="85.9">B</text>
<text x="96.4" y="86.1">M9</text>
<text x="285.3" y="85.9">B</text>
<text x="121.8" y="131.8">G3</text>
<text x="175.2" y="131.8">B1</text>
<text x="10.3" y="135.9">C</text>
<text x="121.8" y="136.9">C3</text>
<text x="121.8" y="134.4">G4</text>
<text x="175.2" y="136.9">D1</text>
<text x="175.2" y="134.4">B2</text>
<text x="285.3" y="135.9">C</text>
<text x="121.8" y="139.4">C4</text>
<text x="121.9" y="142">A3</text>
<text x="175.2" y="139.4">D2</text>
<text x="175.3" y="142">F1</text>
<text x="121.9" y="149.6">E4</text>
<text x="121.9" y="147.1">E3</text>
<text x="121.9" y="144.5">A4</text>
<text x="175.2" y="149.6">H2</text>
<text x="175.2" y="147.1">H1</text>
<text x="175.3" y="144.5">F2</text>
<text x="121.8" y="154.7">B5</text>
<text x="121.8" y="159.8">D5</text>
<text x="121.8" y="157.2">B6</text>
<text x="121.8" y="162.3">D6</text>
<text x="175.3" y="162.3">A6</text>
<text x="10.3" y="185.9">D</text>
<text x="285.3" y="185.9">D</text>
<text x="35" y="199.9">1</text>
<text x="85" y="199.9">2</text>
<text x="135" y="199.9">3</text>
<text x="185" y="199.9">4</text>
<text x="235" y="199.9">5</text>
<text x="285" y="199.9">6</text>
</g>
<g font-size="1.8" fill="#008484">
<text x="106.8" y="20">TP75 TP76 TP77 TP78</text>
<text x="73.7" y="25.5">U18D</text>
<text x="88.2" y="28.8">TDI_0</text>
<text x="87.5" y="31.3">TDO_0</text>
<text x="87.6" y="33.9">TCK_0</text>
<text x="134.5" y="35.2">+3V3</text>
<text x="172.6" y="35.2">+3V3 +3V3 +3V3</text>
<text x="86.3" y="41.5">CCLK_0</text>
<text x="87.5" y="36.4">TMS_0</text>
<text x="88.4" y="44">M0_0</text>
<text x="88.4" y="46.6">M1_0</text>
<text x="165.2" y="45.4">TP53</text>
<text x="176.1" y="47.7" transform="rotate(-90 176.1 47.7)">10K</text>
<text x="178.7" y="47.7" transform="rotate(-90 178.7 47.7)">R68</text>
<text x="181.2" y="47.7" transform="rotate(-90 181.2 47.7)">10K</text>
<text x="183.7" y="47.7" transform="rotate(-90 183.7 47.7)">R66</text>
<text x="186.3" y="47.7" transform="rotate(-90 186.3 47.7)">10K</text>
<text x="188.8" y="47.7" transform="rotate(-90 188.8 47.7)">R67</text>
<text x="243.7" y="47.9">+3V3</text>
<text x="88.4" y="49.1">M2_0</text>
<text x="121.9" y="51.7">TP44</text>
<text x="208.3" y="50.4">U19</text>
<text x="85.3" y="56.7">INIT_B_0</text>
<text x="86" y="54.2">DONE_0</text>
<text x="101.6" y="56">R113</text>
<text x="109.5" y="56.7">4.7K</text>
<text x="208.8" y="54.2">CS#</text>
<text x="208.8" y="59.3">SCLK</text>
<text x="229.3" y="54.2">VCC</text>
<text x="79.9" y="61.8">PROGRAM_B_0</text>
<text x="83.9" y="64.4">CFGBVS_0</text>
<text x="101.6" y="61.1">R114</text>
<text x="109.5" y="61.8">4.7K</text>
<text x="157.6" y="65.6">TP43</text>
<text x="208.8" y="64.4">SI/SIO0</text>
<text x="246.1" y="60.8">C129</text>
<text x="246.1" y="63.4">100nF</text>
<text x="88.7" y="72">VN_0</text>
<text x="88.7" y="69.4">VP_0</text>
<text x="208.8" y="66.9">SO/SIO1</text>
<text x="208.8" y="69.4">WP#/SIO2</text>
<text x="208.8" y="72">HOLD#/SIO3</text>
<text x="229.1" y="72">GND</text>
<text x="229.3" y="69.4">PAD</text>
<text x="85.2" y="77.1">VREFP_0</text>
<text x="208.3" y="75.8">MX25L6433FZNI-08G</text>
<text x="85.2" y="79.6">VREFN_0</text>
<text x="241.8" y="78.3">GND</text>
<text x="87.3" y="87.2">DXN_0</text>
<text x="87.3" y="84.7">DXP_0</text>
<text x="170.3" y="85.9">TP47 TP46 TP48 TP52</text>
<text x="73.7" y="91.6">IC</text>
<text x="76.7" y="91.6">FPGA XC7A50T-2CSG325C</text>
<text x="110.2" y="92.6">FB11</text>
<text x="105.2" y="99.2">120@100MHZ</text>
<text x="101.6" y="103.7">AGND</text>
<text x="117.3" y="103.7">GND</text>
<text x="127" y="129.1">U18E</text>
<text x="127.5" y="135.5">MGTPRXP3_216</text>
<text x="127.5" y="132.9">MGTPRXN3_216</text>
<text x="157.7" y="132.9">MGTPTXN3_216</text>
<text x="157.8" y="135.5">MGTPTXP3_216</text>
<text x="127.5" y="143.1">MGTPRXN1_216</text>
<text x="127.5" y="140.6">MGTPRXP2_216</text>
<text x="127.5" y="138">MGTPRXN2_216</text>
<text x="157.7" y="143.1">MGTPTXN1_216</text>
<text x="157.7" y="138">MGTPTXN2_216</text>
<text x="157.8" y="140.6">MGTPTXP2_216</text>
<text x="127.5" y="148.2">MGTPRXN0_216</text>
<text x="127.5" y="145.6">MGTPRXP1_216</text>
<text x="157.7" y="148.2">MGTPTXN0_216</text>
<text x="157.8" y="145.6">MGTPTXP1_216</text>
<text x="127.5" y="155.8">MGTREFCLK1N_216</text>
<text x="127.5" y="150.7">MGTPRXP0_216</text>
<text x="157.8" y="150.7">MGTPTXP0_216</text>
<text x="127.5" y="160.9">MGTREFCLK0N_216</text>
<text x="127.5" y="158.3">MGTREFCLK1P_216</text>
<text x="190.9" y="161.7">R115</text>
<text x="203.3" y="157.1">+1V2_MGT</text>
<text x="127.5" y="163.4">MGTREFCLK0P_216</text>
<text x="144.4" y="167.2">IC</text>
<text x="147.4" y="167.2">FPGA XC7A50T-2CSG325C</text>
<text x="158.9" y="163.4">MGTRREF_216</text>
<text x="191.1" y="163.4">100</text>
</g>
<g font-size="1.8">
<text x="104.1" y="27.6">TDI</text>
<text x="104.1" y="32.7">TCK</text>
<text x="104.1" y="30.1">TDO</text>
<text x="104.1" y="35.2">TMS</text>
<text x="104.1" y="40.3">QSPI_CLK</text>
<text x="104.1" y="53">DONE</text>
<text x="190.5" y="53">QSPI_CS</text>
<text x="190.5" y="58.1">QSPI_CLK</text>
<text x="190.5" y="65.7">QSPI_DQ1</text>
<text x="190.5" y="63.2">QSPI_DQ0</text>
<text x="190.5" y="68.2">QSPI_DQ2</text>
<text x="190.5" y="70.8">QSPI_DQ3</text>
<text x="101.6" y="131.7">MGT_RX3_N</text>
<text x="187.6" y="131.7">MGT_TX3_N</text>
<text x="101.6" y="136.8">MGT_RX2_N</text>
<text x="101.6" y="134.3">MGT_RX3_P</text>
<text x="187.6" y="136.8">MGT_TX2_N</text>
<text x="187.6" y="134.3">MGT_TX3_P</text>
<text x="101.6" y="141.9">MGT_RX1_N</text>
<text x="101.6" y="139.4">MGT_RX2_P</text>
<text x="187.6" y="141.9">MGT_TX1_N</text>
<text x="187.6" y="139.4">MGT_TX2_P</text>
<text x="101.6" y="147">MGT_RX0_N</text>
<text x="101.6" y="144.4">MGT_RX1_P</text>
<text x="101.6" y="149.5">MGT_RX0_P</text>
<text x="187.6" y="147">MGT_TX0_N</text>
<text x="187.6" y="149.5">MGT_TX0_P</text>
<text x="187.6" y="144.4">MGT_TX1_P</text>
<text x="101.6" y="154.6">MGT_CLK1_N</text>
<text x="101.6" y="157.1">MGT_CLK1_P</text>
</g>
<g font-size="1.8" fill="#848400">
<text x="128.5" y="28.8">TDI</text>
<text x="128.5" y="33.9">TCK</text>
<text x="128.5" y="31.3">TDO</text>
<text x="128.5" y="36.4">TMS</text>
<text x="150.5" y="54.2">QSPI_CS</text>
<text x="85.7" y="155.8">MGT_CLK1_N</text>
<text x="85.7" y="158.3">MGT_CLK1_P</text>
</g>
<g font-size="1.8" fill="#0000c2">
<text x="120.6" y="46.7">M[2:0]</text>
<text x="128" y="46.7">=</text>
<text x="130.7" y="46.7">001</text>
</g>
<g font-size="1.8" fill="#000084">
<text x="145.1" y="79.6">QSPI_DQ[3..0]</text>
<text x="80.9" y="125.3">{MGT_RX}</text>
<text x="209.7" y="125.3">{MGT_TX}</text>
</g>
</g></defs>
<path d="M0 0h297v210h-297z" fill="#fff" stroke="#fff" stroke-width=".18"/>
<g fill="none" stroke="#840000" stroke-width=".18">
<path d="M10 10h277v190h-277zM12 12h273v186h-273zM60 10v2M110 10v2M160 10v2M210 10v2M260 10v2M109.2 22.9v2.5M119.4 22.9v2.5M124.5 22.9v2.5M121.9 53.3h2.6M160 58.4v2.6"/>
<path d="M10 60h2M177.8 78.7v2.6M182.9 78.7v2.6M243.8 73.7v1.2h1.3l-1.3 1.3-1.2-1.3h1.2M243.8 73.7h.1M285 60h2M119.4 99.1v1.2h1.2l-1.2 1.3-1.3-1.3h1.3M119.4 99.1h.1M10 110h2M285 110h2M10 160h2M177 178.5h108v19.5h-108z"/>
<path d="M233 178.5v3M265.1 179.8l-.4-.1-.3 .3v.4l.1 .2h.6M285 160h2M60 198v2M110 198v2M160 198v2M177 194.5h108M177 191.5h108M177 187.5h108M177 181.5h108M182.5 186.3v.1M182.5 185.5v.1"/>
<path d="M184.7 183.6v.1M184.7 182.8v.1M197 191.5v3M199.3 183.7l.5-1.5 .5 1.5M199.5 183.3h.7M210 198v2M211.6 185.4l.2 .2v.8M230.4 182.1l-1.3 2M260 198v2M261 191.5v6.5M273.3 195.2l.2-.1a.81 .81 0 0 1 .6 .6 .81 .81 0 0 1-.3 .8l-.1 .1a.81 .81 0 0 1-.4-1.4z"/>
</g>
<path d="M137.2 35.6v2.5M246.4 48.3v2.5" fill="none" stroke="#840000" stroke-width=".25"/>
<path d="M138.7 33.6h.8l-.5 .5M139.2 34.1l.3 .2v.3l-.3 .3M247.9 46.3h.8l-.4 .5M248.4 46.8l.3 .2v.3l-.3 .3" fill="none" stroke="#008484" stroke-width=".18"/>
<g fill="none" stroke="#000" stroke-width=".18">
<circle cx="109.2" cy="21.6" r="1.27"/>
<circle cx="119.4" cy="21.6" r="1.27"/>
<circle cx="124.5" cy="21.6" r="1.27"/>
<circle cx="125.7" cy="53.3" r="1.27"/>
<circle cx="160" cy="62.2" r="1.27"/>
<circle cx="177.8" cy="82.5" r="1.27"/>
<circle cx="182.9" cy="82.5" r="1.27"/>
</g>
<path d="M73.7 25.4h20.3v63.5h-20.3z" fill="#ffffc2"/>
<path d="M73.7 25.4h20.3v63.5h-20.3z" fill="none" stroke="#800000" stroke-width=".18"/>
<g fill="none" stroke="#840000" stroke-width=".18">
<path d="M94 32.4l-1.3 .6 1.3 .7M94 27.9h7.6M94 30.5h7.6M94 33h7.6M94 35.6h7.6M114.3 22.9v2.5M94 40l-1.3 .6 1.3 .7M94 40.6h7.6M94 43.2h7.6M94 45.7h7.6M94 48.3h7.6M94 53.3h7.6"/>
<path d="M94 55.9h7.6M98.7 45.3h.7M94 61h7.6M94 63.5h7.6M94 68.6h7.6M94 71.1h7.6M94 76.2h7.6M94 78.7h7.6M188 78.7v2.6M94 83.8h7.6M94 86.4h7.6M188 162.6h2"/>
<path d="M190 161.6h6v2h-6zM196.1 162.6h2"/>
</g>
<path d="M101.7 90.1a.6 .6 0 0 0-.9 .5 .6 .6 0 0 0 .6 .7l.3-.1" fill="none" stroke="#008484" stroke-width=".18"/>
<g fill="none" stroke="#000" stroke-width=".18">
<circle cx="114.3" cy="21.6" r="1.27"/>
<circle cx="188" cy="82.5" r="1.27"/>
</g>
<path d="M127 129.5h45.7v35.6h-45.7z" fill="#ffffc2"/>
<path d="M127 129.5h45.7v35.6h-45.7z" fill="none" stroke="#800000" stroke-width=".18"/>
<g fill="none" stroke="#840000" stroke-width=".18">
<path d="M167.6 48.3v2.5M174.2 42.7h2v6h-2zM175.3 40.6v2M175.3 48.8v2M179.3 42.7h2v6h-2zM180.3 40.6v2M180.3 48.8v2M184.4 42.7h2.1v6h-2.1zM185.4 40.6v2M185.4 48.8v2M243.8 55.9v4.6M241.8 60.5h4"/>
<path d="M241.8 61.5h4M243.8 61.5v4.5M106.7 94h4.4M111.8 92.7h1.2l-1.2 2.6h-1.3zM112.4 94h4.4M119.4 139.7h7.6M119.4 137.2h7.6M119.4 134.6h7.6M119.4 132.1h7.6M172.7 139.7h7.6M172.7 137.2h7.6M172.7 134.6h7.6"/>
<path d="M172.7 132.1h7.6M119.4 149.9h7.6M119.4 147.3h7.6M119.4 144.8h7.6M119.4 142.2h7.6M119.4 157.5h7.6M119.4 154.9h7.6M127 159.4l1.3 .6-1.3 .7M127 156.8l1.3 .7-1.3 .6M127 154.3l1.3 .6-1.3 .7M172.7 149.9h7.6M172.7 147.3h7.6"/>
<path d="M172.7 144.8h7.6M172.7 142.2h7.6M119.4 162.6h7.6M119.4 160h7.6M127 161.9l1.3 .7-1.3 .6M172.7 162.6h7.6"/>
</g>
<g fill="none" stroke="#008484" stroke-width=".18">
<path d="M186.9 33.6h.8l-.4 .5M187.5 34.1l.2 .2v.3l-.2 .3M251.3 62.4h.4M251.3 61.8h.6M114.2 92.3h.7M117.2 97.6h.8l-.8 1.3h.8M141.5 139h.3M141.5 133.9h.3M141.6 134.4l.3 .3v.3l-.3 .2M141.6 139.5l.3 .2v.3l-.3 .3M141.8 131.9l.1 .2-.1 .5M141.8 137l.1 .2-.1 .5"/>
<path d="M171.8 132v.5M171.8 134.5v.6M171.8 137.1v.5M171.8 139.6v.6M141.5 149.2h.3M141.5 144.1h.3M141.6 149.7l.3 .2v.3l-.3 .2M141.6 144.6l.3 .2v.3l-.3 .3M141.8 147.2l.1 .2-.1 .4M141.8 142.1l.1 .2-.1 .5M144.8 156.8h.3M145 157.3l.2 .2v.3l-.2 .3"/>
<path d="M145.1 159.9l.2 .2-.2 .4M145.1 154.8l.2 .2-.2 .5M171.8 149.8v.5M171.8 142.2v.5M171.8 144.7v.5M171.8 147.2v.6M212.3 155.5h.7M144.8 161.9h.3M145 162.4l.2 .2v.3l-.2 .2M172.4 165.8a.6 .6 0 0 0-.9 .4 .6 .6 0 0 0 .6 .7l.3-.1"/>
</g>
<path d="M175.3 35.6v2.5M180.3 35.6v2.5M185.4 35.6v2.5M208.3 157.5v2.5" fill="none" stroke="#840000" stroke-width=".25"/>
<circle cx="167.6" cy="47" r="1.27" fill="none" stroke="#000" stroke-width=".18"/>
<path d="M208.3 50.8h25.4v22.9h-25.4z" fill="#ffffc2"/>
<path d="M208.3 50.8h25.4v22.9h-25.4z" fill="none" stroke="#800000" stroke-width=".18"/>
<g fill="none" stroke="#840000" stroke-width=".18">
<path d="M94 32.4l-1.3 .6 1.3 .7M94 27.9h7.6M94 30.5h7.6M94 33h7.6M94 35.6h7.6M94 40l-1.3 .6 1.3 .7M94 53.3h7.6M94 55.9h7.6M94 40.6h7.6M94 43.2h7.6M94 45.7h7.6M94 48.3h7.6"/>
<path d="M98.7 45.3h.7M106.7 55.9h2M108.8 54.8h6v2.1h-6zM108.8 59.9h6v2h-6zM114.8 55.9h2M200.7 53.3h7.6M200.7 58.4h7.6M233.7 53.3h7.6M94 63.5h7.6M94 68.6h7.6M94 71.1h7.6M94 61h7.6"/>
<path d="M94 76.2h7.6M94 78.7h7.6M106.7 61h2M114.8 61h2M172.7 78.7v2.6M200.7 63.5h7.6M200.7 66h7.6M200.7 68.6h7.6M200.7 71.1h7.6M233.7 68.6h7.6M233.7 71.1h7.6M94 83.8h7.6"/>
<path d="M94 86.4h7.6M104.1 99.1v1.2h1.3l-1.3 1.3-1.2-1.3h1.2M104.1 99.1h.1M106.7 94h4.4M112.4 94h4.4M119.4 99.1h.1"/>
</g>
<g fill="none" stroke="#008484" stroke-width=".18">
<path d="M186.9 33.6h.8l-.4 .5M187.5 34.1l.2 .2v.3l-.2 .3M105.6 60.4h.8M215.5 63.1l.2-.3a.68 .68 0 0 1 .5 .6 .68 .68 0 0 1-.5 .7l-.2-.3M216.1 66.6h.8M216.1 65.7l.4-.4v1.3M217.7 68l.4-.1 .2 .4-.8 .9h.8M219.8 70.4h.8l-.5 .5 .4 .1v.6l-.2 .1-.5-.1M226.8 74.8l-.2-.3 .2-.3h.3l.2 .3-.2 .3M226.8 74.8l-.2 .2 .1 .4 .1 .1 .4-.1 .1-.1v-.3l-.2-.2M226.8 74.8h.3M228.5 74.3a.59 .59 0 0 0-.7 .6 .59 .59 0 0 0 .7 .5l.1-.4h-.3"/>
<path d="M101.7 90.1a.6 .6 0 0 0-.9 .5 .6 .6 0 0 0 .6 .7l.3-.1M114.2 92.3h.7M117.2 97.6h.8l-.8 1.3h.8"/>
</g>
<circle cx="172.7" cy="82.5" r="1.27" fill="none" stroke="#000" stroke-width=".18"/>
<path d="M127 29.8h.6l.7 .7-.7 .6h-.6zM127.6 32.4h.7v1.3h-.7l-.6-.7zM127.6 27.3h.7v1.3h-.7l-.6-.7zM127.6 34.9h.7v1.3h-.7l-.6-.6zM158.7 52.7h.7l.6 .6-.6 .7h-.7zM158.7 78.7l.7-.6 .6 .6-.6 .7zM90.2 123.8h.6l.6 .7-.6 .6h-.6zM208.3 123.8h.6l.6 .7-.6 .6h-.6zM97.8 156.8h.6l.7 .7-.7 .6h-.6zM97.8 154.3h.6l.7 .6-.7 .7h-.6z" fill="none" stroke="#848400" stroke-width=".18"/>
<path d="M157.3 78.3v.8M157.8 77.9h.3v1.8h-.3M118.8 159.4l1.2 1.2M120 159.4l-1.2 1.2M118.8 162l1.2 1.2M120 162l-1.2 1.2" fill="none" stroke="#000084" stroke-width=".18"/>
<path d="M12.7 109.2h271.8" fill="none" stroke="#0000c2" stroke-width=".18" stroke-dasharray="1.4 .5"/>
<path d="M165.1 66v12.7h-5.1M91.4 124.5h5.1v22.8M208.3 124.5h-5.1v22.8" fill="none" stroke="#000084" stroke-width=".25"/>
<g fill="none" stroke="#008400" stroke-width=".18">
<path d="M101.6 27.9h25.4M101.6 30.5h25.4M101.6 35.6h25.4M101.6 33h25.4M109.2 25.4v2.5M114.3 25.4v5.1M119.4 25.4v7.6M124.5 25.4v10.2M137.2 38.1v25.4h-35.6M175.3 38.1v2.5M180.3 38.1v2.5M185.4 38.1v2.5"/>
<path d="M101.6 45.7h17.8v53.4M101.6 53.3h20.3M101.6 40.6h45.7v17.8h53.4M101.6 55.9h5.1M101.6 48.3h17.8M101.6 43.2h35.6M116.8 55.9h20.4M160 53.3h40.7M167.6 50.8v2.5M175.3 50.8v20.3M180.3 50.8v17.8M185.4 50.8v2.5"/>
<path d="M243.8 53.3v2.6M246.4 50.8v2.5h-5.1M101.6 68.6h2.5v30.5M101.6 78.7h2.5M101.6 76.2h2.5M101.6 71.1h2.5M101.6 61h5.1M116.8 61h20.4M172.7 63.5v15.2M177.8 66v12.7M182.9 68.6v10.1M188 71.1v7.6"/>
<path d="M200.7 68.6h-33.1l-2.5 2.5M200.7 71.1h-33.1l-2.5 2.6M200.7 66h-33.1l-2.5 2.6M200.7 63.5h-33.1l-2.5 2.5M241.3 68.6h2.5M241.3 71.1h2.5M243.8 66v7.7M101.6 86.4h17.8M101.6 83.8h17.8M104.1 94h2.6M116.8 94h2.6M96.5 129.5l2.6 2.6h20.3"/>
<path d="M96.5 132.1l2.6 2.5h20.3M96.5 134.6l2.6 2.6h20.3M96.5 137.2l2.6 2.5h20.3M96.5 139.7l2.6 2.5h20.3M203.2 129.5l-2.5 2.6h-20.4M203.2 132.1l-2.5 2.5h-20.4M203.2 134.6l-2.5 2.6h-20.4M203.2 137.2l-2.5 2.5h-20.4M203.2 139.7l-2.5 2.5h-20.4M96.5 147.3l2.6 2.6h20.3M96.5 144.8l2.6 2.5h20.3M96.5 142.2l2.6 2.6h20.3"/>
<path d="M99.1 154.9h20.3M99.1 157.5h20.3M203.2 147.3l-2.5 2.6h-20.4M203.2 144.8l-2.5 2.5h-20.4M203.2 142.2l-2.5 2.6h-20.4M180.3 162.6h7.7M208.3 160v2.6h-10.2"/>
</g>
<g fill="none" stroke="#0000c2" stroke-width=".38">
<path d="M16.9 15.1h-1v1.9M18.6 15.2l-.3-.1h-.7v1.9M20.5 15.2a.69 .69 0 0 0-.9 .1M21.1 17l.6-1.9 .7 1.9M25.6 15.2a.66 .66 0 0 0-1 .1M30.3 15.1l-.4 .1-.1 .1M30.9 15.1l-.1 .1h.1M30.9 15.1l.1 .1h-.1M30.9 15.1v.1M38.2 15.1v1.6M39.3 15.1l-.1 .1h.1M39.3 15.1v.1"/>
<path d="M42.6 15.8l.1 1.2M16.9 111.6h-1v1.9M18.6 111.8l-.3-.2h-.7v1.9M20.5 111.7a.69 .69 0 0 0-.9 .2M21.1 113.5l.6-1.9 .7 1.9M24.2 111.6h1.1M24.7 111.6v1.9M35.4 111.6l-.1 .1 .1 .1M35.4 111.6v.1v.1M35.4 111.6v.2"/>
</g>
<path d="M126.3 45.2h.3v1.8h-.3" fill="none" stroke="#0000c2" stroke-width=".18"/>
<g fill="#008400" stroke="#008400" stroke-width=".18">
<circle cx="114.3" cy="30.5" r=".46"/>
<circle cx="104.1" cy="71.1" r=".46"/>
<circle cx="119.4" cy="94" r=".46"/>
<circle cx="119.4" cy="48.3" r=".46"/>
<circle cx="124.5" cy="35.6" r=".46"/>
<circle cx="137.2" cy="43.2" r=".46"/>
<circle cx="119.4" cy="83.8" r=".46"/>
<circle cx="119.4" cy="86.4" r=".46"/>
<circle cx="119.4" cy="33" r=".46"/>
<circle cx="109.2" cy="27.9" r=".46"/>
<circle cx="167.6" cy="53.3" r=".46"/>
<circle cx="160" cy="58.4" r=".46"/>
<circle cx="137.2" cy="55.9" r=".46"/>
<circle cx="137.2" cy="61" r=".46"/>
<circle cx="104.1" cy="76.2" r=".46"/>
<circle cx="104.1" cy="78.7" r=".46"/>
<circle cx="104.1" cy="94" r=".46"/>
<circle cx="180.3" cy="68.6" r=".46"/>
<circle cx="172.7" cy="63.5" r=".46"/>
<circle cx="177.8" cy="66" r=".46"/>
<circle cx="185.4" cy="53.3" r=".46"/>
<circle cx="182.9" cy="68.6" r=".46"/>
<circle cx="188" cy="71.1" r=".46"/>
<circle cx="243.8" cy="53.3" r=".46"/>
<circle cx="243.8" cy="68.6" r=".46"/>
<circle cx="243.8" cy="71.1" r=".46"/>
<circle cx="175.3" cy="71.1" r=".46"/>
</g>
<use href="#words"/>
</svg>
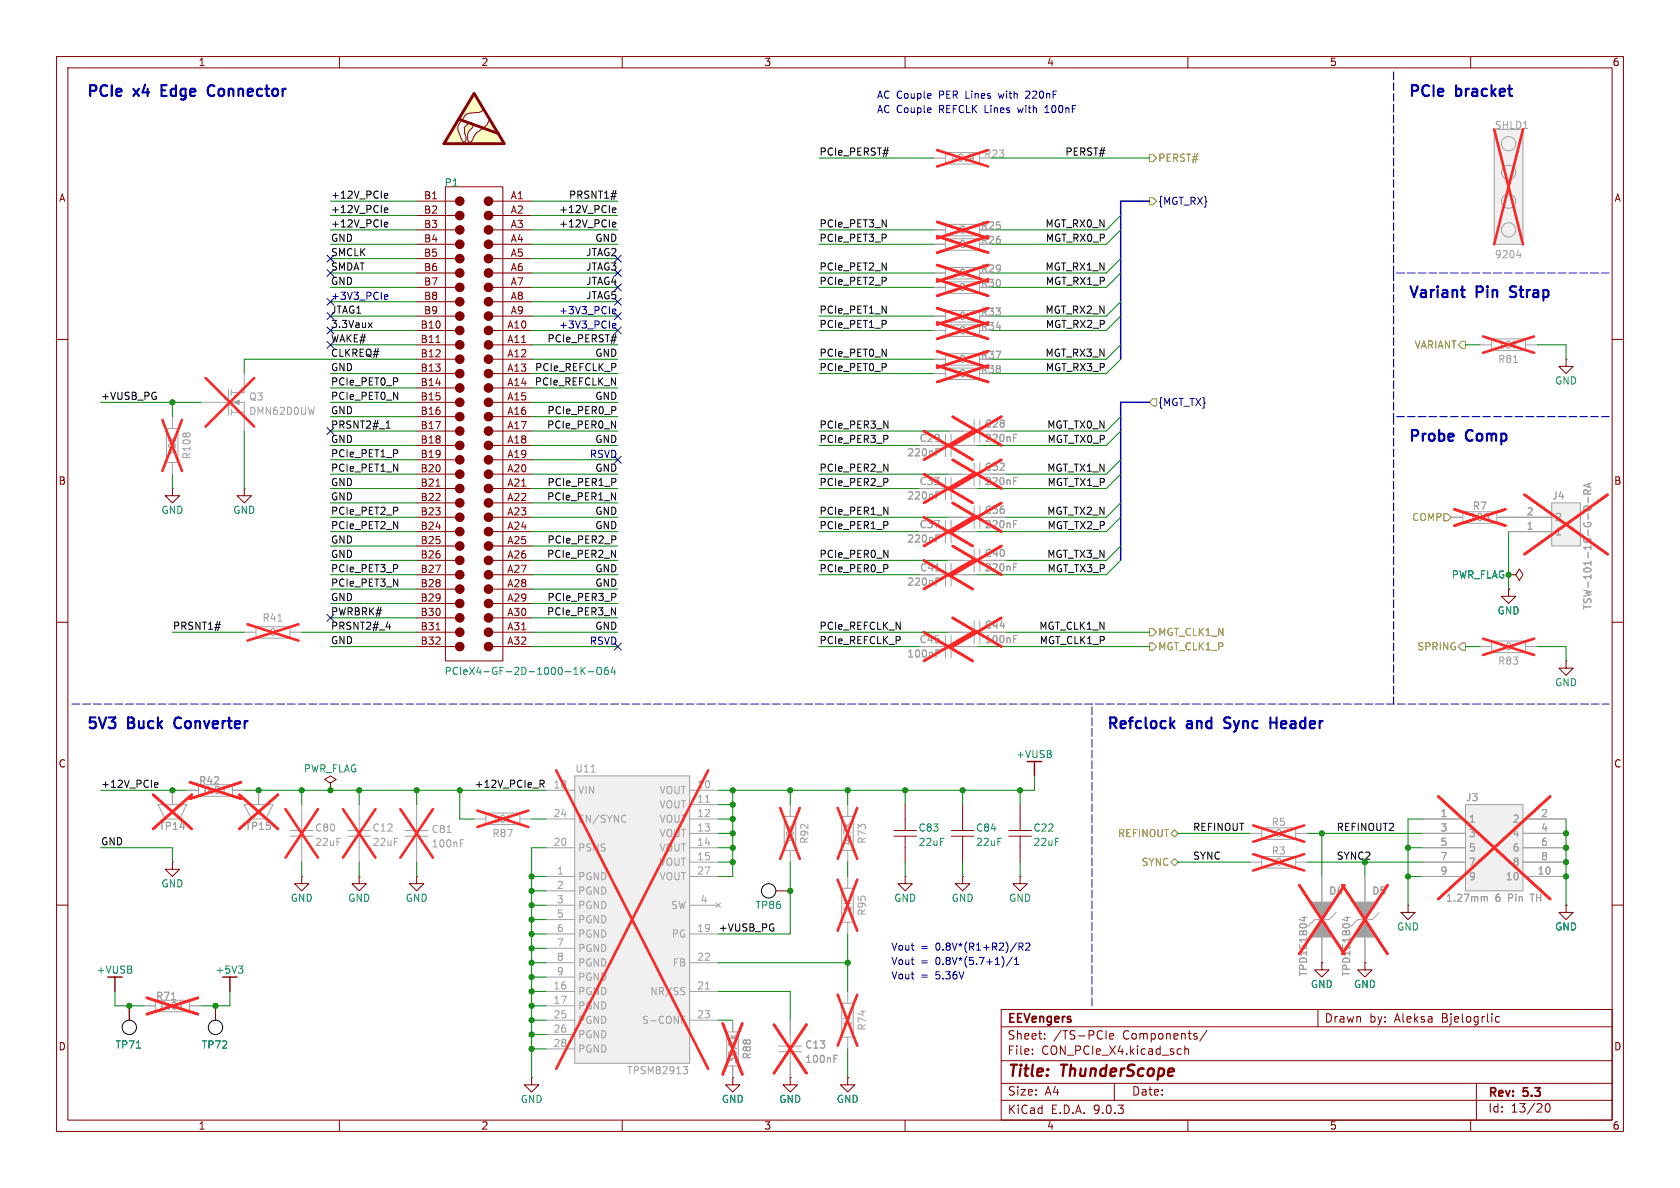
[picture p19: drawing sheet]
<svg xmlns="http://www.w3.org/2000/svg" width="297mm" height="210mm" viewBox="0 0 297 210" stroke-linecap="round" stroke-linejoin="round" font-family="sans-serif">
<defs><g id="words">
<g font-size="2.8" fill="#840000">
<text x="178" y="190.9">Title:</text>
<text x="187.7" y="190.9">ThunderScope</text>
</g>
<g font-size="2.7" fill="#0000c2">
<text x="15.2" y="18">PCIe</text>
<text x="23.8" y="18">x4</text>
<text x="29.4" y="18">Edge</text>
<text x="38.4" y="18">Connector</text>
<text x="248.9" y="18">PCIe</text>
<text x="257.5" y="18">bracket</text>
<text x="248.9" y="53.6">Variant</text>
<text x="261.1" y="53.6">Pin</text>
<text x="267.9" y="53.6">Strap</text>
<text x="248.9" y="79">Probe</text>
<text x="259.3" y="79">Comp</text>
<text x="15.2" y="129.8">5V3</text>
<text x="22.7" y="129.8">Buck</text>
<text x="31.7" y="129.8">Converter</text>
<text x="195.6" y="129.8">Refclock</text>
<text x="209.9" y="129.8">and</text>
<text x="217.3" y="129.8">Sync</text>
<text x="226.2" y="129.8">Header</text>
</g>
<g font-size="2.1" fill="#840000">
<text x="178" y="184">Sheet:</text>
<text x="178" y="181.2">EEVengers</text>
<text x="186.2" y="184">/TS-PCIe</text>
<text x="198.5" y="184">Components/</text>
<text x="234.1" y="181">Drawn</text>
<text x="242.1" y="181">by:</text>
<text x="246.6" y="181">Aleksa</text>
<text x="255" y="181">Bjelogrlic</text>
<text x="178" y="186.7">File:</text>
<text x="184.1" y="186.7">CON_PCIe_X4.kicad_sch</text>
<text x="178.1" y="197.1">KiCad</text>
<text x="178.1" y="193.9">Size:</text>
<text x="184.7" y="193.9">A4</text>
<text x="185.8" y="197.1">E.D.A.</text>
<text x="193.4" y="197.1">9.0.3</text>
<text x="200" y="193.9">Date:</text>
<text x="263" y="194.3">Rev:</text>
<text x="263" y="196.9">Id:</text>
<text x="267.1" y="196.9">13/20</text>
<text x="269.4" y="194.3">5.3</text>
</g>
<g font-size="1.8" fill="#840000">
<text x="35" y="11.9">1</text>
<text x="85" y="11.9">2</text>
<text x="135" y="11.9">3</text>
<text x="185" y="11.9">4</text>
<text x="235" y="11.9">5</text>
<text x="285" y="11.9">6</text>
<text x="10.3" y="35.9">A</text>
<text x="74.9" y="35.3">B1</text>
<text x="90.2" y="35.3">A1</text>
<text x="285.3" y="35.9">A</text>
<text x="74.9" y="37.8">B2</text>
<text x="74.9" y="40.4">B3</text>
<text x="90.2" y="37.8">A2</text>
<text x="90.2" y="40.4">A3</text>
<text x="74.9" y="42.9">B4</text>
<text x="74.9" y="45.5">B5</text>
<text x="90.2" y="42.9">A4</text>
<text x="90.2" y="45.5">A5</text>
<text x="74.9" y="48">B6</text>
<text x="74.9" y="50.5">B7</text>
<text x="74.9" y="53.1">B8</text>
<text x="90.2" y="48">A6</text>
<text x="90.2" y="50.5">A7</text>
<text x="90.2" y="53.1">A8</text>
<text x="74.3" y="58.2">B10</text>
<text x="74.9" y="55.6">B9</text>
<text x="89.6" y="58.2">A10</text>
<text x="90.2" y="55.6">A9</text>
<text x="74.3" y="60.7">B11</text>
<text x="74.3" y="63.2">B12</text>
<text x="74.3" y="65.8">B13</text>
<text x="89.6" y="60.7">A11</text>
<text x="89.6" y="63.2">A12</text>
<text x="89.6" y="65.8">A13</text>
<text x="74.3" y="68.3">B14</text>
<text x="74.3" y="70.9">B15</text>
<text x="89.6" y="68.3">A14</text>
<text x="89.6" y="70.9">A15</text>
<text x="74.3" y="73.4">B16</text>
<text x="74.3" y="75.9">B17</text>
<text x="89.6" y="73.4">A16</text>
<text x="89.6" y="75.9">A17</text>
<text x="74.3" y="78.5">B18</text>
<text x="74.3" y="81">B19</text>
<text x="74.3" y="83.6">B20</text>
<text x="89.6" y="78.5">A18</text>
<text x="89.6" y="81">A19</text>
<text x="89.6" y="83.6">A20</text>
<text x="10.3" y="85.9">B</text>
<text x="74.3" y="86.1">B21</text>
<text x="74.3" y="88.6">B22</text>
<text x="89.6" y="86.1">A21</text>
<text x="89.6" y="88.6">A22</text>
<text x="285.3" y="85.9">B</text>
<text x="74.3" y="91.2">B23</text>
<text x="74.3" y="93.7">B24</text>
<text x="89.6" y="91.2">A23</text>
<text x="89.6" y="93.7">A24</text>
<text x="74.3" y="96.3">B25</text>
<text x="74.3" y="98.8">B26</text>
<text x="74.3" y="101.3">B27</text>
<text x="89.6" y="96.3">A25</text>
<text x="89.6" y="98.8">A26</text>
<text x="89.6" y="101.3">A27</text>
<text x="74.3" y="103.9">B28</text>
<text x="74.3" y="106.4">B29</text>
<text x="89.6" y="103.9">A28</text>
<text x="89.6" y="106.4">A29</text>
<text x="256.5" y="102.5">PWR_FLAG</text>
<text x="74.3" y="109">B30</text>
<text x="74.3" y="111.5">B31</text>
<text x="89.6" y="109">A30</text>
<text x="89.6" y="111.5">A31</text>
<text x="74.3" y="114">B32</text>
<text x="89.6" y="114">A32</text>
<text x="10.3" y="135.9">C</text>
<text x="285.3" y="135.9">C</text>
<text x="10.3" y="185.9">D</text>
<text x="285.3" y="185.9">D</text>
<text x="35" y="199.9">1</text>
<text x="85" y="199.9">2</text>
<text x="135" y="199.9">3</text>
<text x="185" y="199.9">4</text>
<text x="235" y="199.9">5</text>
<text x="285" y="199.9">6</text>
</g>
<g font-size="1.8" fill="#0000c2">
<text x="154.9" y="17.5">AC Couple</text>
<text x="166.1" y="17.5">PER Lines</text>
<text x="177" y="17.5">with</text>
<text x="182" y="17.5">220nF</text>
<text x="154.9" y="20.1">AC Couple</text>
<text x="166.1" y="20.1">REFCLK</text>
<text x="174.4" y="20.1">Lines</text>
<text x="180.4" y="20.1">with</text>
<text x="185.4" y="20.1">100nF</text>
<text x="58.4" y="53.1">+3V3_PCIe</text>
<text x="98.7" y="55.6">+3V3_PCIe</text>
<text x="98.7" y="58.2">+3V3_PCIe</text>
<text x="104.2" y="81">RSVD</text>
<text x="104.2" y="114.1">RSVD</text>
<text x="157.5" y="173.3">Vout</text>
<text x="157.5" y="168.3">Vout</text>
<text x="157.5" y="170.8">Vout</text>
<text x="162.8" y="173.3">=</text>
<text x="162.8" y="168.3">=</text>
<text x="162.8" y="170.8">=</text>
<text x="165.5" y="173.3">5.36V</text>
<text x="165.5" y="168.3">0.8V*(R1+R2)/R2</text>
<text x="165.5" y="170.8">0.8V*(5.7+1)/1</text>
</g>
<g font-size="1.8" fill="#a1a1a1">
<text x="264.2" y="23">SHLD1</text>
<text x="168" y="28.8">49.9</text>
<text x="173.9" y="28.1">R23</text>
<text x="169.5" y="41.5">0</text>
<text x="173.3" y="40.8">R25</text>
<text x="169.5" y="44">0</text>
<text x="173.3" y="43.3">R26</text>
<text x="264.2" y="45.9">9204</text>
<text x="169.5" y="49.1">0</text>
<text x="169.5" y="51.7">0</text>
<text x="173.3" y="48.4">R29</text>
<text x="173.3" y="50.9">R30</text>
<text x="169.5" y="59.3">0</text>
<text x="169.5" y="56.7">0</text>
<text x="173.3" y="58.6">R34</text>
<text x="173.3" y="56">R33</text>
<text x="169.5" y="64.4">0</text>
<text x="173.3" y="63.6">R37</text>
<text x="264.8" y="64.4">R81</text>
<text x="264.8" y="61.8">10K</text>
<text x="44" y="71">Q3</text>
<text x="169.5" y="66.9">0</text>
<text x="173.3" y="66.2">R38</text>
<text x="44" y="73.5">DMN62D0UW</text>
<text x="174" y="75.8">C28</text>
<text x="31.3" y="80.7" transform="rotate(-90 31.3 80.7)">10K</text>
<text x="33.9" y="81.3" transform="rotate(-90 33.9 81.3)">R108</text>
<text x="160.3" y="80.9">220nF</text>
<text x="162.5" y="78.3">C29</text>
<text x="174" y="78.3">220nF</text>
<text x="174" y="83.4">C32</text>
<text x="160.3" y="88.5">220nF</text>
<text x="162.5" y="86">C33</text>
<text x="174" y="86">220nF</text>
<text x="274.3" y="88.5">J4</text>
<text x="162.5" y="93.6">C37</text>
<text x="174" y="93.6">220nF</text>
<text x="174" y="91">C36</text>
<text x="259.7" y="92.3">100</text>
<text x="260.3" y="90.3">R7</text>
<text x="269.8" y="91.2">2</text>
<text x="269.8" y="93.7">1</text>
<text x="274.8" y="92.3">2</text>
<text x="274.8" y="94.8">1</text>
<text x="160.3" y="96.1">220nF</text>
<text x="162.6" y="101.2">C41</text>
<text x="174" y="101.2">220nF</text>
<text x="174" y="98.7">C40</text>
<text x="160.3" y="103.7">220nF</text>
<text x="281.5" y="107.9" transform="rotate(-90 281.5 107.9)">TSW-101-16-G-Q-RA</text>
<text x="46.3" y="110.1">R41</text>
<text x="47.6" y="112.6">0</text>
<text x="162.5" y="113.9">C45</text>
<text x="174" y="113.9">100nF</text>
<text x="174" y="111.4">C44</text>
<text x="160.3" y="116.4">100nF</text>
<text x="264.8" y="117.7">R83</text>
<text x="266" y="115.2">0</text>
<text x="101.6" y="136.8">U11</text>
<text x="35.1" y="138.9">R42</text>
<text x="35.9" y="140.6">0.01</text>
<text x="97.7" y="139.4">18</text>
<text x="102.1" y="140.6">VIN</text>
<text x="116.5" y="140.6">VOUT</text>
<text x="116.5" y="143.1">VOUT</text>
<text x="123.1" y="139.4">10</text>
<text x="123.1" y="142">11</text>
<text x="259.1" y="141.8">J3</text>
<text x="28.1" y="146.9">TP14</text>
<text x="43.3" y="146.9">TP15</text>
<text x="55.6" y="147.2">C80</text>
<text x="55.6" y="149.7">22uF</text>
<text x="65.8" y="147.2">C12</text>
<text x="65.8" y="149.7">22uF</text>
<text x="76.2" y="150">100nF</text>
<text x="76.2" y="147.5">C81</text>
<text x="87" y="148.2">R87</text>
<text x="87" y="145.6">10K</text>
<text x="97.7" y="144.5">24</text>
<text x="97.7" y="149.6">20</text>
<text x="102.1" y="145.6">EN/SYNC</text>
<text x="116.5" y="145.6">VOUT</text>
<text x="116.5" y="148.2">VOUT</text>
<text x="123.1" y="144.5">12</text>
<text x="123.1" y="147.1">13</text>
<text x="123.1" y="149.6">14</text>
<text x="140.6" y="149.3" transform="rotate(-90 140.6 149.3)">10K</text>
<text x="143.1" y="149.3" transform="rotate(-90 143.1 149.3)">R92</text>
<text x="150.7" y="149.6" transform="rotate(-90 150.7 149.6)">4.7K</text>
<text x="153.3" y="149.3" transform="rotate(-90 153.3 149.3)">R73</text>
<text x="224.7" y="146.2">R5</text>
<text x="225.4" y="148.2">0</text>
<text x="254.6" y="144.5">1</text>
<text x="254.6" y="147.1">3</text>
<text x="254.6" y="149.6">5</text>
<text x="259.6" y="145.6">1</text>
<text x="259.6" y="148.2">3</text>
<text x="267.3" y="145.6">2</text>
<text x="267.3" y="148.2">4</text>
<text x="272.3" y="144.5">2</text>
<text x="272.3" y="147.1">4</text>
<text x="272.3" y="149.6">6</text>
<text x="98.4" y="154.7">1</text>
<text x="102.1" y="150.7">PSNS</text>
<text x="102.1" y="155.8">PGND</text>
<text x="116.5" y="150.7">VOUT</text>
<text x="116.5" y="153.3">VOUT</text>
<text x="116.5" y="155.8">VOUT</text>
<text x="123.1" y="152.1">15</text>
<text x="123.1" y="154.7">27</text>
<text x="224.7" y="151.3">R3</text>
<text x="225.4" y="153.3">0</text>
<text x="254.6" y="152.1">7</text>
<text x="254.6" y="154.7">9</text>
<text x="259.6" y="150.7">5</text>
<text x="259.6" y="153.3">7</text>
<text x="259.6" y="155.8">9</text>
<text x="266.1" y="155.8">10</text>
<text x="267.3" y="150.7">6</text>
<text x="267.3" y="153.3">8</text>
<text x="271.7" y="154.7">10</text>
<text x="272.3" y="152.1">8</text>
<text x="98.4" y="157.2">2</text>
<text x="98.4" y="159.8">3</text>
<text x="102.1" y="158.3">PGND</text>
<text x="102.1" y="160.9">PGND</text>
<text x="118.5" y="160.9">SW</text>
<text x="123.8" y="159.8">4</text>
<text x="150.7" y="161.4" transform="rotate(-90 150.7 161.4)">1K</text>
<text x="153.3" y="162" transform="rotate(-90 153.3 162)">R95</text>
<text x="234.9" y="158.3">D4</text>
<text x="242.5" y="158.3">D5</text>
<text x="255.5" y="159.6">1.27mm</text>
<text x="264.3" y="159.6">6</text>
<text x="266.7" y="159.6">Pin</text>
<text x="270.9" y="159.6">TH</text>
<text x="98.4" y="162.3">5</text>
<text x="98.4" y="164.8">6</text>
<text x="98.4" y="167.4">7</text>
<text x="102.1" y="163.4">PGND</text>
<text x="102.1" y="166">PGND</text>
<text x="118.7" y="166">PG</text>
<text x="123.1" y="164.8">19</text>
<text x="98.4" y="169.9">8</text>
<text x="98.4" y="172.5">9</text>
<text x="102.1" y="168.5">PGND</text>
<text x="102.1" y="171">PGND</text>
<text x="102.1" y="173.6">PGND</text>
<text x="118.9" y="171">FB</text>
<text x="123.1" y="169.9">22</text>
<text x="231.3" y="172.7" transform="rotate(-90 231.3 172.7)">TPD1E1B04</text>
<text x="238.9" y="172.7" transform="rotate(-90 238.9 172.7)">TPD1E1B04</text>
<text x="27.5" y="177">R71</text>
<text x="28.3" y="178.7">0.01</text>
<text x="97.7" y="175">16</text>
<text x="97.7" y="177.5">17</text>
<text x="102.1" y="176.1">PGND</text>
<text x="102.1" y="178.7">PGND</text>
<text x="114.9" y="176.1">NR/SS</text>
<text x="123.1" y="175">21</text>
<text x="97.7" y="180.1">25</text>
<text x="97.7" y="182.6">26</text>
<text x="97.7" y="185.2">28</text>
<text x="102.1" y="181.2">PGND</text>
<text x="102.1" y="183.7">PGND</text>
<text x="113.4" y="181.2">S-CONF</text>
<text x="123.1" y="180.1">23</text>
<text x="142.2" y="185.6">C13</text>
<text x="150.7" y="181.7" transform="rotate(-90 150.7 181.7)">1K</text>
<text x="153.3" y="182.3" transform="rotate(-90 153.3 182.3)">R74</text>
<text x="102.1" y="186.3">PGND</text>
<text x="110.8" y="190.1">TPSM82913</text>
<text x="130.4" y="188.2" transform="rotate(-90 130.4 188.2)">35.7k</text>
<text x="132.9" y="187.4" transform="rotate(-90 132.9 187.4)">R88</text>
<text x="142.2" y="188.1">100nF</text>
</g>
<g font-size="1.8">
<text x="144.8" y="27.6">PCIe_PERST#</text>
<text x="188.2" y="27.6">PERST#</text>
<text x="58.4" y="35.2">+12V_PCIe</text>
<text x="100.5" y="35.2">PRSNT1#</text>
<text x="58.4" y="37.8">+12V_PCIe</text>
<text x="58.4" y="40.3">+12V_PCIe</text>
<text x="98.7" y="37.8">+12V_PCIe</text>
<text x="98.7" y="40.3">+12V_PCIe</text>
<text x="144.8" y="40.3">PCIe_PET3_N</text>
<text x="184.7" y="40.3">MGT_RX0_N</text>
<text x="58.4" y="47.9">SMDAT</text>
<text x="58.4" y="42.8">GND</text>
<text x="58.4" y="45.4">SMCLK</text>
<text x="103.5" y="45.4">JTAG2</text>
<text x="103.5" y="47.9">JTAG3</text>
<text x="105.1" y="42.8">GND</text>
<text x="144.8" y="47.9">PCIe_PET2_N</text>
<text x="144.8" y="42.8">PCIe_PET3_P</text>
<text x="184.7" y="47.9">MGT_RX1_N</text>
<text x="184.8" y="42.8">MGT_RX0_P</text>
<text x="58.4" y="50.5">GND</text>
<text x="103.5" y="53">JTAG5</text>
<text x="103.5" y="50.5">JTAG4</text>
<text x="144.8" y="50.5">PCIe_PET2_P</text>
<text x="184.8" y="50.5">MGT_RX1_P</text>
<text x="58.4" y="58.1">3.3Vaux</text>
<text x="58.4" y="55.5">JTAG1</text>
<text x="144.8" y="55.5">PCIe_PET1_N</text>
<text x="144.8" y="58.1">PCIe_PET1_P</text>
<text x="184.7" y="55.5">MGT_RX2_N</text>
<text x="184.8" y="58.1">MGT_RX2_P</text>
<text x="58.4" y="65.7">GND</text>
<text x="58.4" y="60.6">WAKE#</text>
<text x="58.4" y="63.2">CLKREQ#</text>
<text x="94.5" y="65.7">PCIe_REFCLK_P</text>
<text x="96.7" y="60.6">PCIe_PERST#</text>
<text x="105.1" y="63.2">GND</text>
<text x="144.8" y="65.7">PCIe_PET0_P</text>
<text x="144.8" y="63.2">PCIe_PET0_N</text>
<text x="184.7" y="63.2">MGT_RX3_N</text>
<text x="184.8" y="65.7">MGT_RX3_P</text>
<text x="17.8" y="70.8">+VUSB_PG</text>
<text x="58.4" y="68.2">PCIe_PET0_P</text>
<text x="58.4" y="70.8">PCIe_PET0_N</text>
<text x="94.4" y="68.2">PCIe_REFCLK_N</text>
<text x="105.1" y="70.8">GND</text>
<text x="58.4" y="73.3">GND</text>
<text x="58.4" y="75.9">PRSNT2#_1</text>
<text x="96.6" y="75.9">PCIe_PER0_N</text>
<text x="96.7" y="73.3">PCIe_PER0_P</text>
<text x="144.8" y="75.9">PCIe_PER3_N</text>
<text x="185" y="75.9">MGT_TX0_N</text>
<text x="58.4" y="80.9">PCIe_PET1_P</text>
<text x="58.4" y="78.4">GND</text>
<text x="58.4" y="83.5">PCIe_PET1_N</text>
<text x="105.1" y="83.5">GND</text>
<text x="105.1" y="78.4">GND</text>
<text x="144.8" y="83.5">PCIe_PER2_N</text>
<text x="144.8" y="78.4">PCIe_PER3_P</text>
<text x="185" y="83.5">MGT_TX1_N</text>
<text x="185.1" y="78.4">MGT_TX0_P</text>
<text x="58.4" y="86">GND</text>
<text x="58.4" y="88.6">GND</text>
<text x="96.6" y="88.6">PCIe_PER1_N</text>
<text x="96.7" y="86">PCIe_PER1_P</text>
<text x="144.8" y="86">PCIe_PER2_P</text>
<text x="185.1" y="86">MGT_TX1_P</text>
<text x="58.4" y="91.1">PCIe_PET2_P</text>
<text x="58.4" y="93.6">PCIe_PET2_N</text>
<text x="105.1" y="91.1">GND</text>
<text x="105.1" y="93.6">GND</text>
<text x="144.8" y="91.1">PCIe_PER1_N</text>
<text x="144.8" y="93.6">PCIe_PER1_P</text>
<text x="185" y="91.1">MGT_TX2_N</text>
<text x="185.1" y="93.6">MGT_TX2_P</text>
<text x="58.4" y="101.3">PCIe_PET3_P</text>
<text x="58.4" y="98.7">GND</text>
<text x="58.4" y="96.2">GND</text>
<text x="96.6" y="98.7">PCIe_PER2_N</text>
<text x="96.7" y="96.2">PCIe_PER2_P</text>
<text x="105.1" y="101.3">GND</text>
<text x="144.8" y="98.7">PCIe_PER0_N</text>
<text x="144.8" y="101.3">PCIe_PER0_P</text>
<text x="185" y="98.7">MGT_TX3_N</text>
<text x="185.1" y="101.3">MGT_TX3_P</text>
<text x="58.4" y="103.8">PCIe_PET3_N</text>
<text x="58.4" y="106.3">GND</text>
<text x="96.7" y="106.3">PCIe_PER3_P</text>
<text x="105.1" y="103.8">GND</text>
<text x="30.5" y="111.4">PRSNT1#</text>
<text x="58.4" y="111.4">PRSNT2#_4</text>
<text x="58.4" y="114">GND</text>
<text x="58.4" y="108.9">PWRBRK#</text>
<text x="96.6" y="108.9">PCIe_PER3_N</text>
<text x="105.1" y="111.4">GND</text>
<text x="144.8" y="114">PCIe_REFCLK_P</text>
<text x="144.8" y="111.4">PCIe_REFCLK_N</text>
<text x="183.6" y="111.4">MGT_CLK1_N</text>
<text x="183.7" y="114">MGT_CLK1_P</text>
<text x="17.8" y="139.4">+12V_PCIe</text>
<text x="83.8" y="139.4">+12V_PCIe_R</text>
<text x="17.8" y="149.5">GND</text>
<text x="210.8" y="147">REFINOUT</text>
<text x="236.2" y="147">REFINOUT2</text>
<text x="210.8" y="152.1">SYNC</text>
<text x="236.2" y="152.1">SYNC2</text>
<text x="127" y="164.8">+VUSB_PG</text>
</g>
<g font-size="1.8" fill="#848400">
<text x="204.7" y="28.8">PERST#</text>
<text x="250" y="61.8">VARIANT</text>
<text x="249.6" y="92.3">COMP</text>
<text x="204.7" y="112.6">MGT_CLK1_N</text>
<text x="204.7" y="115.2">MGT_CLK1_P</text>
<text x="250.5" y="115.2">SPRING</text>
<text x="197.5" y="148.2">REFINOUT</text>
<text x="201.7" y="153.3">SYNC</text>
</g>
<g font-size="1.8" fill="#008484">
<text x="78.5" y="33.2">P1</text>
<text x="274.8" y="68.2">GND</text>
<text x="28.4" y="91">GND</text>
<text x="41.1" y="91">GND</text>
<text x="264.7" y="108.8">GND</text>
<text x="78.5" y="119.5">PCIeX4-GF-2D-1000-1K-O64</text>
<text x="274.8" y="121.5">GND</text>
<text x="53.6" y="136.8">PWR_FLAG</text>
<text x="179.5" y="134.2">+VUSB</text>
<text x="162.3" y="147.2">C83</text>
<text x="162.3" y="149.7">22uF</text>
<text x="172.4" y="147.2">C84</text>
<text x="172.4" y="149.7">22uF</text>
<text x="182.6" y="147.2">C22</text>
<text x="182.6" y="149.7">22uF</text>
<text x="28.4" y="157.1">GND</text>
<text x="51.3" y="159.6">GND</text>
<text x="61.5" y="159.6">GND</text>
<text x="71.6" y="159.6">GND</text>
<text x="133.5" y="160.9">TP86</text>
<text x="158" y="159.6">GND</text>
<text x="168.1" y="159.6">GND</text>
<text x="178.3" y="159.6">GND</text>
<text x="246.9" y="164.7">GND</text>
<text x="274.8" y="164.7">GND</text>
<text x="17" y="172.3">+VUSB</text>
<text x="38" y="172.3">+5V3</text>
<text x="231.6" y="174.9">GND</text>
<text x="239.3" y="174.9">GND</text>
<text x="20.3" y="185.6">TP71</text>
<text x="35.6" y="185.6">TP72</text>
<text x="91.9" y="195.2">GND</text>
<text x="127.5" y="195.2">GND</text>
<text x="137.7" y="195.2">GND</text>
<text x="147.8" y="195.2">GND</text>
</g>
<g font-size="1.8" fill="#000084">
<text x="204.7" y="36.4">{MGT_RX}</text>
<text x="204.7" y="72">{MGT_TX}</text>
</g>
</g></defs>
<path d="M0 0h297v210h-297z" fill="#fff" stroke="#fff" stroke-width=".18"/>
<g fill="none" stroke="#840000" stroke-width=".18">
<path d="M10 10h277v190h-277zM12 12h273v186h-273zM60 10v2M110 10v2M160 10v2M210 10v2M260 10v2M73.7 35.6h6.8M73.7 38.1h6.8M78.7 33h10.2v83.8h-10.2zM87.1 35.6h6.9M87.1 38.1h6.9"/>
<path d="M73.7 40.6h6.8M73.7 43.2h6.8M73.7 45.7h6.8M73.7 48.3h6.8M73.7 50.8h6.8M73.7 53.3h6.8M73.7 55.9h6.8M73.7 58.4h6.8M87.1 40.6h6.9M87.1 43.2h6.9M87.1 45.7h6.9M87.1 48.3h6.9"/>
<path d="M87.1 50.8h6.9M87.1 53.3h6.9M87.1 55.9h6.9M87.1 58.4h6.9M10 60h2M73.7 61h6.8M73.7 63.5h6.8M73.7 66h6.8M73.7 68.6h6.8M73.7 71.1h6.8M73.7 73.7h6.8M73.7 76.2h6.8"/>
<path d="M73.7 78.7h6.8M77.1 60.5h.7M87.1 61h6.9M87.1 63.5h6.9M87.1 66h6.9M87.1 68.6h6.9M87.1 71.1h6.9M87.1 73.7h6.9M87.1 76.2h6.9M87.1 78.7h6.9M285 60h2M73.7 81.3h6.8"/>
<path d="M73.7 83.8h6.8M73.7 86.4h6.8M73.7 88.9h6.8M73.7 91.4h6.8M73.7 94h6.8M73.7 96.5h6.8M73.7 99.1h6.8M77.1 85.9h.7M87.1 81.3h6.9M87.1 83.8h6.9M87.1 86.4h6.9M87.1 88.9h6.9"/>
<path d="M87.1 91.4h6.9M87.1 94h6.9M87.1 96.5h6.9M87.1 99.1h6.9M10 110h2M73.7 101.6h6.8M73.7 104.1h6.8M73.7 106.7h6.8M73.7 109.2h6.8M73.7 111.8h6.8M73.7 114.3h6.8M77.1 111.3h.7"/>
<path d="M87.1 101.6h6.9M87.1 104.1h6.9M87.1 106.7h6.9M87.1 109.2h6.9M87.1 111.8h6.9M87.1 114.3h6.9M285 110h2M30.5 152.4v1.3h1.2l-1.2 1.2-1.3-1.2h1.3M30.5 152.4h.1M10 160h2M38.1 177.8v2.5M177 178.5h108v19.5h-108z"/>
<path d="M233 178.5v3M241.3 170.2v1.3h1.3l-1.3 1.2-1.3-1.2h1.3M241.3 170.2h.1M265.1 179.8l-.4-.1-.3 .3v.4l.1 .2h.6M276.9 160v1.3h1.2l-1.2 1.3-1.3-1.3h1.3M276.9 160h.1M285 160h2M60 198v2M110 198v2M160 198v2M177 194.5h108M177 191.5h108"/>
<path d="M177 187.5h108M177 181.5h108M182.5 186.3v.1M182.5 185.5v.1M184.7 183.6v.1M184.7 182.8v.1M195.5 182.2v1.5M196.2 183.2l.7-.1-.1-.3-.4-.1-.2 .2v.7h.6M197 191.5v3M208.7 185.4l.1 .1M208.8 186.3l-.1 .1M209.5 184.9v1.5"/>
<path d="M209.5 185.5l.2-.1 .3 .1 .1 .9M210 198v2M213.4 182.1l-1.3 2M260 198v2M261 191.5v6.5M273.3 195.2l.2-.1a.81 .81 0 0 1 .6 .6 .81 .81 0 0 1-.3 .8l-.1 .1a.81 .81 0 0 1-.4-1.4z"/>
</g>
<g fill="none" stroke="#a1a1a1" stroke-width=".18">
<path d="M165.1 48.3h2M165.1 50.8h2M165.1 58.4h2M165.1 55.9h2M165.1 43.2h2M167.2 47.3h6v2h-6zM167.2 49.8h6v2.1h-6zM167.2 57.4h6v2.1h-6zM167.2 54.9h6v2h-6zM167.2 42.2h6v2h-6zM165.1 66h2M165.1 63.5h2"/>
<path d="M165.1 78.7h2M165.5 79.9h.4M165.5 79.3h.6M167.1 76.7v4M167.2 65.1h6v2h-6zM167.2 62.5h6v2.1h-6zM167.6 76.2h4.6M168.1 76.7v4M168.1 78.7h4.6M172.2 74.2v4M173.2 74.2v4M173.2 76.2h4.6"/>
<path d="M179.2 77.4h.4M179.2 76.8h.6M165.1 94h2M165.1 86.4h2M165.5 95.2h.4M165.5 94.6h.6M165.5 87.5h.4M165.5 86.9h.6M167.1 84.4v4M167.1 92v4M167.1 99.6v4M167.6 91.4h4.6"/>
<path d="M167.6 99.1h4.6M167.6 83.8h4.6M168.1 84.4v4M168.1 92v4M168.1 99.6v4M168.1 94h4.6M168.1 86.4h4.6M172.2 81.8v4M172.2 89.4v4M172.2 97.1v4M173.2 81.8v4M173.2 89.4v4"/>
<path d="M173.2 97.1v4M173.2 91.4h4.6M173.2 99.1h4.6M173.2 83.8h4.6M179.2 92.6h.4M179.2 92h.6M179.2 99.6h.6M179.2 85h.4M179.2 84.4h.6M165.1 101.6h2M165.1 114.3h2M165.4 100.9h.7"/>
<path d="M165.5 102.8h.4M165.5 102.2h.6M165.5 115.5h.4M165.5 114.9h.6M167.1 112.3v4M167.6 111.8h4.6M168.1 112.3v4M168.1 101.6h4.6M168.1 114.3h4.6M172.2 109.8v4M173.2 109.8v4M173.2 111.8h2.1"/>
<path d="M179.2 112.9h.4M179.2 112.3h.6M179.2 100.2h.4M30.5 139.7v2.5M27.9 142.2h5.1l-1.3 2.6h-2.5zM51.3 146.8h4M51.3 147.8h4M53.3 142.2v4.6M53.3 147.8v4.6M221 152.4h2M223.1 151.4h6v2.1h-6zM229.1 152.4h2"/>
<path d="M25.4 177.8h2M27.5 176.8h6v2.1h-6zM30.3 176.7h.7M31.6 178.4h.8M31.9 177.3l.1-.2v1.3M33.6 177.8h2"/>
</g>
<g fill="none" stroke="#ff2626" stroke-width=".46">
<path d="M165.7 46.9l9 2.8M165.7 49.4l9 2.9M165.7 57l9 2.9M165.7 54.5l9 2.9M165.7 41.8l9 2.9M174.7 46.9l-9 2.8M174.7 49.4l-9 2.9M174.7 57l-9 2.9M174.7 54.5l-9 2.9M174.7 41.8l-9 2.9M163.3 76.2l8.6 5.1M165.7 64.6l9 2.9"/>
<path d="M165.7 62.1l9 2.9M168.4 73.7l8.6 5M171.9 76.2l-8.6 5.1M174.7 64.6l-9 2.9M174.7 62.1l-9 2.9M177 73.7l-8.6 5M163.3 91.5l8.6 5M163.3 99.1l8.6 5M163.3 83.8l8.6 5.1M168.4 88.9l8.6 5.1M168.4 96.5l8.6 5.1M168.4 81.3l8.6 5"/>
<path d="M171.9 91.5l-8.6 5M171.9 99.1l-8.6 5M171.9 83.8l-8.6 5.1M177 88.9l-8.6 5.1M177 96.5l-8.6 5.1M177 81.3l-8.6 5M163.3 111.8l8.6 5M168.4 109.2l8.6 5.1M171.9 111.8l-8.6 5M177 109.2l-8.6 5.1M27.1 140.5l6.8 6M33.9 140.5l-6.8 6"/>
<path d="M50.5 143l5.7 8.6M56.2 143l-5.7 8.6M221.6 151l9 2.9M230.6 151l-9 2.9M26 176.4l9 2.9M35 176.4l-9 2.9"/>
</g>
<g fill="#840000" stroke="#840000" stroke-width=".18">
<circle cx="81.3" cy="35.6" r=".76"/>
<circle cx="81.3" cy="38.1" r=".76"/>
<circle cx="81.3" cy="40.6" r=".76"/>
<circle cx="81.3" cy="43.2" r=".76"/>
<circle cx="81.3" cy="45.7" r=".76"/>
<circle cx="81.3" cy="48.3" r=".76"/>
<circle cx="81.3" cy="50.8" r=".76"/>
<circle cx="81.3" cy="53.3" r=".76"/>
<circle cx="81.3" cy="55.9" r=".76"/>
<circle cx="81.3" cy="58.4" r=".76"/>
<circle cx="81.3" cy="61" r=".76"/>
<circle cx="81.3" cy="63.5" r=".76"/>
<circle cx="81.3" cy="66" r=".76"/>
<circle cx="81.3" cy="68.6" r=".76"/>
<circle cx="81.3" cy="71.1" r=".76"/>
<circle cx="81.3" cy="73.7" r=".76"/>
<circle cx="81.3" cy="76.2" r=".76"/>
<circle cx="81.3" cy="78.7" r=".76"/>
<circle cx="81.3" cy="81.3" r=".76"/>
<circle cx="81.3" cy="83.8" r=".76"/>
<circle cx="81.3" cy="86.4" r=".76"/>
<circle cx="81.3" cy="88.9" r=".76"/>
<circle cx="81.3" cy="91.4" r=".76"/>
<circle cx="81.3" cy="94" r=".76"/>
<circle cx="81.3" cy="96.5" r=".76"/>
<circle cx="81.3" cy="99.1" r=".76"/>
<circle cx="81.3" cy="101.6" r=".76"/>
<circle cx="81.3" cy="104.1" r=".76"/>
<circle cx="81.3" cy="106.7" r=".76"/>
<circle cx="81.3" cy="109.2" r=".76"/>
<circle cx="81.3" cy="111.8" r=".76"/>
<circle cx="81.3" cy="114.3" r=".76"/>
<circle cx="86.4" cy="35.6" r=".76"/>
<circle cx="86.4" cy="38.1" r=".76"/>
<circle cx="86.4" cy="40.6" r=".76"/>
<circle cx="86.4" cy="43.2" r=".76"/>
<circle cx="86.4" cy="45.7" r=".76"/>
<circle cx="86.4" cy="48.3" r=".76"/>
<circle cx="86.4" cy="50.8" r=".76"/>
<circle cx="86.4" cy="53.3" r=".76"/>
<circle cx="86.4" cy="55.9" r=".76"/>
<circle cx="86.4" cy="58.4" r=".76"/>
<circle cx="86.4" cy="61" r=".76"/>
<circle cx="86.4" cy="63.5" r=".76"/>
<circle cx="86.4" cy="66" r=".76"/>
<circle cx="86.4" cy="68.6" r=".76"/>
<circle cx="86.4" cy="71.1" r=".76"/>
<circle cx="86.4" cy="73.7" r=".76"/>
<circle cx="86.4" cy="76.2" r=".76"/>
<circle cx="86.4" cy="78.7" r=".76"/>
<circle cx="86.4" cy="81.3" r=".76"/>
<circle cx="86.4" cy="83.8" r=".76"/>
<circle cx="86.4" cy="86.4" r=".76"/>
<circle cx="86.4" cy="88.9" r=".76"/>
<circle cx="86.4" cy="91.4" r=".76"/>
<circle cx="86.4" cy="94" r=".76"/>
<circle cx="86.4" cy="96.5" r=".76"/>
<circle cx="86.4" cy="99.1" r=".76"/>
<circle cx="86.4" cy="101.6" r=".76"/>
<circle cx="86.4" cy="104.1" r=".76"/>
<circle cx="86.4" cy="106.7" r=".76"/>
<circle cx="86.4" cy="109.2" r=".76"/>
<circle cx="86.4" cy="111.8" r=".76"/>
<circle cx="86.4" cy="114.3" r=".76"/>
</g>
<path d="M102.7 118v1.2M102.9 118.5l.6 .7M103.5 118l-.8 .7M104 118.8h1M105.7 118h.1a.43 .43 0 0 1 .6 .4v.4a.42 .42 0 0 1-.5 .5 .42 .42 0 0 1-.4-.5v-.4zM107.4 118h-.3a.86 .86 0 0 0 0 1.2l.4-.1 .1-.4-.3-.3-.3 .1-.2 .2M108.4 117.9l-.4 .9h.8M108.7 118.4v.8M42.2 170.8h.7l-.4 .4M42.7 171.2l.2 .3v.3l-.2 .2" fill="none" stroke="#008484" stroke-width=".18"/>
<path d="M20.3 172.7v2.6M40.6 172.7v2.6" fill="none" stroke="#840000" stroke-width=".25"/>
<circle cx="38.1" cy="181.6" r="1.27" fill="none" stroke="#000" stroke-width=".18"/>
<path d="M231.8 159.4h3.8l-1.9 3.2z" fill="#a1a1a1"/>
<path d="M234.9 162.6h-2.5l-1.3 1.2" fill="none" stroke="#a1a1a1" stroke-width=".18"/>
<path d="M233.7 162.6l1.9 3.1h-3.8z" fill="#a1a1a1"/>
<path d="M233.7 154.9v4.5M230.1 162.2h.9M230.6 162v.8M233.7 165.7v4.5M236.2 161.3l-1.3 1.3" fill="none" stroke="#a1a1a1" stroke-width=".18"/>
<path d="M229.7 156.5l8 12.1M237.7 156.5l-8 12.1" fill="none" stroke="#ff2626" stroke-width=".46"/>
<path d="M83.8 16.4l1.7 2.9-.6 .5-1.4 .2a1.5 1.5 0 0 0-1.6 1l-.2 .2a1.84 1.84 0 0 0-.4 2.7l.1 .3a1.05 1.05 0 0 0 .6 .9 .98 .98 0 0 0 .1-1.5v-.4a.98 .98 0 0 1 .7-1.3 .48 .48 0 0 1 .5-.2 .48 .48 0 0 1 .3 .6l-.1 .3a1.94 1.94 0 0 0-.7 2.4l.2 .1 .3-.1a5.8 5.8 0 0 1 2.5-2.7l.4-.4a.75 .75 0 0 1 .5-.7l2.5 4.3h-10.8z" fill="#ffffc2"/>
<path d="M83.8 16.5l5.4 8.9h-10.7zM81.2 21.1l6.9 2.5" fill="none" stroke="#840000" stroke-width=".51"/>
<path d="M83.8 16.4l1.7 2.9-.6 .5-1.4 .2a1.5 1.5 0 0 0-1.6 1l-.2 .2a1.84 1.84 0 0 0-.4 2.7l.1 .3a1.05 1.05 0 0 0 .6 .9 .98 .98 0 0 0 .1-1.5v-.4a.98 .98 0 0 1 .7-1.3 .48 .48 0 0 1 .5-.2 .48 .48 0 0 1 .3 .6l-.1 .3a1.94 1.94 0 0 0-.7 2.4l.2 .1 .3-.1a5.8 5.8 0 0 1 2.5-2.7l.4-.4a.75 .75 0 0 1 .5-.7l2.5 4.3h-10.8z" fill="none" stroke="#840000" stroke-width=".18"/>
<path d="M239.4 159.4h3.8l-1.9 3.2z" fill="#a1a1a1"/>
<path d="M242.6 162.6h-2.6l-1.2 1.2" fill="none" stroke="#a1a1a1" stroke-width=".18"/>
<path d="M241.3 162.6l1.9 3.1h-3.8z" fill="#a1a1a1"/>
<path d="M221 147.3h2M223.1 146.3h6v2.1h-6zM229.1 147.3h2M241.3 154.9v4.5M237.8 162.2h.8M238.2 162v.8M241.3 165.7v4.5M243.8 161.3l-1.2 1.3" fill="none" stroke="#a1a1a1" stroke-width=".18"/>
<path d="M221.6 145.9l9 2.9M230.6 145.9l-9 2.9M237.3 156.5l8 12.1M245.3 156.5l-8 12.1" fill="none" stroke="#ff2626" stroke-width=".46"/>
<path d="M248.9 160v1.3h1.3l-1.3 1.3-1.3-1.3h1.3M248.9 160h.1" fill="none" stroke="#840000" stroke-width=".18"/>
<path d="M259.1 142.2h10.1v15.3h-10.1z" fill="#f0f0f0"/>
<path d="M259.1 142.2h10.1v15.3h-10.1z" fill="none" stroke="#9f9f9f" stroke-width=".18"/>
<g fill="none" stroke="#a1a1a1" stroke-width=".18">
<path d="M165.1 27.9h2M167.2 39.7h6v2h-6zM167.2 27h6v2h-6zM171.9 27.3l.1 .1a1.07 1.07 0 0 1-.1 1M172.1 27.8l-.2 .2M173.3 27.9h2M165.1 40.6h2M43.2 111.8h2M45.3 110.8h6v2h-6zM49.1 109.8h.8M51.3 111.8h2M261.6 114.3h2"/>
<path d="M263.7 113.3h6v2.1h-6zM269.8 114.3h2M33 139.7h2M35.1 138.7h6v2.1h-6zM39.5 139.2l.1-.2v1.3M41.2 139.7h2M45.7 139.7v2.5M39.2 140.3h.8M43.2 142.2h5.1l-1.3 2.6h-2.6zM61.5 146.8h4M61.5 147.8h4M63.5 142.2v4.6"/>
<path d="M63.5 147.8v4.6M251.5 144.8h7.6M251.5 147.3h7.6M251.5 149.9h7.6M251.5 152.4h7.6M251.5 154.9h7.6M262.4 158.7l.2-.2h.3l.1 .8M269.2 144.8h7.7M269.2 147.3h7.7M269.2 149.9h7.7M269.2 152.4h7.7M269.2 154.9h7.7"/>
</g>
<g fill="none" stroke="#ff2626" stroke-width=".46">
<path d="M165.7 39.2l9 2.9M165.7 26.5l9 2.9M174.7 39.2l-9 2.9M174.7 26.5l-9 2.9M43.8 110.4l9 2.8M52.8 110.4l-9 2.8M262.2 112.9l9 2.9M271.2 112.9l-9 2.9M33.6 138.3l9 2.9M42.6 138.3l-9 2.9M42.3 140.5l6.8 6M49.1 140.5l-6.8 6"/>
<path d="M60.6 143l5.8 8.6M66.4 143l-5.8 8.6M254.3 140.8l19.7 18.1M274 140.8l-19.7 18.1"/>
</g>
<g fill="none" stroke="#840000" stroke-width=".18">
<path d="M58.4 138.4l1-.6-1-.6-1 .6 1 .6v1.3M58.4 139.7h.1M53.3 154.9v1.3h1.3l-1.3 1.3-1.2-1.3h1.2M53.3 154.9h.1M158 146.8h4M158 147.8h4M160 154.9v1.3h1.3l-1.3 1.3-1.3-1.3h1.3M160 154.9h.1M160 142.2v4.6M160 147.8v4.6M168.2 146.8h4M168.2 147.8h4"/>
<path d="M170.2 154.9v1.3h1.2l-1.2 1.3-1.3-1.3h1.3M170.2 154.9h.1M170.2 142.2v4.6M170.2 147.8v4.6M178.3 146.8h4M178.3 147.8h4M180.3 154.9v1.3h1.3l-1.3 1.3-1.2-1.3h1.2M180.3 154.9h.1M180.3 142.2v4.6M180.3 147.8v4.6M22.9 177.8v2.5"/>
</g>
<path d="M182.9 134.6v2.6" fill="none" stroke="#840000" stroke-width=".25"/>
<circle cx="22.9" cy="181.6" r="1.27" fill="none" stroke="#000" stroke-width=".18"/>
<path d="M24.1 185.3h.7" fill="none" stroke="#008484" stroke-width=".18"/>
<path d="M264.2 22.9h5v20.3h-5z" fill="#f0f0f0"/>
<g fill="none" stroke="#a1a1a1" stroke-width=".18">
<path d="M263.7 59.9h6v2h-6zM268.1 45.2h.8M268.7 44.7v.9M261.6 61h2M267.6 64.1h.7M269.8 61h2M256.5 91.4h2M258.6 90.5h6v2h-6zM264.7 91.4h2"/>
<circle cx="266.7" cy="25.4" r="1.27"/>
<circle cx="266.7" cy="30.5" r="1.26"/>
<circle cx="266.7" cy="35.6" r="1.26"/>
<circle cx="266.7" cy="40.6" r="1.26"/>
</g>
<path d="M264.2 22.9h5v20.3h-5z" fill="none" stroke="#9f9f9f" stroke-width=".18"/>
<path d="M264.1 22.8l5.2 20.4M269.3 22.8l-5.2 20.4M262.2 59.5l9 2.9M271.2 59.5l-9 2.9M257.1 90l9 2.9M266.1 90l-9 2.9" fill="none" stroke="#ff2626" stroke-width=".46"/>
<path d="M276.9 63.5v1.3h1.2l-1.2 1.2-1.3-1.2h1.3M276.9 63.5h.1M266.7 104.1v1.3h-1.3l1.3 1.3 1.3-1.3h-1.3M266.7 104.1h.1M276.9 116.8v1.3h1.2l-1.2 1.3-1.3-1.3h1.3M276.9 116.8h.1M63.5 154.9v1.3h1.3l-1.3 1.3-1.3-1.3h1.3M63.5 154.9h.1" fill="none" stroke="#840000" stroke-width=".18"/>
<path d="M274.3 88.9h5.1v7.6h-5.1z" fill="#f0f0f0"/>
<path d="M274.3 88.9h5.1v7.6h-5.1z" fill="none" stroke="#9f9f9f" stroke-width=".18"/>
<g fill="none" stroke="#a1a1a1" stroke-width=".18">
<path d="M38.1 71.1h2.3M40.4 68.9v4.5M40.9 68.9v1M266.7 91.4h7.6M266.7 94h7.6M280.4 90.3a.42 .42 0 0 1-.4-.4 .42 .42 0 0 1 .4-.5h.4a.42 .42 0 0 1 .5 .5 .42 .42 0 0 1-.5 .4M280.6 87.3v-.6l-.2-.1-.3 .1-.1 .6h1.2M280.8 87.9v1M280.9 85.5v.6M281.2 86.6l-.6 .4M281.2 85.4l-1.2 .4 1.2 .4M281.4 89.4l-.5 .6"/>
<path d="M138.6 144.3h2.1v6h-2.1zM139.7 142.2v2M139.7 150.4v2M148.8 144.3h2v6h-2zM149.9 142.2v2M149.9 150.4v2M148.8 177.3h2v6h-2zM149.9 175.3v2M128.5 182.4h2v6h-2zM129.3 183l.5 .5M129.5 180.3v2M129.5 188.5v2"/>
<path d="M130.1 183l-.5 .4M137.7 184.9h4M137.7 185.9h4M139.7 180.3v4.6M139.7 185.9v4.6M147.4 187.1h.5M147.4 186.5h.6M149.9 183.4v2"/>
</g>
<path d="M269.5 87.4l14.7 10.6M284.2 87.4l-14.7 10.6M137.9 142.8l3.5 9M141.4 142.8l-3.5 9M148.1 142.8l3.5 9M151.6 142.8l-3.5 9M148.1 175.8l3.5 9M151.6 175.8l-3.5 9M127.8 180.9l3.4 9M131.2 180.9l-3.4 9M136.8 181.1l5.8 8.6M142.6 181.1l-5.8 8.6" fill="none" stroke="#ff2626" stroke-width=".46"/>
<path d="M266.7 101.6h1.3l.6 1 .6-1-.6-1-.6 1M129.5 190.5v1.3h1.3l-1.3 1.2-1.2-1.2h1.2M129.5 190.5h.1M139.7 190.5v1.3h1.3l-1.3 1.2-1.3-1.2h1.3M139.7 190.5h.1M149.9 190.5v1.3h1.2l-1.2 1.2-1.3-1.2h1.3M149.9 190.5h.1" fill="none" stroke="#840000" stroke-width=".18"/>
<path d="M40.9 71.1l1.5-.5v1z" fill="#a1a1a1"/>
<path d="M35.6 71.1h2.5M40.9 70.6v1M40.9 72.4v1M40.9 71.1h2.3v5.1M40.9 69.4h2.3M40.9 72.9h2.3M43.2 66v3.3M148.8 157h2v6h-2zM149.9 154.9v2M149.9 163.1v2" fill="none" stroke="#a1a1a1" stroke-width=".18"/>
<path d="M36.3 66.8l8.6 8.6M44.9 66.8l-8.6 8.6M148.1 155.5l3.5 9M151.6 155.5l-3.5 9" fill="none" stroke="#ff2626" stroke-width=".46"/>
<circle cx="135.9" cy="157.5" r="1.27" fill="none" stroke="#000" stroke-width=".18"/>
<path d="M137.2 157.5h2.5" fill="none" stroke="#840000" stroke-width=".18"/>
<path d="M101.6 137.2h20.3v50.8h-20.3z" fill="#f0f0f0"/>
<g fill="none" stroke="#a1a1a1" stroke-width=".18">
<path d="M165.1 48.3h2M165.1 50.8h2M165.1 58.4h2M165.1 55.9h2M165.1 43.2h2M165.1 40.6h2M29.4 75.7h2.1v6h-2.1zM30.5 73.7v2M165.1 66h2M165.1 63.5h2M165.5 79.9h.4M165.5 79.3h.6"/>
<path d="M167.6 76.2h2.6M170.2 78.7h2.5M175.3 76.2h2.5M179.2 77.4h.4M179.2 76.8h.6M30.5 81.8v2M165.5 95.2h.4M165.5 94.6h.6M165.5 87.5h.4M165.5 86.9h.6M167.6 91.4h2.6M167.6 99.1h2.6"/>
<path d="M167.6 83.8h2.6M170.2 94h2.5M170.2 86.4h2.5M175.3 91.4h2.5M175.3 99.1h2.5M175.3 83.8h2.5M179.2 92.6h.4M179.2 92h.6M179.2 99.6h.6M179.2 85h.4M179.2 84.4h.6M256.5 91.4h2"/>
<path d="M264.7 91.4h9.6M266.7 94h7.6M280.4 90.3a.42 .42 0 0 1-.4-.4 .42 .42 0 0 1 .4-.5h.4a.42 .42 0 0 1 .5 .5 .42 .42 0 0 1-.5 .4M280.6 87.3v-.6l-.2-.1-.3 .1-.1 .6h1.2M280.8 87.9v1M280.9 85.5v.6M281.2 86.6l-.6 .4M281.2 85.4l-1.2 .4 1.2 .4M281.4 89.4l-.5 .6M165.4 100.9h.7M165.5 102.8h.4M165.5 102.2h.6"/>
<path d="M165.5 115.5h.4M165.5 114.9h.6M167.6 111.8h2.6M170.2 101.6h2.5M170.2 114.3h2.5M179.2 112.9h.4M179.2 112.3h.6M179.2 100.2h.4M30.5 139.7v2.5M33 139.7h2M39.5 139.2l.1-.2v1.3M41.2 139.7h2"/>
<path d="M45.7 139.7v2.5M96.5 139.7h5.1M101.6 137.2h20.3v50.8h-20.3zM104.5 136.5h.7M121.9 139.7h5.1M39.2 140.3h.8M71.7 146.8h4M71.7 147.8h4M73.7 142.2v4.6M73.7 147.8v4.6M79 147.2h.8M81.4 149h.4"/>
<path d="M81.4 148.4h.6M83.8 144.8h2M85.9 143.7h6v2.1h-6zM92 144.8h2M96.5 144.8h5.1M96.5 149.9h5.1M96.5 154.9h5.1M96.5 157.5h5.1M110.4 144.1l.3 .1M110.7 145.2l-.3 .2M121.9 144.8h5.1M121.9 149.9h5.1"/>
<path d="M121.9 154.9h5.1M121.9 142.2h5.1M121.9 147.3h5.1M121.9 152.4h5.1M124.7 141.8h.7M126.6 159.6l.8 .8M127.4 159.6l-.8 .8M233.7 154.9v4.5M241.3 154.9v4.5M251.5 144.8h7.6M251.5 149.9h7.6M251.5 154.9h7.6"/>
<path d="M251.5 147.3h7.6M251.5 152.4h7.6M262.4 158.7l.2-.2h.3l.1 .8M269.2 144.8h7.7M269.2 149.9h7.7M269.2 154.9h7.7M269.2 147.3h7.7M269.2 152.4h7.7M25.4 177.8h2M30.3 176.7h.7M31.6 178.4h.8M31.9 177.3l.1-.2v1.3"/>
<path d="M33.6 177.8h2M96.5 160h5.1M96.5 162.6h5.1M96.5 165.1h5.1M96.5 167.6h5.1M96.5 170.2h5.1M96.5 172.7h5.1M96.5 175.3h5.1M96.5 177.8h5.1M120.5 179.6h.6M120.6 175.2l.3 .1 .2 .3-.3 .2h-.3M120.6 174.6h.5"/>
<path d="M121.9 160h5.1M121.9 165.1h5.1M121.9 170.2h5.1M121.9 175.3h5.1M124.7 174.8h.7M230.1 162.2h.9M230.6 162v.8M233.7 165.7v4.5M237.8 162.2h.8M238.2 162v.8M241.3 165.7v4.5M96.5 180.3h5.1"/>
<path d="M96.5 182.9h5.1M96.5 185.4h5.1M120.5 180.3h.4M120.8 188.5h.8l-.5 .5 .4 .1 .1 .5-.3 .2h-.3M121.9 180.3h5.1M129.3 183l.5 .5M129.5 180.3v2M129.5 188.5v2M130.1 183l-.5 .4M139.7 180.3v2.6M139.7 188v2.5M147.4 187.1h.5"/>
<path d="M147.4 186.5h.6"/>
</g>
<g fill="none" stroke="#ff2626" stroke-width=".46">
<path d="M165.7 39.2l9 2.9M174.7 39.2l-9 2.9M165.7 46.9l9 2.8M165.7 49.4l9 2.9M165.7 57l9 2.9M165.7 54.5l9 2.9M165.7 41.8l9 2.9M174.7 46.9l-9 2.8M174.7 49.4l-9 2.9M174.7 57l-9 2.9M174.7 54.5l-9 2.9M174.7 41.8l-9 2.9"/>
<path d="M28.7 74.2l3.5 9M32.2 74.2l-3.5 9M163.3 76.2l8.6 5.1M165.7 64.6l9 2.9M165.7 62.1l9 2.9M168.4 73.7l8.6 5M171.9 76.2l-8.6 5.1M174.7 64.6l-9 2.9M174.7 62.1l-9 2.9M177 73.7l-8.6 5M163.3 91.5l8.6 5M163.3 99.1l8.6 5"/>
<path d="M163.3 83.8l8.6 5.1M168.4 88.9l8.6 5.1M168.4 96.5l8.6 5.1M168.4 81.3l8.6 5M171.9 91.5l-8.6 5M171.9 99.1l-8.6 5M171.9 83.8l-8.6 5.1M177 88.9l-8.6 5.1M177 96.5l-8.6 5.1M177 81.3l-8.6 5M257.1 90l9 2.9M266.1 90l-9 2.9"/>
<path d="M269.5 87.4l14.7 10.6M284.2 87.4l-14.7 10.6M163.3 111.8l8.6 5M168.4 109.2l8.6 5.1M171.9 111.8l-8.6 5M177 109.2l-8.6 5.1M33.6 138.3l9 2.9M42.6 138.3l-9 2.9M98.3 136.2l26.9 52.7M125.2 136.2l-26.9 52.7M27.1 140.5l6.8 6M33.9 140.5l-6.8 6"/>
<path d="M42.3 140.5l6.8 6M49.1 140.5l-6.8 6M70.8 143l5.7 8.6M76.5 143l-5.7 8.6M84.4 143.3l9 2.9M93.4 143.3l-9 2.9M229.7 156.5l8 12.1M237.3 156.5l8 12.1M237.7 156.5l-8 12.1M245.3 156.5l-8 12.1M254.3 140.8l19.7 18.1M274 140.8l-19.7 18.1"/>
<path d="M26 176.4l9 2.9M35 176.4l-9 2.9M127.8 180.9l3.4 9M131.2 180.9l-3.4 9M136.8 181.1l5.8 8.6M142.6 181.1l-5.8 8.6"/>
</g>
<g fill="none" stroke="#840000" stroke-width=".18">
<path d="M30.5 86.4v1.2h1.2l-1.2 1.3-1.3-1.3h1.3M30.5 86.4h.1M43.2 86.4v1.2h1.2l-1.2 1.3-1.3-1.3h1.3M43.2 86.4h.1M266.7 104.1h.1M73.7 154.9v1.3h1.2l-1.2 1.3-1.3-1.3h1.3M73.7 154.9h.1M22.9 177.8v2.5M38.1 177.8v2.5M233.7 170.2v1.3h1.2l-1.2 1.2-1.3-1.2h1.3M233.7 170.2h.1M241.3 170.2h.1"/>
<path d="M276.9 160h.1M94 190.5v1.3h1.2l-1.2 1.2-1.3-1.2h1.3M94 190.5h.1M129.5 190.5h.1M139.7 190.5h.1M149.9 190.5h.1"/>
</g>
<path d="M203.2 34.9h.6l.7 .7-.7 .6h-.6zM203.2 27.3h.6l.7 .6-.7 .7h-.6zM203.8 70.5h.7v1.3h-.7l-.6-.7zM258.4 60.3h.7v1.3h-.7l-.6-.6zM255.3 90.8h.6l.6 .6-.6 .7h-.6zM203.2 111.1h.6l.7 .7-.7 .6h-.6zM203.2 113.7h.6l.7 .6-.7 .6h-.6zM257.8 114.3l.6-.6h.7v1.2h-.7zM207 152.4l.6-.6 .7 .6-.7 .6zM207 147.3l.6-.6 .7 .6-.7 .7z" fill="none" stroke="#848400" stroke-width=".18"/>
<g fill="none" stroke="#000" stroke-width=".18">
<path d="M68 37.5h.5M68 36.8l.4-.1 .2 .3-.6 .2M68 39.3h.4l.2 .3-.6 .1M68 34.3l.4-.1 .2 .3-.6 .1M68 35h.5M108.3 37.5h.5M108.3 36.8l.4-.1 .2 .3-.6 .2M108.3 39.3h.4l.2 .3-.6 .1M65.1 57.1l.7 .8M65.8 57.1l-.7 .8M68 40.1h.5M108.3 40.1h.5"/>
<path d="M68.3 75.7h.7M68.5 74.6l.1-.2v1.3M68.3 110.8h.7M27.4 139.1h.5M27.4 138.4l.3-.1 .2 .3-.6 .2M95.5 137.9h.5l.2 .3-.1 .3-.6 .1M95.8 138.6l.4 .6"/>
</g>
<path d="M246.4 12.7v35.6M246.4 48.3v25.4M284.5 48.3h-38.1M246.4 73.7v50.8M284.5 73.7h-38.1M12.7 124.5h271.8M193 177.8v-53.3" fill="none" stroke="#0000c2" stroke-width=".18" stroke-dasharray="1.4 .5"/>
<path d="M203.2 35.6h-5.1v27.9M203.2 71.1h-5.1v28" fill="none" stroke="#000084" stroke-width=".25"/>
<g fill="none" stroke="#008400" stroke-width=".18">
<path d="M58.4 35.6h15.3M58.4 38.1h15.3M94 35.6h15.2M94 38.1h15.2M144.8 27.9h20.3M175.3 27.9h27.9M198.1 38.1l-2.5 2.5h-20.3M58.4 40.6h15.3M58.4 48.3h15.3M58.4 55.9h15.3M58.4 58.4h15.3M58.4 50.8h15.3"/>
<path d="M58.4 43.2h15.3M58.4 53.3h15.3M58.4 45.7h15.3M94 40.6h15.2M94 48.3h15.2M94 55.9h15.2M94 58.4h15.2M94 50.8h15.2M94 43.2h15.2M94 53.3h15.2M94 45.7h15.2M144.8 40.6h20.3"/>
<path d="M144.8 48.3h20.3M144.8 55.9h20.3M144.8 58.4h20.3M144.8 50.8h20.3M144.8 43.2h20.3M198.1 45.7l-2.5 2.6h-20.3M198.1 53.3l-2.5 2.6h-20.3M198.1 55.9l-2.5 2.5h-20.3M198.1 48.3l-2.5 2.5h-20.3M198.1 40.6l-2.5 2.6h-20.3M17.8 71.1h17.8M30.5 71.1v2.6"/>
<path d="M43.2 76.2v10.2M58.4 66h15.3M58.4 76.2h15.3M58.4 78.7h15.3M58.4 68.6h15.3M58.4 71.1h15.3M58.4 73.7h15.3M58.4 61h15.3M73.7 63.5h-30.5v2.5M94 63.5h15.2M94 66h15.2M94 76.2h15.2"/>
<path d="M94 78.7h15.2M94 68.6h15.2M94 71.1h15.2M94 73.7h15.2M94 61h15.2M144.8 63.5h20.3M144.8 66h20.3M144.8 76.2h22.8M144.8 78.7h17.8M198.1 61l-2.5 2.5h-20.3M198.1 63.5l-2.5 2.5h-20.3M198.1 73.7l-2.5 2.5h-17.8"/>
<path d="M198.1 76.2l-2.5 2.5h-22.9M259.1 61h2.5M271.8 61h5.1v2.5M30.5 83.8v2.6M58.4 83.8h15.3M58.4 91.4h15.3M58.4 94h15.3M58.4 86.4h15.3M58.4 99.1h15.3M58.4 81.3h15.3M58.4 96.5h15.3M58.4 88.9h15.3"/>
<path d="M94 83.8h15.2M94 91.4h15.2M94 94h15.2M94 86.4h15.2M94 99.1h15.2M94 81.3h15.2M94 96.5h15.2M94 88.9h15.2M144.8 83.8h22.8M144.8 91.4h22.8M144.8 94h17.8M144.8 86.4h17.8"/>
<path d="M144.8 99.1h22.8M198.1 81.3l-2.5 2.5h-17.8M198.1 88.9l-2.5 2.5h-17.8M198.1 91.4l-2.5 2.6h-22.9M198.1 83.8l-2.5 2.6h-22.9M198.1 96.5l-2.5 2.6h-17.8M198.1 99.1l-2.5 2.5h-22.9M266.7 94v10.1M30.5 111.8h12.7M53.3 111.8h20.4M58.4 114.3h15.3M58.4 101.6h15.3"/>
<path d="M58.4 104.1h15.3M58.4 109.2h15.3M58.4 106.7h15.3M94 114.3h15.2M94 101.6h15.2M94 111.8h15.2M94 104.1h15.2M94 109.2h15.2M94 106.7h15.2M144.8 114.3h17.8M144.8 101.6h17.8M144.8 111.8h22.8"/>
<path d="M172.7 114.3h30.5M177.8 111.8h25.4M259.1 114.3h2.5M271.8 114.3h5.1v2.5M17.8 139.7h15.2M43.2 139.7h53.3M53.3 139.7v2.5M63.5 139.7v2.5M73.7 139.7v2.5M81.3 139.7v5.1h2.5M129.5 139.7v15.2h-2.5M139.7 139.7v2.5"/>
<path d="M149.9 139.7v2.5M160 139.7v2.5M170.2 139.7v2.5M180.3 139.7v2.5M182.9 137.2v2.5h-55.9M17.8 149.9h12.7v2.5M53.3 152.4v2.5M63.5 152.4v2.5M73.7 152.4v2.5M94 154.9h2.5M94 144.8h2.5M94 157.5h2.5"/>
<path d="M96.5 149.9h-2.5v40.6M127 147.3h2.5M127 152.4h2.5M127 149.9h2.5M127 144.8h2.5M127 142.2h2.5M139.7 152.4v12.7h-12.7M149.9 152.4v2.5M160 152.4v2.5M170.2 152.4v2.5M180.3 152.4v2.5M208.3 147.3h12.7"/>
<path d="M208.3 152.4h12.7M231.1 147.3h20.4M231.1 152.4h20.4M233.7 147.3v7.6M241.3 152.4v2.5M248.9 154.9h2.6M248.9 149.9h2.6M251.5 144.8h-2.6v15.2M276.9 144.8v15.2M20.3 175.3v2.5h5.1M40.6 175.3v2.5h-5M94 177.8h2.5"/>
<path d="M94 167.6h2.5M94 165.1h2.5M94 172.7h2.5M94 170.2h2.5M94 160h2.5M94 162.6h2.5M94 175.3h2.5M127 175.3h12.7v5M127 170.2h22.9M149.9 165.1v10.2M94 180.3h2.5M94 182.9h2.5"/>
<path d="M94 185.4h2.5M127 180.3h2.5M149.9 185.4v5.1"/>
</g>
<g fill="none" stroke="#000084" stroke-width=".18">
<path d="M57.8 47.7l1.2 1.2M57.8 45.1l1.2 1.2M57.8 55.3l1.2 1.2M57.8 57.8l1.2 1.2M57.8 52.7l1.2 1.2M59 47.7l-1.2 1.2M59 45.1l-1.2 1.2M59 55.3l-1.2 1.2M59 57.8l-1.2 1.2M59 52.7l-1.2 1.2M108.6 45.1l1.2 1.2M108.6 55.3l1.2 1.2"/>
<path d="M108.6 52.7l1.2 1.2M108.6 57.8l1.2 1.2M108.6 50.2l1.2 1.2M108.6 47.7l1.2 1.2M109.8 45.1l-1.2 1.2M109.8 55.3l-1.2 1.2M109.8 52.7l-1.2 1.2M109.8 57.8l-1.2 1.2M109.8 50.2l-1.2 1.2M109.8 47.7l-1.2 1.2M57.8 75.6l1.2 1.2M57.8 60.4l1.2 1.2"/>
<path d="M59 75.6l-1.2 1.2M59 60.4l-1.2 1.2M108.6 80.7l1.2 1.2M109.8 80.7l-1.2 1.2M57.8 108.6l1.2 1.2M59 108.6l-1.2 1.2M108.6 113.7l1.2 1.2M109.8 113.7l-1.2 1.2"/>
</g>
<g fill="none" stroke="#0000c2" stroke-width=".38">
<path d="M16.9 15.2l-.2-.1h-.8v1.9M18.9 15.2a.66 .66 0 0 0-1 .1M19.8 15.1v1.9M25.7 15l-.5 1.3M28.6 16h.6M29.5 15.1h-.9v1.9h.9M31.1 15.1v1.9M37.9 15.2a.77 .77 0 0 0-.9 0 .77 .77 0 0 0-.3 .9 .73 .73 0 0 0 .3 .7 .73 .73 0 0 0 .8 .1M47.1 15.1v1.6M250.6 15.2l-.3-.1h-.7v1.9M252.6 15.2a.66 .66 0 0 0-1 .1M253.4 15.1v1.9"/>
<path d="M257.4 15.1v1.9M263.7 15.1v1.9M266.9 15.1v1.6M249.4 50.6l.6 1.9 .6-1.9M254.2 50.6l-.1 .1 .1 .1M254.2 50.6l.1 .1-.1 .1M254.2 50.6v.2M258.2 51.3h.8M258.5 50.6v1.7M258.6 52.4l.4 .1M262.1 50.8l-.3-.2h-.7v1.9M263 50.6l-.1 .1 .1 .1"/>
<path d="M263 50.6v.1v.1M263 50.6v.2M267 52.4l.2 .1M268 50.7l-.2-.1-.7 .1a.43 .43 0 0 0-.1 .6M268.9 50.6v1.7M250.6 76.2l-.3-.2h-.7v1.9M254.4 76v1.9M260.3 76.2a.66 .66 0 0 0-1 .1M16.9 126.8h-1v.9M17.5 126.8l.6 1.9 .7-1.9M19.2 126.8h1.2l-.6 .7M23.6 127l-.3-.2h-.6v1.9"/>
<path d="M27.9 126.8v1.9M32 127a.77 .77 0 0 0-.9 0 .77 .77 0 0 0-.3 .9l.2 .6M40.5 126.8v1.7M197.3 127l-.3-.2h-.7v1.9M200.3 126.8l-.4 .1-.1 .2M202.5 126.8v1.7M206.9 126.8v1.9M207.1 128l.5 .7M207.6 127.5l-.7 .7M214.2 126.8v1.9M216.4 128.6l.3 .1M217.5 126.9l-.3-.1-.6 .1a.43 .43 0 0 0-.1 .6"/>
<path d="M224.6 126.8v1.9M224.6 127.7h1.1M225.7 126.8v1.9M230.8 126.8v1.9"/>
</g>
<g fill="none" stroke="#0000c2" stroke-width=".18">
<path d="M181.5 16.1l-.2 .1M182 16.6l-.7 .8h.8M184.7 19.9h.8M185 18.8l-.3 .2M68 52.9h.5M68 52.1h.4l.2 .3-.6 .1M108.3 55.4h.5M108.3 54.7l.4-.1 .2 .3-.6 .1M108.3 57.2h.4l.2 .3-.6 .1M108.3 57.9h.5M177.2 169.1a1.49 1.49 0 0 1 0 1.8M179 169.2l-1.1 1.6"/>
<path d="M179.4 170.5h.7M179.4 169.6l.3-.4v1.3M180.1 167.4l.6-.1 .2-.2-.1-.3-.7-.1v1.3M180.4 167.4l.5 .6M181.3 166.8l.5-.1 .3 .4-.8 .9h.8"/>
</g>
<path d="M24.1 185.3h.7" fill="none" stroke="#008484" stroke-width=".18"/>
<g fill="#008400" stroke="#008400" stroke-width=".18">
<circle cx="266.7" cy="101.6" r=".46"/>
<circle cx="30.5" cy="71.1" r=".46"/>
<circle cx="129.5" cy="147.3" r=".46"/>
<circle cx="129.5" cy="149.9" r=".46"/>
<circle cx="139.7" cy="139.7" r=".46"/>
<circle cx="129.5" cy="142.2" r=".46"/>
<circle cx="129.5" cy="144.8" r=".46"/>
<circle cx="129.5" cy="139.7" r=".46"/>
<circle cx="45.7" cy="139.7" r=".46"/>
<circle cx="38.1" cy="177.8" r=".46"/>
<circle cx="63.5" cy="139.7" r=".46"/>
<circle cx="22.9" cy="177.8" r=".46"/>
<circle cx="30.5" cy="139.7" r=".46"/>
<circle cx="53.3" cy="139.7" r=".46"/>
<circle cx="58.4" cy="139.7" r=".46"/>
<circle cx="94" cy="180.3" r=".46"/>
<circle cx="94" cy="177.8" r=".46"/>
<circle cx="94" cy="157.5" r=".46"/>
<circle cx="94" cy="154.9" r=".46"/>
<circle cx="81.3" cy="139.7" r=".46"/>
<circle cx="73.7" cy="139.7" r=".46"/>
<circle cx="94" cy="185.4" r=".46"/>
<circle cx="94" cy="182.9" r=".46"/>
<circle cx="94" cy="160" r=".46"/>
<circle cx="94" cy="162.6" r=".46"/>
<circle cx="94" cy="172.7" r=".46"/>
<circle cx="94" cy="167.6" r=".46"/>
<circle cx="94" cy="170.2" r=".46"/>
<circle cx="94" cy="175.3" r=".46"/>
<circle cx="94" cy="165.1" r=".46"/>
<circle cx="129.5" cy="152.4" r=".46"/>
<circle cx="149.9" cy="139.7" r=".46"/>
<circle cx="139.7" cy="157.5" r=".46"/>
<circle cx="149.9" cy="170.2" r=".46"/>
<circle cx="160" cy="139.7" r=".46"/>
<circle cx="170.2" cy="139.7" r=".46"/>
<circle cx="180.3" cy="139.7" r=".46"/>
<circle cx="276.9" cy="149.9" r=".46"/>
<circle cx="276.9" cy="147.3" r=".46"/>
<circle cx="276.9" cy="152.4" r=".46"/>
<circle cx="276.9" cy="154.9" r=".46"/>
<circle cx="248.9" cy="154.9" r=".46"/>
<circle cx="248.9" cy="149.9" r=".46"/>
<circle cx="233.7" cy="147.3" r=".46"/>
<circle cx="241.3" cy="152.4" r=".46"/>
</g>
<use href="#words"/>
</svg>
